# OpenTallas memory compiler (tools/mem_compiler), ASAP7 abstract view, track-aligned v2 (build_aligned_v2.py)
VERSION 5.7 ;
BUSBITCHARS "[]" ;
DIVIDERCHAR "/" ;
PROPERTYDEFINITIONS
  MACRO width INTEGER ;
  MACRO depth INTEGER ;
  MACRO banks INTEGER ;
END PROPERTYDEFINITIONS
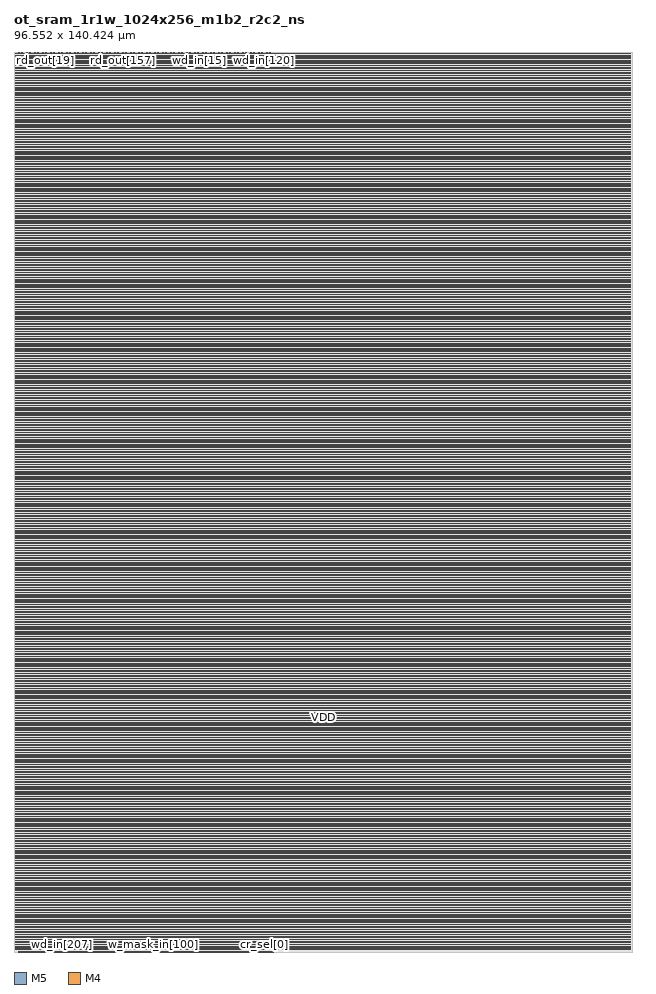
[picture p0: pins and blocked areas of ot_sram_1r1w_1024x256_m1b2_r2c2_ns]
MACRO ot_sram_1r1w_1024x256_m1b2_r2c2_ns
  PROPERTY width 256 ;
  PROPERTY depth 1024 ;
  PROPERTY banks 2 ;
  FOREIGN ot_sram_1r1w_1024x256_m1b2_r2c2_ns 0 0 ;
  SYMMETRY X Y ;
  SIZE 96.552 BY 140.424 ;
  CLASS BLOCK ;
  PIN clk
    DIRECTION INPUT ;
    USE CLOCK ;
    SHAPE ABUTMENT ;
    PORT
      LAYER M5 ;
      RECT 0.768 140.400 0.792 140.424 ;
    END
  END clk
  PIN r_ce_in
    DIRECTION INPUT ;
    USE SIGNAL ;
    SHAPE ABUTMENT ;
    PORT
      LAYER M5 ;
      RECT 0.864 140.400 0.888 140.424 ;
    END
  END r_ce_in
  PIN r_addr_in[0]
    DIRECTION INPUT ;
    USE SIGNAL ;
    SHAPE ABUTMENT ;
    PORT
      LAYER M5 ;
      RECT 0.960 140.400 0.984 140.424 ;
    END
  END r_addr_in[0]
  PIN r_addr_in[1]
    DIRECTION INPUT ;
    USE SIGNAL ;
    SHAPE ABUTMENT ;
    PORT
      LAYER M5 ;
      RECT 1.056 140.400 1.080 140.424 ;
    END
  END r_addr_in[1]
  PIN r_addr_in[2]
    DIRECTION INPUT ;
    USE SIGNAL ;
    SHAPE ABUTMENT ;
    PORT
      LAYER M5 ;
      RECT 1.152 140.400 1.176 140.424 ;
    END
  END r_addr_in[2]
  PIN r_addr_in[3]
    DIRECTION INPUT ;
    USE SIGNAL ;
    SHAPE ABUTMENT ;
    PORT
      LAYER M5 ;
      RECT 1.248 140.400 1.272 140.424 ;
    END
  END r_addr_in[3]
  PIN r_addr_in[4]
    DIRECTION INPUT ;
    USE SIGNAL ;
    SHAPE ABUTMENT ;
    PORT
      LAYER M5 ;
      RECT 1.344 140.400 1.368 140.424 ;
    END
  END r_addr_in[4]
  PIN r_addr_in[5]
    DIRECTION INPUT ;
    USE SIGNAL ;
    SHAPE ABUTMENT ;
    PORT
      LAYER M5 ;
      RECT 1.440 140.400 1.464 140.424 ;
    END
  END r_addr_in[5]
  PIN r_addr_in[6]
    DIRECTION INPUT ;
    USE SIGNAL ;
    SHAPE ABUTMENT ;
    PORT
      LAYER M5 ;
      RECT 1.536 140.400 1.560 140.424 ;
    END
  END r_addr_in[6]
  PIN r_addr_in[7]
    DIRECTION INPUT ;
    USE SIGNAL ;
    SHAPE ABUTMENT ;
    PORT
      LAYER M5 ;
      RECT 1.632 140.400 1.656 140.424 ;
    END
  END r_addr_in[7]
  PIN r_addr_in[8]
    DIRECTION INPUT ;
    USE SIGNAL ;
    SHAPE ABUTMENT ;
    PORT
      LAYER M5 ;
      RECT 1.728 140.400 1.752 140.424 ;
    END
  END r_addr_in[8]
  PIN r_addr_in[9]
    DIRECTION INPUT ;
    USE SIGNAL ;
    SHAPE ABUTMENT ;
    PORT
      LAYER M5 ;
      RECT 1.824 140.400 1.848 140.424 ;
    END
  END r_addr_in[9]
  PIN rd_out[0]
    DIRECTION OUTPUT ;
    USE SIGNAL ;
    SHAPE ABUTMENT ;
    PORT
      LAYER M5 ;
      RECT 1.920 140.400 1.944 140.424 ;
    END
  END rd_out[0]
  PIN rd_out[1]
    DIRECTION OUTPUT ;
    USE SIGNAL ;
    SHAPE ABUTMENT ;
    PORT
      LAYER M5 ;
      RECT 2.016 140.400 2.040 140.424 ;
    END
  END rd_out[1]
  PIN rd_out[2]
    DIRECTION OUTPUT ;
    USE SIGNAL ;
    SHAPE ABUTMENT ;
    PORT
      LAYER M5 ;
      RECT 2.112 140.400 2.136 140.424 ;
    END
  END rd_out[2]
  PIN rd_out[3]
    DIRECTION OUTPUT ;
    USE SIGNAL ;
    SHAPE ABUTMENT ;
    PORT
      LAYER M5 ;
      RECT 2.208 140.400 2.232 140.424 ;
    END
  END rd_out[3]
  PIN rd_out[4]
    DIRECTION OUTPUT ;
    USE SIGNAL ;
    SHAPE ABUTMENT ;
    PORT
      LAYER M5 ;
      RECT 2.304 140.400 2.328 140.424 ;
    END
  END rd_out[4]
  PIN rd_out[5]
    DIRECTION OUTPUT ;
    USE SIGNAL ;
    SHAPE ABUTMENT ;
    PORT
      LAYER M5 ;
      RECT 2.400 140.400 2.424 140.424 ;
    END
  END rd_out[5]
  PIN rd_out[6]
    DIRECTION OUTPUT ;
    USE SIGNAL ;
    SHAPE ABUTMENT ;
    PORT
      LAYER M5 ;
      RECT 2.496 140.400 2.520 140.424 ;
    END
  END rd_out[6]
  PIN rd_out[7]
    DIRECTION OUTPUT ;
    USE SIGNAL ;
    SHAPE ABUTMENT ;
    PORT
      LAYER M5 ;
      RECT 2.592 140.400 2.616 140.424 ;
    END
  END rd_out[7]
  PIN rd_out[8]
    DIRECTION OUTPUT ;
    USE SIGNAL ;
    SHAPE ABUTMENT ;
    PORT
      LAYER M5 ;
      RECT 2.688 140.400 2.712 140.424 ;
    END
  END rd_out[8]
  PIN rd_out[9]
    DIRECTION OUTPUT ;
    USE SIGNAL ;
    SHAPE ABUTMENT ;
    PORT
      LAYER M5 ;
      RECT 2.784 140.400 2.808 140.424 ;
    END
  END rd_out[9]
  PIN rd_out[10]
    DIRECTION OUTPUT ;
    USE SIGNAL ;
    SHAPE ABUTMENT ;
    PORT
      LAYER M5 ;
      RECT 2.880 140.400 2.904 140.424 ;
    END
  END rd_out[10]
  PIN rd_out[11]
    DIRECTION OUTPUT ;
    USE SIGNAL ;
    SHAPE ABUTMENT ;
    PORT
      LAYER M5 ;
      RECT 2.976 140.400 3.000 140.424 ;
    END
  END rd_out[11]
  PIN rd_out[12]
    DIRECTION OUTPUT ;
    USE SIGNAL ;
    SHAPE ABUTMENT ;
    PORT
      LAYER M5 ;
      RECT 3.072 140.400 3.096 140.424 ;
    END
  END rd_out[12]
  PIN rd_out[13]
    DIRECTION OUTPUT ;
    USE SIGNAL ;
    SHAPE ABUTMENT ;
    PORT
      LAYER M5 ;
      RECT 3.168 140.400 3.192 140.424 ;
    END
  END rd_out[13]
  PIN rd_out[14]
    DIRECTION OUTPUT ;
    USE SIGNAL ;
    SHAPE ABUTMENT ;
    PORT
      LAYER M5 ;
      RECT 3.264 140.400 3.288 140.424 ;
    END
  END rd_out[14]
  PIN rd_out[15]
    DIRECTION OUTPUT ;
    USE SIGNAL ;
    SHAPE ABUTMENT ;
    PORT
      LAYER M5 ;
      RECT 3.360 140.400 3.384 140.424 ;
    END
  END rd_out[15]
  PIN rd_out[16]
    DIRECTION OUTPUT ;
    USE SIGNAL ;
    SHAPE ABUTMENT ;
    PORT
      LAYER M5 ;
      RECT 3.456 140.400 3.480 140.424 ;
    END
  END rd_out[16]
  PIN rd_out[17]
    DIRECTION OUTPUT ;
    USE SIGNAL ;
    SHAPE ABUTMENT ;
    PORT
      LAYER M5 ;
      RECT 3.552 140.400 3.576 140.424 ;
    END
  END rd_out[17]
  PIN rd_out[18]
    DIRECTION OUTPUT ;
    USE SIGNAL ;
    SHAPE ABUTMENT ;
    PORT
      LAYER M5 ;
      RECT 3.648 140.400 3.672 140.424 ;
    END
  END rd_out[18]
  PIN rd_out[19]
    DIRECTION OUTPUT ;
    USE SIGNAL ;
    SHAPE ABUTMENT ;
    PORT
      LAYER M5 ;
      RECT 3.744 140.400 3.768 140.424 ;
    END
  END rd_out[19]
  PIN rd_out[20]
    DIRECTION OUTPUT ;
    USE SIGNAL ;
    SHAPE ABUTMENT ;
    PORT
      LAYER M5 ;
      RECT 3.840 140.400 3.864 140.424 ;
    END
  END rd_out[20]
  PIN rd_out[21]
    DIRECTION OUTPUT ;
    USE SIGNAL ;
    SHAPE ABUTMENT ;
    PORT
      LAYER M5 ;
      RECT 3.936 140.400 3.960 140.424 ;
    END
  END rd_out[21]
  PIN rd_out[22]
    DIRECTION OUTPUT ;
    USE SIGNAL ;
    SHAPE ABUTMENT ;
    PORT
      LAYER M5 ;
      RECT 4.032 140.400 4.056 140.424 ;
    END
  END rd_out[22]
  PIN rd_out[23]
    DIRECTION OUTPUT ;
    USE SIGNAL ;
    SHAPE ABUTMENT ;
    PORT
      LAYER M5 ;
      RECT 4.128 140.400 4.152 140.424 ;
    END
  END rd_out[23]
  PIN rd_out[24]
    DIRECTION OUTPUT ;
    USE SIGNAL ;
    SHAPE ABUTMENT ;
    PORT
      LAYER M5 ;
      RECT 4.224 140.400 4.248 140.424 ;
    END
  END rd_out[24]
  PIN rd_out[25]
    DIRECTION OUTPUT ;
    USE SIGNAL ;
    SHAPE ABUTMENT ;
    PORT
      LAYER M5 ;
      RECT 4.320 140.400 4.344 140.424 ;
    END
  END rd_out[25]
  PIN rd_out[26]
    DIRECTION OUTPUT ;
    USE SIGNAL ;
    SHAPE ABUTMENT ;
    PORT
      LAYER M5 ;
      RECT 4.416 140.400 4.440 140.424 ;
    END
  END rd_out[26]
  PIN rd_out[27]
    DIRECTION OUTPUT ;
    USE SIGNAL ;
    SHAPE ABUTMENT ;
    PORT
      LAYER M5 ;
      RECT 4.512 140.400 4.536 140.424 ;
    END
  END rd_out[27]
  PIN rd_out[28]
    DIRECTION OUTPUT ;
    USE SIGNAL ;
    SHAPE ABUTMENT ;
    PORT
      LAYER M5 ;
      RECT 4.608 140.400 4.632 140.424 ;
    END
  END rd_out[28]
  PIN rd_out[29]
    DIRECTION OUTPUT ;
    USE SIGNAL ;
    SHAPE ABUTMENT ;
    PORT
      LAYER M5 ;
      RECT 4.704 140.400 4.728 140.424 ;
    END
  END rd_out[29]
  PIN rd_out[30]
    DIRECTION OUTPUT ;
    USE SIGNAL ;
    SHAPE ABUTMENT ;
    PORT
      LAYER M5 ;
      RECT 4.800 140.400 4.824 140.424 ;
    END
  END rd_out[30]
  PIN rd_out[31]
    DIRECTION OUTPUT ;
    USE SIGNAL ;
    SHAPE ABUTMENT ;
    PORT
      LAYER M5 ;
      RECT 4.896 140.400 4.920 140.424 ;
    END
  END rd_out[31]
  PIN rd_out[32]
    DIRECTION OUTPUT ;
    USE SIGNAL ;
    SHAPE ABUTMENT ;
    PORT
      LAYER M5 ;
      RECT 4.992 140.400 5.016 140.424 ;
    END
  END rd_out[32]
  PIN rd_out[33]
    DIRECTION OUTPUT ;
    USE SIGNAL ;
    SHAPE ABUTMENT ;
    PORT
      LAYER M5 ;
      RECT 5.088 140.400 5.112 140.424 ;
    END
  END rd_out[33]
  PIN rd_out[34]
    DIRECTION OUTPUT ;
    USE SIGNAL ;
    SHAPE ABUTMENT ;
    PORT
      LAYER M5 ;
      RECT 5.184 140.400 5.208 140.424 ;
    END
  END rd_out[34]
  PIN rd_out[35]
    DIRECTION OUTPUT ;
    USE SIGNAL ;
    SHAPE ABUTMENT ;
    PORT
      LAYER M5 ;
      RECT 5.280 140.400 5.304 140.424 ;
    END
  END rd_out[35]
  PIN rd_out[36]
    DIRECTION OUTPUT ;
    USE SIGNAL ;
    SHAPE ABUTMENT ;
    PORT
      LAYER M5 ;
      RECT 5.376 140.400 5.400 140.424 ;
    END
  END rd_out[36]
  PIN rd_out[37]
    DIRECTION OUTPUT ;
    USE SIGNAL ;
    SHAPE ABUTMENT ;
    PORT
      LAYER M5 ;
      RECT 5.472 140.400 5.496 140.424 ;
    END
  END rd_out[37]
  PIN rd_out[38]
    DIRECTION OUTPUT ;
    USE SIGNAL ;
    SHAPE ABUTMENT ;
    PORT
      LAYER M5 ;
      RECT 5.568 140.400 5.592 140.424 ;
    END
  END rd_out[38]
  PIN rd_out[39]
    DIRECTION OUTPUT ;
    USE SIGNAL ;
    SHAPE ABUTMENT ;
    PORT
      LAYER M5 ;
      RECT 5.664 140.400 5.688 140.424 ;
    END
  END rd_out[39]
  PIN rd_out[40]
    DIRECTION OUTPUT ;
    USE SIGNAL ;
    SHAPE ABUTMENT ;
    PORT
      LAYER M5 ;
      RECT 5.760 140.400 5.784 140.424 ;
    END
  END rd_out[40]
  PIN rd_out[41]
    DIRECTION OUTPUT ;
    USE SIGNAL ;
    SHAPE ABUTMENT ;
    PORT
      LAYER M5 ;
      RECT 5.856 140.400 5.880 140.424 ;
    END
  END rd_out[41]
  PIN rd_out[42]
    DIRECTION OUTPUT ;
    USE SIGNAL ;
    SHAPE ABUTMENT ;
    PORT
      LAYER M5 ;
      RECT 5.952 140.400 5.976 140.424 ;
    END
  END rd_out[42]
  PIN rd_out[43]
    DIRECTION OUTPUT ;
    USE SIGNAL ;
    SHAPE ABUTMENT ;
    PORT
      LAYER M5 ;
      RECT 6.048 140.400 6.072 140.424 ;
    END
  END rd_out[43]
  PIN rd_out[44]
    DIRECTION OUTPUT ;
    USE SIGNAL ;
    SHAPE ABUTMENT ;
    PORT
      LAYER M5 ;
      RECT 6.144 140.400 6.168 140.424 ;
    END
  END rd_out[44]
  PIN rd_out[45]
    DIRECTION OUTPUT ;
    USE SIGNAL ;
    SHAPE ABUTMENT ;
    PORT
      LAYER M5 ;
      RECT 6.240 140.400 6.264 140.424 ;
    END
  END rd_out[45]
  PIN rd_out[46]
    DIRECTION OUTPUT ;
    USE SIGNAL ;
    SHAPE ABUTMENT ;
    PORT
      LAYER M5 ;
      RECT 6.336 140.400 6.360 140.424 ;
    END
  END rd_out[46]
  PIN rd_out[47]
    DIRECTION OUTPUT ;
    USE SIGNAL ;
    SHAPE ABUTMENT ;
    PORT
      LAYER M5 ;
      RECT 6.432 140.400 6.456 140.424 ;
    END
  END rd_out[47]
  PIN rd_out[48]
    DIRECTION OUTPUT ;
    USE SIGNAL ;
    SHAPE ABUTMENT ;
    PORT
      LAYER M5 ;
      RECT 6.528 140.400 6.552 140.424 ;
    END
  END rd_out[48]
  PIN rd_out[49]
    DIRECTION OUTPUT ;
    USE SIGNAL ;
    SHAPE ABUTMENT ;
    PORT
      LAYER M5 ;
      RECT 6.624 140.400 6.648 140.424 ;
    END
  END rd_out[49]
  PIN rd_out[50]
    DIRECTION OUTPUT ;
    USE SIGNAL ;
    SHAPE ABUTMENT ;
    PORT
      LAYER M5 ;
      RECT 6.720 140.400 6.744 140.424 ;
    END
  END rd_out[50]
  PIN rd_out[51]
    DIRECTION OUTPUT ;
    USE SIGNAL ;
    SHAPE ABUTMENT ;
    PORT
      LAYER M5 ;
      RECT 6.816 140.400 6.840 140.424 ;
    END
  END rd_out[51]
  PIN rd_out[52]
    DIRECTION OUTPUT ;
    USE SIGNAL ;
    SHAPE ABUTMENT ;
    PORT
      LAYER M5 ;
      RECT 6.912 140.400 6.936 140.424 ;
    END
  END rd_out[52]
  PIN rd_out[53]
    DIRECTION OUTPUT ;
    USE SIGNAL ;
    SHAPE ABUTMENT ;
    PORT
      LAYER M5 ;
      RECT 7.008 140.400 7.032 140.424 ;
    END
  END rd_out[53]
  PIN rd_out[54]
    DIRECTION OUTPUT ;
    USE SIGNAL ;
    SHAPE ABUTMENT ;
    PORT
      LAYER M5 ;
      RECT 7.104 140.400 7.128 140.424 ;
    END
  END rd_out[54]
  PIN rd_out[55]
    DIRECTION OUTPUT ;
    USE SIGNAL ;
    SHAPE ABUTMENT ;
    PORT
      LAYER M5 ;
      RECT 7.200 140.400 7.224 140.424 ;
    END
  END rd_out[55]
  PIN rd_out[56]
    DIRECTION OUTPUT ;
    USE SIGNAL ;
    SHAPE ABUTMENT ;
    PORT
      LAYER M5 ;
      RECT 7.296 140.400 7.320 140.424 ;
    END
  END rd_out[56]
  PIN rd_out[57]
    DIRECTION OUTPUT ;
    USE SIGNAL ;
    SHAPE ABUTMENT ;
    PORT
      LAYER M5 ;
      RECT 7.392 140.400 7.416 140.424 ;
    END
  END rd_out[57]
  PIN rd_out[58]
    DIRECTION OUTPUT ;
    USE SIGNAL ;
    SHAPE ABUTMENT ;
    PORT
      LAYER M5 ;
      RECT 7.488 140.400 7.512 140.424 ;
    END
  END rd_out[58]
  PIN rd_out[59]
    DIRECTION OUTPUT ;
    USE SIGNAL ;
    SHAPE ABUTMENT ;
    PORT
      LAYER M5 ;
      RECT 7.584 140.400 7.608 140.424 ;
    END
  END rd_out[59]
  PIN rd_out[60]
    DIRECTION OUTPUT ;
    USE SIGNAL ;
    SHAPE ABUTMENT ;
    PORT
      LAYER M5 ;
      RECT 7.680 140.400 7.704 140.424 ;
    END
  END rd_out[60]
  PIN rd_out[61]
    DIRECTION OUTPUT ;
    USE SIGNAL ;
    SHAPE ABUTMENT ;
    PORT
      LAYER M5 ;
      RECT 7.776 140.400 7.800 140.424 ;
    END
  END rd_out[61]
  PIN rd_out[62]
    DIRECTION OUTPUT ;
    USE SIGNAL ;
    SHAPE ABUTMENT ;
    PORT
      LAYER M5 ;
      RECT 7.872 140.400 7.896 140.424 ;
    END
  END rd_out[62]
  PIN rd_out[63]
    DIRECTION OUTPUT ;
    USE SIGNAL ;
    SHAPE ABUTMENT ;
    PORT
      LAYER M5 ;
      RECT 7.968 140.400 7.992 140.424 ;
    END
  END rd_out[63]
  PIN rd_out[64]
    DIRECTION OUTPUT ;
    USE SIGNAL ;
    SHAPE ABUTMENT ;
    PORT
      LAYER M5 ;
      RECT 8.064 140.400 8.088 140.424 ;
    END
  END rd_out[64]
  PIN rd_out[65]
    DIRECTION OUTPUT ;
    USE SIGNAL ;
    SHAPE ABUTMENT ;
    PORT
      LAYER M5 ;
      RECT 8.160 140.400 8.184 140.424 ;
    END
  END rd_out[65]
  PIN rd_out[66]
    DIRECTION OUTPUT ;
    USE SIGNAL ;
    SHAPE ABUTMENT ;
    PORT
      LAYER M5 ;
      RECT 8.256 140.400 8.280 140.424 ;
    END
  END rd_out[66]
  PIN rd_out[67]
    DIRECTION OUTPUT ;
    USE SIGNAL ;
    SHAPE ABUTMENT ;
    PORT
      LAYER M5 ;
      RECT 8.352 140.400 8.376 140.424 ;
    END
  END rd_out[67]
  PIN rd_out[68]
    DIRECTION OUTPUT ;
    USE SIGNAL ;
    SHAPE ABUTMENT ;
    PORT
      LAYER M5 ;
      RECT 8.448 140.400 8.472 140.424 ;
    END
  END rd_out[68]
  PIN rd_out[69]
    DIRECTION OUTPUT ;
    USE SIGNAL ;
    SHAPE ABUTMENT ;
    PORT
      LAYER M5 ;
      RECT 8.544 140.400 8.568 140.424 ;
    END
  END rd_out[69]
  PIN rd_out[70]
    DIRECTION OUTPUT ;
    USE SIGNAL ;
    SHAPE ABUTMENT ;
    PORT
      LAYER M5 ;
      RECT 8.640 140.400 8.664 140.424 ;
    END
  END rd_out[70]
  PIN rd_out[71]
    DIRECTION OUTPUT ;
    USE SIGNAL ;
    SHAPE ABUTMENT ;
    PORT
      LAYER M5 ;
      RECT 8.736 140.400 8.760 140.424 ;
    END
  END rd_out[71]
  PIN rd_out[72]
    DIRECTION OUTPUT ;
    USE SIGNAL ;
    SHAPE ABUTMENT ;
    PORT
      LAYER M5 ;
      RECT 8.832 140.400 8.856 140.424 ;
    END
  END rd_out[72]
  PIN rd_out[73]
    DIRECTION OUTPUT ;
    USE SIGNAL ;
    SHAPE ABUTMENT ;
    PORT
      LAYER M5 ;
      RECT 8.928 140.400 8.952 140.424 ;
    END
  END rd_out[73]
  PIN rd_out[74]
    DIRECTION OUTPUT ;
    USE SIGNAL ;
    SHAPE ABUTMENT ;
    PORT
      LAYER M5 ;
      RECT 9.024 140.400 9.048 140.424 ;
    END
  END rd_out[74]
  PIN rd_out[75]
    DIRECTION OUTPUT ;
    USE SIGNAL ;
    SHAPE ABUTMENT ;
    PORT
      LAYER M5 ;
      RECT 9.120 140.400 9.144 140.424 ;
    END
  END rd_out[75]
  PIN rd_out[76]
    DIRECTION OUTPUT ;
    USE SIGNAL ;
    SHAPE ABUTMENT ;
    PORT
      LAYER M5 ;
      RECT 9.216 140.400 9.240 140.424 ;
    END
  END rd_out[76]
  PIN rd_out[77]
    DIRECTION OUTPUT ;
    USE SIGNAL ;
    SHAPE ABUTMENT ;
    PORT
      LAYER M5 ;
      RECT 9.312 140.400 9.336 140.424 ;
    END
  END rd_out[77]
  PIN rd_out[78]
    DIRECTION OUTPUT ;
    USE SIGNAL ;
    SHAPE ABUTMENT ;
    PORT
      LAYER M5 ;
      RECT 9.408 140.400 9.432 140.424 ;
    END
  END rd_out[78]
  PIN rd_out[79]
    DIRECTION OUTPUT ;
    USE SIGNAL ;
    SHAPE ABUTMENT ;
    PORT
      LAYER M5 ;
      RECT 9.504 140.400 9.528 140.424 ;
    END
  END rd_out[79]
  PIN rd_out[80]
    DIRECTION OUTPUT ;
    USE SIGNAL ;
    SHAPE ABUTMENT ;
    PORT
      LAYER M5 ;
      RECT 9.600 140.400 9.624 140.424 ;
    END
  END rd_out[80]
  PIN rd_out[81]
    DIRECTION OUTPUT ;
    USE SIGNAL ;
    SHAPE ABUTMENT ;
    PORT
      LAYER M5 ;
      RECT 9.696 140.400 9.720 140.424 ;
    END
  END rd_out[81]
  PIN rd_out[82]
    DIRECTION OUTPUT ;
    USE SIGNAL ;
    SHAPE ABUTMENT ;
    PORT
      LAYER M5 ;
      RECT 9.792 140.400 9.816 140.424 ;
    END
  END rd_out[82]
  PIN rd_out[83]
    DIRECTION OUTPUT ;
    USE SIGNAL ;
    SHAPE ABUTMENT ;
    PORT
      LAYER M5 ;
      RECT 9.888 140.400 9.912 140.424 ;
    END
  END rd_out[83]
  PIN rd_out[84]
    DIRECTION OUTPUT ;
    USE SIGNAL ;
    SHAPE ABUTMENT ;
    PORT
      LAYER M5 ;
      RECT 9.984 140.400 10.008 140.424 ;
    END
  END rd_out[84]
  PIN rd_out[85]
    DIRECTION OUTPUT ;
    USE SIGNAL ;
    SHAPE ABUTMENT ;
    PORT
      LAYER M5 ;
      RECT 10.080 140.400 10.104 140.424 ;
    END
  END rd_out[85]
  PIN rd_out[86]
    DIRECTION OUTPUT ;
    USE SIGNAL ;
    SHAPE ABUTMENT ;
    PORT
      LAYER M5 ;
      RECT 10.176 140.400 10.200 140.424 ;
    END
  END rd_out[86]
  PIN rd_out[87]
    DIRECTION OUTPUT ;
    USE SIGNAL ;
    SHAPE ABUTMENT ;
    PORT
      LAYER M5 ;
      RECT 10.272 140.400 10.296 140.424 ;
    END
  END rd_out[87]
  PIN rd_out[88]
    DIRECTION OUTPUT ;
    USE SIGNAL ;
    SHAPE ABUTMENT ;
    PORT
      LAYER M5 ;
      RECT 10.368 140.400 10.392 140.424 ;
    END
  END rd_out[88]
  PIN rd_out[89]
    DIRECTION OUTPUT ;
    USE SIGNAL ;
    SHAPE ABUTMENT ;
    PORT
      LAYER M5 ;
      RECT 10.464 140.400 10.488 140.424 ;
    END
  END rd_out[89]
  PIN rd_out[90]
    DIRECTION OUTPUT ;
    USE SIGNAL ;
    SHAPE ABUTMENT ;
    PORT
      LAYER M5 ;
      RECT 10.560 140.400 10.584 140.424 ;
    END
  END rd_out[90]
  PIN rd_out[91]
    DIRECTION OUTPUT ;
    USE SIGNAL ;
    SHAPE ABUTMENT ;
    PORT
      LAYER M5 ;
      RECT 10.656 140.400 10.680 140.424 ;
    END
  END rd_out[91]
  PIN rd_out[92]
    DIRECTION OUTPUT ;
    USE SIGNAL ;
    SHAPE ABUTMENT ;
    PORT
      LAYER M5 ;
      RECT 10.752 140.400 10.776 140.424 ;
    END
  END rd_out[92]
  PIN rd_out[93]
    DIRECTION OUTPUT ;
    USE SIGNAL ;
    SHAPE ABUTMENT ;
    PORT
      LAYER M5 ;
      RECT 10.848 140.400 10.872 140.424 ;
    END
  END rd_out[93]
  PIN rd_out[94]
    DIRECTION OUTPUT ;
    USE SIGNAL ;
    SHAPE ABUTMENT ;
    PORT
      LAYER M5 ;
      RECT 10.944 140.400 10.968 140.424 ;
    END
  END rd_out[94]
  PIN rd_out[95]
    DIRECTION OUTPUT ;
    USE SIGNAL ;
    SHAPE ABUTMENT ;
    PORT
      LAYER M5 ;
      RECT 11.040 140.400 11.064 140.424 ;
    END
  END rd_out[95]
  PIN rd_out[96]
    DIRECTION OUTPUT ;
    USE SIGNAL ;
    SHAPE ABUTMENT ;
    PORT
      LAYER M5 ;
      RECT 11.136 140.400 11.160 140.424 ;
    END
  END rd_out[96]
  PIN rd_out[97]
    DIRECTION OUTPUT ;
    USE SIGNAL ;
    SHAPE ABUTMENT ;
    PORT
      LAYER M5 ;
      RECT 11.232 140.400 11.256 140.424 ;
    END
  END rd_out[97]
  PIN rd_out[98]
    DIRECTION OUTPUT ;
    USE SIGNAL ;
    SHAPE ABUTMENT ;
    PORT
      LAYER M5 ;
      RECT 11.328 140.400 11.352 140.424 ;
    END
  END rd_out[98]
  PIN rd_out[99]
    DIRECTION OUTPUT ;
    USE SIGNAL ;
    SHAPE ABUTMENT ;
    PORT
      LAYER M5 ;
      RECT 11.424 140.400 11.448 140.424 ;
    END
  END rd_out[99]
  PIN rd_out[100]
    DIRECTION OUTPUT ;
    USE SIGNAL ;
    SHAPE ABUTMENT ;
    PORT
      LAYER M5 ;
      RECT 11.520 140.400 11.544 140.424 ;
    END
  END rd_out[100]
  PIN rd_out[101]
    DIRECTION OUTPUT ;
    USE SIGNAL ;
    SHAPE ABUTMENT ;
    PORT
      LAYER M5 ;
      RECT 11.616 140.400 11.640 140.424 ;
    END
  END rd_out[101]
  PIN rd_out[102]
    DIRECTION OUTPUT ;
    USE SIGNAL ;
    SHAPE ABUTMENT ;
    PORT
      LAYER M5 ;
      RECT 11.712 140.400 11.736 140.424 ;
    END
  END rd_out[102]
  PIN rd_out[103]
    DIRECTION OUTPUT ;
    USE SIGNAL ;
    SHAPE ABUTMENT ;
    PORT
      LAYER M5 ;
      RECT 11.808 140.400 11.832 140.424 ;
    END
  END rd_out[103]
  PIN rd_out[104]
    DIRECTION OUTPUT ;
    USE SIGNAL ;
    SHAPE ABUTMENT ;
    PORT
      LAYER M5 ;
      RECT 11.904 140.400 11.928 140.424 ;
    END
  END rd_out[104]
  PIN rd_out[105]
    DIRECTION OUTPUT ;
    USE SIGNAL ;
    SHAPE ABUTMENT ;
    PORT
      LAYER M5 ;
      RECT 12.000 140.400 12.024 140.424 ;
    END
  END rd_out[105]
  PIN rd_out[106]
    DIRECTION OUTPUT ;
    USE SIGNAL ;
    SHAPE ABUTMENT ;
    PORT
      LAYER M5 ;
      RECT 12.096 140.400 12.120 140.424 ;
    END
  END rd_out[106]
  PIN rd_out[107]
    DIRECTION OUTPUT ;
    USE SIGNAL ;
    SHAPE ABUTMENT ;
    PORT
      LAYER M5 ;
      RECT 12.192 140.400 12.216 140.424 ;
    END
  END rd_out[107]
  PIN rd_out[108]
    DIRECTION OUTPUT ;
    USE SIGNAL ;
    SHAPE ABUTMENT ;
    PORT
      LAYER M5 ;
      RECT 12.288 140.400 12.312 140.424 ;
    END
  END rd_out[108]
  PIN rd_out[109]
    DIRECTION OUTPUT ;
    USE SIGNAL ;
    SHAPE ABUTMENT ;
    PORT
      LAYER M5 ;
      RECT 12.384 140.400 12.408 140.424 ;
    END
  END rd_out[109]
  PIN rd_out[110]
    DIRECTION OUTPUT ;
    USE SIGNAL ;
    SHAPE ABUTMENT ;
    PORT
      LAYER M5 ;
      RECT 12.480 140.400 12.504 140.424 ;
    END
  END rd_out[110]
  PIN rd_out[111]
    DIRECTION OUTPUT ;
    USE SIGNAL ;
    SHAPE ABUTMENT ;
    PORT
      LAYER M5 ;
      RECT 12.576 140.400 12.600 140.424 ;
    END
  END rd_out[111]
  PIN rd_out[112]
    DIRECTION OUTPUT ;
    USE SIGNAL ;
    SHAPE ABUTMENT ;
    PORT
      LAYER M5 ;
      RECT 12.672 140.400 12.696 140.424 ;
    END
  END rd_out[112]
  PIN rd_out[113]
    DIRECTION OUTPUT ;
    USE SIGNAL ;
    SHAPE ABUTMENT ;
    PORT
      LAYER M5 ;
      RECT 12.768 140.400 12.792 140.424 ;
    END
  END rd_out[113]
  PIN rd_out[114]
    DIRECTION OUTPUT ;
    USE SIGNAL ;
    SHAPE ABUTMENT ;
    PORT
      LAYER M5 ;
      RECT 12.864 140.400 12.888 140.424 ;
    END
  END rd_out[114]
  PIN rd_out[115]
    DIRECTION OUTPUT ;
    USE SIGNAL ;
    SHAPE ABUTMENT ;
    PORT
      LAYER M5 ;
      RECT 12.960 140.400 12.984 140.424 ;
    END
  END rd_out[115]
  PIN rd_out[116]
    DIRECTION OUTPUT ;
    USE SIGNAL ;
    SHAPE ABUTMENT ;
    PORT
      LAYER M5 ;
      RECT 13.056 140.400 13.080 140.424 ;
    END
  END rd_out[116]
  PIN rd_out[117]
    DIRECTION OUTPUT ;
    USE SIGNAL ;
    SHAPE ABUTMENT ;
    PORT
      LAYER M5 ;
      RECT 13.152 140.400 13.176 140.424 ;
    END
  END rd_out[117]
  PIN rd_out[118]
    DIRECTION OUTPUT ;
    USE SIGNAL ;
    SHAPE ABUTMENT ;
    PORT
      LAYER M5 ;
      RECT 13.248 140.400 13.272 140.424 ;
    END
  END rd_out[118]
  PIN rd_out[119]
    DIRECTION OUTPUT ;
    USE SIGNAL ;
    SHAPE ABUTMENT ;
    PORT
      LAYER M5 ;
      RECT 13.344 140.400 13.368 140.424 ;
    END
  END rd_out[119]
  PIN rd_out[120]
    DIRECTION OUTPUT ;
    USE SIGNAL ;
    SHAPE ABUTMENT ;
    PORT
      LAYER M5 ;
      RECT 13.440 140.400 13.464 140.424 ;
    END
  END rd_out[120]
  PIN rd_out[121]
    DIRECTION OUTPUT ;
    USE SIGNAL ;
    SHAPE ABUTMENT ;
    PORT
      LAYER M5 ;
      RECT 13.536 140.400 13.560 140.424 ;
    END
  END rd_out[121]
  PIN rd_out[122]
    DIRECTION OUTPUT ;
    USE SIGNAL ;
    SHAPE ABUTMENT ;
    PORT
      LAYER M5 ;
      RECT 13.632 140.400 13.656 140.424 ;
    END
  END rd_out[122]
  PIN rd_out[123]
    DIRECTION OUTPUT ;
    USE SIGNAL ;
    SHAPE ABUTMENT ;
    PORT
      LAYER M5 ;
      RECT 13.728 140.400 13.752 140.424 ;
    END
  END rd_out[123]
  PIN rd_out[124]
    DIRECTION OUTPUT ;
    USE SIGNAL ;
    SHAPE ABUTMENT ;
    PORT
      LAYER M5 ;
      RECT 13.824 140.400 13.848 140.424 ;
    END
  END rd_out[124]
  PIN rd_out[125]
    DIRECTION OUTPUT ;
    USE SIGNAL ;
    SHAPE ABUTMENT ;
    PORT
      LAYER M5 ;
      RECT 13.920 140.400 13.944 140.424 ;
    END
  END rd_out[125]
  PIN rd_out[126]
    DIRECTION OUTPUT ;
    USE SIGNAL ;
    SHAPE ABUTMENT ;
    PORT
      LAYER M5 ;
      RECT 14.016 140.400 14.040 140.424 ;
    END
  END rd_out[126]
  PIN rd_out[127]
    DIRECTION OUTPUT ;
    USE SIGNAL ;
    SHAPE ABUTMENT ;
    PORT
      LAYER M5 ;
      RECT 14.112 140.400 14.136 140.424 ;
    END
  END rd_out[127]
  PIN rd_out[128]
    DIRECTION OUTPUT ;
    USE SIGNAL ;
    SHAPE ABUTMENT ;
    PORT
      LAYER M5 ;
      RECT 14.208 140.400 14.232 140.424 ;
    END
  END rd_out[128]
  PIN rd_out[129]
    DIRECTION OUTPUT ;
    USE SIGNAL ;
    SHAPE ABUTMENT ;
    PORT
      LAYER M5 ;
      RECT 14.304 140.400 14.328 140.424 ;
    END
  END rd_out[129]
  PIN rd_out[130]
    DIRECTION OUTPUT ;
    USE SIGNAL ;
    SHAPE ABUTMENT ;
    PORT
      LAYER M5 ;
      RECT 14.400 140.400 14.424 140.424 ;
    END
  END rd_out[130]
  PIN rd_out[131]
    DIRECTION OUTPUT ;
    USE SIGNAL ;
    SHAPE ABUTMENT ;
    PORT
      LAYER M5 ;
      RECT 14.496 140.400 14.520 140.424 ;
    END
  END rd_out[131]
  PIN rd_out[132]
    DIRECTION OUTPUT ;
    USE SIGNAL ;
    SHAPE ABUTMENT ;
    PORT
      LAYER M5 ;
      RECT 14.592 140.400 14.616 140.424 ;
    END
  END rd_out[132]
  PIN rd_out[133]
    DIRECTION OUTPUT ;
    USE SIGNAL ;
    SHAPE ABUTMENT ;
    PORT
      LAYER M5 ;
      RECT 14.688 140.400 14.712 140.424 ;
    END
  END rd_out[133]
  PIN rd_out[134]
    DIRECTION OUTPUT ;
    USE SIGNAL ;
    SHAPE ABUTMENT ;
    PORT
      LAYER M5 ;
      RECT 14.784 140.400 14.808 140.424 ;
    END
  END rd_out[134]
  PIN rd_out[135]
    DIRECTION OUTPUT ;
    USE SIGNAL ;
    SHAPE ABUTMENT ;
    PORT
      LAYER M5 ;
      RECT 14.880 140.400 14.904 140.424 ;
    END
  END rd_out[135]
  PIN rd_out[136]
    DIRECTION OUTPUT ;
    USE SIGNAL ;
    SHAPE ABUTMENT ;
    PORT
      LAYER M5 ;
      RECT 14.976 140.400 15.000 140.424 ;
    END
  END rd_out[136]
  PIN rd_out[137]
    DIRECTION OUTPUT ;
    USE SIGNAL ;
    SHAPE ABUTMENT ;
    PORT
      LAYER M5 ;
      RECT 15.072 140.400 15.096 140.424 ;
    END
  END rd_out[137]
  PIN rd_out[138]
    DIRECTION OUTPUT ;
    USE SIGNAL ;
    SHAPE ABUTMENT ;
    PORT
      LAYER M5 ;
      RECT 15.168 140.400 15.192 140.424 ;
    END
  END rd_out[138]
  PIN rd_out[139]
    DIRECTION OUTPUT ;
    USE SIGNAL ;
    SHAPE ABUTMENT ;
    PORT
      LAYER M5 ;
      RECT 15.264 140.400 15.288 140.424 ;
    END
  END rd_out[139]
  PIN rd_out[140]
    DIRECTION OUTPUT ;
    USE SIGNAL ;
    SHAPE ABUTMENT ;
    PORT
      LAYER M5 ;
      RECT 15.360 140.400 15.384 140.424 ;
    END
  END rd_out[140]
  PIN rd_out[141]
    DIRECTION OUTPUT ;
    USE SIGNAL ;
    SHAPE ABUTMENT ;
    PORT
      LAYER M5 ;
      RECT 15.456 140.400 15.480 140.424 ;
    END
  END rd_out[141]
  PIN rd_out[142]
    DIRECTION OUTPUT ;
    USE SIGNAL ;
    SHAPE ABUTMENT ;
    PORT
      LAYER M5 ;
      RECT 15.552 140.400 15.576 140.424 ;
    END
  END rd_out[142]
  PIN rd_out[143]
    DIRECTION OUTPUT ;
    USE SIGNAL ;
    SHAPE ABUTMENT ;
    PORT
      LAYER M5 ;
      RECT 15.648 140.400 15.672 140.424 ;
    END
  END rd_out[143]
  PIN rd_out[144]
    DIRECTION OUTPUT ;
    USE SIGNAL ;
    SHAPE ABUTMENT ;
    PORT
      LAYER M5 ;
      RECT 15.744 140.400 15.768 140.424 ;
    END
  END rd_out[144]
  PIN rd_out[145]
    DIRECTION OUTPUT ;
    USE SIGNAL ;
    SHAPE ABUTMENT ;
    PORT
      LAYER M5 ;
      RECT 15.840 140.400 15.864 140.424 ;
    END
  END rd_out[145]
  PIN rd_out[146]
    DIRECTION OUTPUT ;
    USE SIGNAL ;
    SHAPE ABUTMENT ;
    PORT
      LAYER M5 ;
      RECT 15.936 140.400 15.960 140.424 ;
    END
  END rd_out[146]
  PIN rd_out[147]
    DIRECTION OUTPUT ;
    USE SIGNAL ;
    SHAPE ABUTMENT ;
    PORT
      LAYER M5 ;
      RECT 16.032 140.400 16.056 140.424 ;
    END
  END rd_out[147]
  PIN rd_out[148]
    DIRECTION OUTPUT ;
    USE SIGNAL ;
    SHAPE ABUTMENT ;
    PORT
      LAYER M5 ;
      RECT 16.128 140.400 16.152 140.424 ;
    END
  END rd_out[148]
  PIN rd_out[149]
    DIRECTION OUTPUT ;
    USE SIGNAL ;
    SHAPE ABUTMENT ;
    PORT
      LAYER M5 ;
      RECT 16.224 140.400 16.248 140.424 ;
    END
  END rd_out[149]
  PIN rd_out[150]
    DIRECTION OUTPUT ;
    USE SIGNAL ;
    SHAPE ABUTMENT ;
    PORT
      LAYER M5 ;
      RECT 16.320 140.400 16.344 140.424 ;
    END
  END rd_out[150]
  PIN rd_out[151]
    DIRECTION OUTPUT ;
    USE SIGNAL ;
    SHAPE ABUTMENT ;
    PORT
      LAYER M5 ;
      RECT 16.416 140.400 16.440 140.424 ;
    END
  END rd_out[151]
  PIN rd_out[152]
    DIRECTION OUTPUT ;
    USE SIGNAL ;
    SHAPE ABUTMENT ;
    PORT
      LAYER M5 ;
      RECT 16.512 140.400 16.536 140.424 ;
    END
  END rd_out[152]
  PIN rd_out[153]
    DIRECTION OUTPUT ;
    USE SIGNAL ;
    SHAPE ABUTMENT ;
    PORT
      LAYER M5 ;
      RECT 16.608 140.400 16.632 140.424 ;
    END
  END rd_out[153]
  PIN rd_out[154]
    DIRECTION OUTPUT ;
    USE SIGNAL ;
    SHAPE ABUTMENT ;
    PORT
      LAYER M5 ;
      RECT 16.704 140.400 16.728 140.424 ;
    END
  END rd_out[154]
  PIN rd_out[155]
    DIRECTION OUTPUT ;
    USE SIGNAL ;
    SHAPE ABUTMENT ;
    PORT
      LAYER M5 ;
      RECT 16.800 140.400 16.824 140.424 ;
    END
  END rd_out[155]
  PIN rd_out[156]
    DIRECTION OUTPUT ;
    USE SIGNAL ;
    SHAPE ABUTMENT ;
    PORT
      LAYER M5 ;
      RECT 16.896 140.400 16.920 140.424 ;
    END
  END rd_out[156]
  PIN rd_out[157]
    DIRECTION OUTPUT ;
    USE SIGNAL ;
    SHAPE ABUTMENT ;
    PORT
      LAYER M5 ;
      RECT 16.992 140.400 17.016 140.424 ;
    END
  END rd_out[157]
  PIN rd_out[158]
    DIRECTION OUTPUT ;
    USE SIGNAL ;
    SHAPE ABUTMENT ;
    PORT
      LAYER M5 ;
      RECT 17.088 140.400 17.112 140.424 ;
    END
  END rd_out[158]
  PIN rd_out[159]
    DIRECTION OUTPUT ;
    USE SIGNAL ;
    SHAPE ABUTMENT ;
    PORT
      LAYER M5 ;
      RECT 17.184 140.400 17.208 140.424 ;
    END
  END rd_out[159]
  PIN rd_out[160]
    DIRECTION OUTPUT ;
    USE SIGNAL ;
    SHAPE ABUTMENT ;
    PORT
      LAYER M5 ;
      RECT 17.280 140.400 17.304 140.424 ;
    END
  END rd_out[160]
  PIN rd_out[161]
    DIRECTION OUTPUT ;
    USE SIGNAL ;
    SHAPE ABUTMENT ;
    PORT
      LAYER M5 ;
      RECT 17.376 140.400 17.400 140.424 ;
    END
  END rd_out[161]
  PIN rd_out[162]
    DIRECTION OUTPUT ;
    USE SIGNAL ;
    SHAPE ABUTMENT ;
    PORT
      LAYER M5 ;
      RECT 17.472 140.400 17.496 140.424 ;
    END
  END rd_out[162]
  PIN rd_out[163]
    DIRECTION OUTPUT ;
    USE SIGNAL ;
    SHAPE ABUTMENT ;
    PORT
      LAYER M5 ;
      RECT 17.568 140.400 17.592 140.424 ;
    END
  END rd_out[163]
  PIN rd_out[164]
    DIRECTION OUTPUT ;
    USE SIGNAL ;
    SHAPE ABUTMENT ;
    PORT
      LAYER M5 ;
      RECT 17.664 140.400 17.688 140.424 ;
    END
  END rd_out[164]
  PIN rd_out[165]
    DIRECTION OUTPUT ;
    USE SIGNAL ;
    SHAPE ABUTMENT ;
    PORT
      LAYER M5 ;
      RECT 17.760 140.400 17.784 140.424 ;
    END
  END rd_out[165]
  PIN rd_out[166]
    DIRECTION OUTPUT ;
    USE SIGNAL ;
    SHAPE ABUTMENT ;
    PORT
      LAYER M5 ;
      RECT 17.856 140.400 17.880 140.424 ;
    END
  END rd_out[166]
  PIN rd_out[167]
    DIRECTION OUTPUT ;
    USE SIGNAL ;
    SHAPE ABUTMENT ;
    PORT
      LAYER M5 ;
      RECT 17.952 140.400 17.976 140.424 ;
    END
  END rd_out[167]
  PIN rd_out[168]
    DIRECTION OUTPUT ;
    USE SIGNAL ;
    SHAPE ABUTMENT ;
    PORT
      LAYER M5 ;
      RECT 18.048 140.400 18.072 140.424 ;
    END
  END rd_out[168]
  PIN rd_out[169]
    DIRECTION OUTPUT ;
    USE SIGNAL ;
    SHAPE ABUTMENT ;
    PORT
      LAYER M5 ;
      RECT 18.144 140.400 18.168 140.424 ;
    END
  END rd_out[169]
  PIN rd_out[170]
    DIRECTION OUTPUT ;
    USE SIGNAL ;
    SHAPE ABUTMENT ;
    PORT
      LAYER M5 ;
      RECT 18.240 140.400 18.264 140.424 ;
    END
  END rd_out[170]
  PIN rd_out[171]
    DIRECTION OUTPUT ;
    USE SIGNAL ;
    SHAPE ABUTMENT ;
    PORT
      LAYER M5 ;
      RECT 18.336 140.400 18.360 140.424 ;
    END
  END rd_out[171]
  PIN rd_out[172]
    DIRECTION OUTPUT ;
    USE SIGNAL ;
    SHAPE ABUTMENT ;
    PORT
      LAYER M5 ;
      RECT 18.432 140.400 18.456 140.424 ;
    END
  END rd_out[172]
  PIN rd_out[173]
    DIRECTION OUTPUT ;
    USE SIGNAL ;
    SHAPE ABUTMENT ;
    PORT
      LAYER M5 ;
      RECT 18.528 140.400 18.552 140.424 ;
    END
  END rd_out[173]
  PIN rd_out[174]
    DIRECTION OUTPUT ;
    USE SIGNAL ;
    SHAPE ABUTMENT ;
    PORT
      LAYER M5 ;
      RECT 18.624 140.400 18.648 140.424 ;
    END
  END rd_out[174]
  PIN rd_out[175]
    DIRECTION OUTPUT ;
    USE SIGNAL ;
    SHAPE ABUTMENT ;
    PORT
      LAYER M5 ;
      RECT 18.720 140.400 18.744 140.424 ;
    END
  END rd_out[175]
  PIN rd_out[176]
    DIRECTION OUTPUT ;
    USE SIGNAL ;
    SHAPE ABUTMENT ;
    PORT
      LAYER M5 ;
      RECT 18.816 140.400 18.840 140.424 ;
    END
  END rd_out[176]
  PIN rd_out[177]
    DIRECTION OUTPUT ;
    USE SIGNAL ;
    SHAPE ABUTMENT ;
    PORT
      LAYER M5 ;
      RECT 18.912 140.400 18.936 140.424 ;
    END
  END rd_out[177]
  PIN rd_out[178]
    DIRECTION OUTPUT ;
    USE SIGNAL ;
    SHAPE ABUTMENT ;
    PORT
      LAYER M5 ;
      RECT 19.008 140.400 19.032 140.424 ;
    END
  END rd_out[178]
  PIN rd_out[179]
    DIRECTION OUTPUT ;
    USE SIGNAL ;
    SHAPE ABUTMENT ;
    PORT
      LAYER M5 ;
      RECT 19.104 140.400 19.128 140.424 ;
    END
  END rd_out[179]
  PIN rd_out[180]
    DIRECTION OUTPUT ;
    USE SIGNAL ;
    SHAPE ABUTMENT ;
    PORT
      LAYER M5 ;
      RECT 19.200 140.400 19.224 140.424 ;
    END
  END rd_out[180]
  PIN rd_out[181]
    DIRECTION OUTPUT ;
    USE SIGNAL ;
    SHAPE ABUTMENT ;
    PORT
      LAYER M5 ;
      RECT 19.296 140.400 19.320 140.424 ;
    END
  END rd_out[181]
  PIN rd_out[182]
    DIRECTION OUTPUT ;
    USE SIGNAL ;
    SHAPE ABUTMENT ;
    PORT
      LAYER M5 ;
      RECT 19.392 140.400 19.416 140.424 ;
    END
  END rd_out[182]
  PIN rd_out[183]
    DIRECTION OUTPUT ;
    USE SIGNAL ;
    SHAPE ABUTMENT ;
    PORT
      LAYER M5 ;
      RECT 19.488 140.400 19.512 140.424 ;
    END
  END rd_out[183]
  PIN rd_out[184]
    DIRECTION OUTPUT ;
    USE SIGNAL ;
    SHAPE ABUTMENT ;
    PORT
      LAYER M5 ;
      RECT 19.584 140.400 19.608 140.424 ;
    END
  END rd_out[184]
  PIN rd_out[185]
    DIRECTION OUTPUT ;
    USE SIGNAL ;
    SHAPE ABUTMENT ;
    PORT
      LAYER M5 ;
      RECT 19.680 140.400 19.704 140.424 ;
    END
  END rd_out[185]
  PIN rd_out[186]
    DIRECTION OUTPUT ;
    USE SIGNAL ;
    SHAPE ABUTMENT ;
    PORT
      LAYER M5 ;
      RECT 19.776 140.400 19.800 140.424 ;
    END
  END rd_out[186]
  PIN rd_out[187]
    DIRECTION OUTPUT ;
    USE SIGNAL ;
    SHAPE ABUTMENT ;
    PORT
      LAYER M5 ;
      RECT 19.872 140.400 19.896 140.424 ;
    END
  END rd_out[187]
  PIN rd_out[188]
    DIRECTION OUTPUT ;
    USE SIGNAL ;
    SHAPE ABUTMENT ;
    PORT
      LAYER M5 ;
      RECT 19.968 140.400 19.992 140.424 ;
    END
  END rd_out[188]
  PIN rd_out[189]
    DIRECTION OUTPUT ;
    USE SIGNAL ;
    SHAPE ABUTMENT ;
    PORT
      LAYER M5 ;
      RECT 20.064 140.400 20.088 140.424 ;
    END
  END rd_out[189]
  PIN rd_out[190]
    DIRECTION OUTPUT ;
    USE SIGNAL ;
    SHAPE ABUTMENT ;
    PORT
      LAYER M5 ;
      RECT 20.160 140.400 20.184 140.424 ;
    END
  END rd_out[190]
  PIN rd_out[191]
    DIRECTION OUTPUT ;
    USE SIGNAL ;
    SHAPE ABUTMENT ;
    PORT
      LAYER M5 ;
      RECT 20.256 140.400 20.280 140.424 ;
    END
  END rd_out[191]
  PIN rd_out[192]
    DIRECTION OUTPUT ;
    USE SIGNAL ;
    SHAPE ABUTMENT ;
    PORT
      LAYER M5 ;
      RECT 20.352 140.400 20.376 140.424 ;
    END
  END rd_out[192]
  PIN rd_out[193]
    DIRECTION OUTPUT ;
    USE SIGNAL ;
    SHAPE ABUTMENT ;
    PORT
      LAYER M5 ;
      RECT 20.448 140.400 20.472 140.424 ;
    END
  END rd_out[193]
  PIN rd_out[194]
    DIRECTION OUTPUT ;
    USE SIGNAL ;
    SHAPE ABUTMENT ;
    PORT
      LAYER M5 ;
      RECT 20.544 140.400 20.568 140.424 ;
    END
  END rd_out[194]
  PIN rd_out[195]
    DIRECTION OUTPUT ;
    USE SIGNAL ;
    SHAPE ABUTMENT ;
    PORT
      LAYER M5 ;
      RECT 20.640 140.400 20.664 140.424 ;
    END
  END rd_out[195]
  PIN rd_out[196]
    DIRECTION OUTPUT ;
    USE SIGNAL ;
    SHAPE ABUTMENT ;
    PORT
      LAYER M5 ;
      RECT 20.736 140.400 20.760 140.424 ;
    END
  END rd_out[196]
  PIN rd_out[197]
    DIRECTION OUTPUT ;
    USE SIGNAL ;
    SHAPE ABUTMENT ;
    PORT
      LAYER M5 ;
      RECT 20.832 140.400 20.856 140.424 ;
    END
  END rd_out[197]
  PIN rd_out[198]
    DIRECTION OUTPUT ;
    USE SIGNAL ;
    SHAPE ABUTMENT ;
    PORT
      LAYER M5 ;
      RECT 20.928 140.400 20.952 140.424 ;
    END
  END rd_out[198]
  PIN rd_out[199]
    DIRECTION OUTPUT ;
    USE SIGNAL ;
    SHAPE ABUTMENT ;
    PORT
      LAYER M5 ;
      RECT 21.024 140.400 21.048 140.424 ;
    END
  END rd_out[199]
  PIN rd_out[200]
    DIRECTION OUTPUT ;
    USE SIGNAL ;
    SHAPE ABUTMENT ;
    PORT
      LAYER M5 ;
      RECT 21.120 140.400 21.144 140.424 ;
    END
  END rd_out[200]
  PIN rd_out[201]
    DIRECTION OUTPUT ;
    USE SIGNAL ;
    SHAPE ABUTMENT ;
    PORT
      LAYER M5 ;
      RECT 21.216 140.400 21.240 140.424 ;
    END
  END rd_out[201]
  PIN rd_out[202]
    DIRECTION OUTPUT ;
    USE SIGNAL ;
    SHAPE ABUTMENT ;
    PORT
      LAYER M5 ;
      RECT 21.312 140.400 21.336 140.424 ;
    END
  END rd_out[202]
  PIN rd_out[203]
    DIRECTION OUTPUT ;
    USE SIGNAL ;
    SHAPE ABUTMENT ;
    PORT
      LAYER M5 ;
      RECT 21.408 140.400 21.432 140.424 ;
    END
  END rd_out[203]
  PIN rd_out[204]
    DIRECTION OUTPUT ;
    USE SIGNAL ;
    SHAPE ABUTMENT ;
    PORT
      LAYER M5 ;
      RECT 21.504 140.400 21.528 140.424 ;
    END
  END rd_out[204]
  PIN rd_out[205]
    DIRECTION OUTPUT ;
    USE SIGNAL ;
    SHAPE ABUTMENT ;
    PORT
      LAYER M5 ;
      RECT 21.600 140.400 21.624 140.424 ;
    END
  END rd_out[205]
  PIN rd_out[206]
    DIRECTION OUTPUT ;
    USE SIGNAL ;
    SHAPE ABUTMENT ;
    PORT
      LAYER M5 ;
      RECT 21.696 140.400 21.720 140.424 ;
    END
  END rd_out[206]
  PIN rd_out[207]
    DIRECTION OUTPUT ;
    USE SIGNAL ;
    SHAPE ABUTMENT ;
    PORT
      LAYER M5 ;
      RECT 21.792 140.400 21.816 140.424 ;
    END
  END rd_out[207]
  PIN rd_out[208]
    DIRECTION OUTPUT ;
    USE SIGNAL ;
    SHAPE ABUTMENT ;
    PORT
      LAYER M5 ;
      RECT 21.888 140.400 21.912 140.424 ;
    END
  END rd_out[208]
  PIN rd_out[209]
    DIRECTION OUTPUT ;
    USE SIGNAL ;
    SHAPE ABUTMENT ;
    PORT
      LAYER M5 ;
      RECT 21.984 140.400 22.008 140.424 ;
    END
  END rd_out[209]
  PIN rd_out[210]
    DIRECTION OUTPUT ;
    USE SIGNAL ;
    SHAPE ABUTMENT ;
    PORT
      LAYER M5 ;
      RECT 22.080 140.400 22.104 140.424 ;
    END
  END rd_out[210]
  PIN rd_out[211]
    DIRECTION OUTPUT ;
    USE SIGNAL ;
    SHAPE ABUTMENT ;
    PORT
      LAYER M5 ;
      RECT 22.176 140.400 22.200 140.424 ;
    END
  END rd_out[211]
  PIN rd_out[212]
    DIRECTION OUTPUT ;
    USE SIGNAL ;
    SHAPE ABUTMENT ;
    PORT
      LAYER M5 ;
      RECT 22.272 140.400 22.296 140.424 ;
    END
  END rd_out[212]
  PIN rd_out[213]
    DIRECTION OUTPUT ;
    USE SIGNAL ;
    SHAPE ABUTMENT ;
    PORT
      LAYER M5 ;
      RECT 22.368 140.400 22.392 140.424 ;
    END
  END rd_out[213]
  PIN rd_out[214]
    DIRECTION OUTPUT ;
    USE SIGNAL ;
    SHAPE ABUTMENT ;
    PORT
      LAYER M5 ;
      RECT 22.464 140.400 22.488 140.424 ;
    END
  END rd_out[214]
  PIN rd_out[215]
    DIRECTION OUTPUT ;
    USE SIGNAL ;
    SHAPE ABUTMENT ;
    PORT
      LAYER M5 ;
      RECT 22.560 140.400 22.584 140.424 ;
    END
  END rd_out[215]
  PIN rd_out[216]
    DIRECTION OUTPUT ;
    USE SIGNAL ;
    SHAPE ABUTMENT ;
    PORT
      LAYER M5 ;
      RECT 22.656 140.400 22.680 140.424 ;
    END
  END rd_out[216]
  PIN rd_out[217]
    DIRECTION OUTPUT ;
    USE SIGNAL ;
    SHAPE ABUTMENT ;
    PORT
      LAYER M5 ;
      RECT 22.752 140.400 22.776 140.424 ;
    END
  END rd_out[217]
  PIN rd_out[218]
    DIRECTION OUTPUT ;
    USE SIGNAL ;
    SHAPE ABUTMENT ;
    PORT
      LAYER M5 ;
      RECT 22.848 140.400 22.872 140.424 ;
    END
  END rd_out[218]
  PIN rd_out[219]
    DIRECTION OUTPUT ;
    USE SIGNAL ;
    SHAPE ABUTMENT ;
    PORT
      LAYER M5 ;
      RECT 22.944 140.400 22.968 140.424 ;
    END
  END rd_out[219]
  PIN rd_out[220]
    DIRECTION OUTPUT ;
    USE SIGNAL ;
    SHAPE ABUTMENT ;
    PORT
      LAYER M5 ;
      RECT 23.040 140.400 23.064 140.424 ;
    END
  END rd_out[220]
  PIN rd_out[221]
    DIRECTION OUTPUT ;
    USE SIGNAL ;
    SHAPE ABUTMENT ;
    PORT
      LAYER M5 ;
      RECT 23.136 140.400 23.160 140.424 ;
    END
  END rd_out[221]
  PIN rd_out[222]
    DIRECTION OUTPUT ;
    USE SIGNAL ;
    SHAPE ABUTMENT ;
    PORT
      LAYER M5 ;
      RECT 23.232 140.400 23.256 140.424 ;
    END
  END rd_out[222]
  PIN rd_out[223]
    DIRECTION OUTPUT ;
    USE SIGNAL ;
    SHAPE ABUTMENT ;
    PORT
      LAYER M5 ;
      RECT 23.328 140.400 23.352 140.424 ;
    END
  END rd_out[223]
  PIN rd_out[224]
    DIRECTION OUTPUT ;
    USE SIGNAL ;
    SHAPE ABUTMENT ;
    PORT
      LAYER M5 ;
      RECT 23.424 140.400 23.448 140.424 ;
    END
  END rd_out[224]
  PIN rd_out[225]
    DIRECTION OUTPUT ;
    USE SIGNAL ;
    SHAPE ABUTMENT ;
    PORT
      LAYER M5 ;
      RECT 23.520 140.400 23.544 140.424 ;
    END
  END rd_out[225]
  PIN rd_out[226]
    DIRECTION OUTPUT ;
    USE SIGNAL ;
    SHAPE ABUTMENT ;
    PORT
      LAYER M5 ;
      RECT 23.616 140.400 23.640 140.424 ;
    END
  END rd_out[226]
  PIN rd_out[227]
    DIRECTION OUTPUT ;
    USE SIGNAL ;
    SHAPE ABUTMENT ;
    PORT
      LAYER M5 ;
      RECT 23.712 140.400 23.736 140.424 ;
    END
  END rd_out[227]
  PIN rd_out[228]
    DIRECTION OUTPUT ;
    USE SIGNAL ;
    SHAPE ABUTMENT ;
    PORT
      LAYER M5 ;
      RECT 23.808 140.400 23.832 140.424 ;
    END
  END rd_out[228]
  PIN rd_out[229]
    DIRECTION OUTPUT ;
    USE SIGNAL ;
    SHAPE ABUTMENT ;
    PORT
      LAYER M5 ;
      RECT 23.904 140.400 23.928 140.424 ;
    END
  END rd_out[229]
  PIN rd_out[230]
    DIRECTION OUTPUT ;
    USE SIGNAL ;
    SHAPE ABUTMENT ;
    PORT
      LAYER M5 ;
      RECT 24.000 140.400 24.024 140.424 ;
    END
  END rd_out[230]
  PIN rd_out[231]
    DIRECTION OUTPUT ;
    USE SIGNAL ;
    SHAPE ABUTMENT ;
    PORT
      LAYER M5 ;
      RECT 24.096 140.400 24.120 140.424 ;
    END
  END rd_out[231]
  PIN rd_out[232]
    DIRECTION OUTPUT ;
    USE SIGNAL ;
    SHAPE ABUTMENT ;
    PORT
      LAYER M5 ;
      RECT 24.192 140.400 24.216 140.424 ;
    END
  END rd_out[232]
  PIN rd_out[233]
    DIRECTION OUTPUT ;
    USE SIGNAL ;
    SHAPE ABUTMENT ;
    PORT
      LAYER M5 ;
      RECT 24.288 140.400 24.312 140.424 ;
    END
  END rd_out[233]
  PIN rd_out[234]
    DIRECTION OUTPUT ;
    USE SIGNAL ;
    SHAPE ABUTMENT ;
    PORT
      LAYER M5 ;
      RECT 24.384 140.400 24.408 140.424 ;
    END
  END rd_out[234]
  PIN rd_out[235]
    DIRECTION OUTPUT ;
    USE SIGNAL ;
    SHAPE ABUTMENT ;
    PORT
      LAYER M5 ;
      RECT 24.480 140.400 24.504 140.424 ;
    END
  END rd_out[235]
  PIN rd_out[236]
    DIRECTION OUTPUT ;
    USE SIGNAL ;
    SHAPE ABUTMENT ;
    PORT
      LAYER M5 ;
      RECT 24.576 140.400 24.600 140.424 ;
    END
  END rd_out[236]
  PIN rd_out[237]
    DIRECTION OUTPUT ;
    USE SIGNAL ;
    SHAPE ABUTMENT ;
    PORT
      LAYER M5 ;
      RECT 24.672 140.400 24.696 140.424 ;
    END
  END rd_out[237]
  PIN rd_out[238]
    DIRECTION OUTPUT ;
    USE SIGNAL ;
    SHAPE ABUTMENT ;
    PORT
      LAYER M5 ;
      RECT 24.768 140.400 24.792 140.424 ;
    END
  END rd_out[238]
  PIN rd_out[239]
    DIRECTION OUTPUT ;
    USE SIGNAL ;
    SHAPE ABUTMENT ;
    PORT
      LAYER M5 ;
      RECT 24.864 140.400 24.888 140.424 ;
    END
  END rd_out[239]
  PIN rd_out[240]
    DIRECTION OUTPUT ;
    USE SIGNAL ;
    SHAPE ABUTMENT ;
    PORT
      LAYER M5 ;
      RECT 24.960 140.400 24.984 140.424 ;
    END
  END rd_out[240]
  PIN rd_out[241]
    DIRECTION OUTPUT ;
    USE SIGNAL ;
    SHAPE ABUTMENT ;
    PORT
      LAYER M5 ;
      RECT 25.056 140.400 25.080 140.424 ;
    END
  END rd_out[241]
  PIN rd_out[242]
    DIRECTION OUTPUT ;
    USE SIGNAL ;
    SHAPE ABUTMENT ;
    PORT
      LAYER M5 ;
      RECT 25.152 140.400 25.176 140.424 ;
    END
  END rd_out[242]
  PIN rd_out[243]
    DIRECTION OUTPUT ;
    USE SIGNAL ;
    SHAPE ABUTMENT ;
    PORT
      LAYER M5 ;
      RECT 25.248 140.400 25.272 140.424 ;
    END
  END rd_out[243]
  PIN rd_out[244]
    DIRECTION OUTPUT ;
    USE SIGNAL ;
    SHAPE ABUTMENT ;
    PORT
      LAYER M5 ;
      RECT 25.344 140.400 25.368 140.424 ;
    END
  END rd_out[244]
  PIN rd_out[245]
    DIRECTION OUTPUT ;
    USE SIGNAL ;
    SHAPE ABUTMENT ;
    PORT
      LAYER M5 ;
      RECT 25.440 140.400 25.464 140.424 ;
    END
  END rd_out[245]
  PIN rd_out[246]
    DIRECTION OUTPUT ;
    USE SIGNAL ;
    SHAPE ABUTMENT ;
    PORT
      LAYER M5 ;
      RECT 25.536 140.400 25.560 140.424 ;
    END
  END rd_out[246]
  PIN rd_out[247]
    DIRECTION OUTPUT ;
    USE SIGNAL ;
    SHAPE ABUTMENT ;
    PORT
      LAYER M5 ;
      RECT 25.632 140.400 25.656 140.424 ;
    END
  END rd_out[247]
  PIN rd_out[248]
    DIRECTION OUTPUT ;
    USE SIGNAL ;
    SHAPE ABUTMENT ;
    PORT
      LAYER M5 ;
      RECT 25.728 140.400 25.752 140.424 ;
    END
  END rd_out[248]
  PIN rd_out[249]
    DIRECTION OUTPUT ;
    USE SIGNAL ;
    SHAPE ABUTMENT ;
    PORT
      LAYER M5 ;
      RECT 25.824 140.400 25.848 140.424 ;
    END
  END rd_out[249]
  PIN rd_out[250]
    DIRECTION OUTPUT ;
    USE SIGNAL ;
    SHAPE ABUTMENT ;
    PORT
      LAYER M5 ;
      RECT 25.920 140.400 25.944 140.424 ;
    END
  END rd_out[250]
  PIN rd_out[251]
    DIRECTION OUTPUT ;
    USE SIGNAL ;
    SHAPE ABUTMENT ;
    PORT
      LAYER M5 ;
      RECT 26.016 140.400 26.040 140.424 ;
    END
  END rd_out[251]
  PIN rd_out[252]
    DIRECTION OUTPUT ;
    USE SIGNAL ;
    SHAPE ABUTMENT ;
    PORT
      LAYER M5 ;
      RECT 26.112 140.400 26.136 140.424 ;
    END
  END rd_out[252]
  PIN rd_out[253]
    DIRECTION OUTPUT ;
    USE SIGNAL ;
    SHAPE ABUTMENT ;
    PORT
      LAYER M5 ;
      RECT 26.208 140.400 26.232 140.424 ;
    END
  END rd_out[253]
  PIN rd_out[254]
    DIRECTION OUTPUT ;
    USE SIGNAL ;
    SHAPE ABUTMENT ;
    PORT
      LAYER M5 ;
      RECT 26.304 140.400 26.328 140.424 ;
    END
  END rd_out[254]
  PIN rd_out[255]
    DIRECTION OUTPUT ;
    USE SIGNAL ;
    SHAPE ABUTMENT ;
    PORT
      LAYER M5 ;
      RECT 26.400 140.400 26.424 140.424 ;
    END
  END rd_out[255]
  PIN w_ce_in
    DIRECTION INPUT ;
    USE SIGNAL ;
    SHAPE ABUTMENT ;
    PORT
      LAYER M5 ;
      RECT 26.496 140.400 26.520 140.424 ;
    END
  END w_ce_in
  PIN w_addr_in[0]
    DIRECTION INPUT ;
    USE SIGNAL ;
    SHAPE ABUTMENT ;
    PORT
      LAYER M5 ;
      RECT 26.592 140.400 26.616 140.424 ;
    END
  END w_addr_in[0]
  PIN w_addr_in[1]
    DIRECTION INPUT ;
    USE SIGNAL ;
    SHAPE ABUTMENT ;
    PORT
      LAYER M5 ;
      RECT 26.688 140.400 26.712 140.424 ;
    END
  END w_addr_in[1]
  PIN w_addr_in[2]
    DIRECTION INPUT ;
    USE SIGNAL ;
    SHAPE ABUTMENT ;
    PORT
      LAYER M5 ;
      RECT 26.784 140.400 26.808 140.424 ;
    END
  END w_addr_in[2]
  PIN w_addr_in[3]
    DIRECTION INPUT ;
    USE SIGNAL ;
    SHAPE ABUTMENT ;
    PORT
      LAYER M5 ;
      RECT 26.880 140.400 26.904 140.424 ;
    END
  END w_addr_in[3]
  PIN w_addr_in[4]
    DIRECTION INPUT ;
    USE SIGNAL ;
    SHAPE ABUTMENT ;
    PORT
      LAYER M5 ;
      RECT 26.976 140.400 27.000 140.424 ;
    END
  END w_addr_in[4]
  PIN w_addr_in[5]
    DIRECTION INPUT ;
    USE SIGNAL ;
    SHAPE ABUTMENT ;
    PORT
      LAYER M5 ;
      RECT 27.072 140.400 27.096 140.424 ;
    END
  END w_addr_in[5]
  PIN w_addr_in[6]
    DIRECTION INPUT ;
    USE SIGNAL ;
    SHAPE ABUTMENT ;
    PORT
      LAYER M5 ;
      RECT 27.168 140.400 27.192 140.424 ;
    END
  END w_addr_in[6]
  PIN w_addr_in[7]
    DIRECTION INPUT ;
    USE SIGNAL ;
    SHAPE ABUTMENT ;
    PORT
      LAYER M5 ;
      RECT 27.264 140.400 27.288 140.424 ;
    END
  END w_addr_in[7]
  PIN w_addr_in[8]
    DIRECTION INPUT ;
    USE SIGNAL ;
    SHAPE ABUTMENT ;
    PORT
      LAYER M5 ;
      RECT 27.360 140.400 27.384 140.424 ;
    END
  END w_addr_in[8]
  PIN w_addr_in[9]
    DIRECTION INPUT ;
    USE SIGNAL ;
    SHAPE ABUTMENT ;
    PORT
      LAYER M5 ;
      RECT 27.456 140.400 27.480 140.424 ;
    END
  END w_addr_in[9]
  PIN wd_in[0]
    DIRECTION INPUT ;
    USE SIGNAL ;
    SHAPE ABUTMENT ;
    PORT
      LAYER M5 ;
      RECT 27.552 140.400 27.576 140.424 ;
    END
  END wd_in[0]
  PIN wd_in[1]
    DIRECTION INPUT ;
    USE SIGNAL ;
    SHAPE ABUTMENT ;
    PORT
      LAYER M5 ;
      RECT 27.648 140.400 27.672 140.424 ;
    END
  END wd_in[1]
  PIN wd_in[2]
    DIRECTION INPUT ;
    USE SIGNAL ;
    SHAPE ABUTMENT ;
    PORT
      LAYER M5 ;
      RECT 27.744 140.400 27.768 140.424 ;
    END
  END wd_in[2]
  PIN wd_in[3]
    DIRECTION INPUT ;
    USE SIGNAL ;
    SHAPE ABUTMENT ;
    PORT
      LAYER M5 ;
      RECT 27.840 140.400 27.864 140.424 ;
    END
  END wd_in[3]
  PIN wd_in[4]
    DIRECTION INPUT ;
    USE SIGNAL ;
    SHAPE ABUTMENT ;
    PORT
      LAYER M5 ;
      RECT 27.936 140.400 27.960 140.424 ;
    END
  END wd_in[4]
  PIN wd_in[5]
    DIRECTION INPUT ;
    USE SIGNAL ;
    SHAPE ABUTMENT ;
    PORT
      LAYER M5 ;
      RECT 28.032 140.400 28.056 140.424 ;
    END
  END wd_in[5]
  PIN wd_in[6]
    DIRECTION INPUT ;
    USE SIGNAL ;
    SHAPE ABUTMENT ;
    PORT
      LAYER M5 ;
      RECT 28.128 140.400 28.152 140.424 ;
    END
  END wd_in[6]
  PIN wd_in[7]
    DIRECTION INPUT ;
    USE SIGNAL ;
    SHAPE ABUTMENT ;
    PORT
      LAYER M5 ;
      RECT 28.224 140.400 28.248 140.424 ;
    END
  END wd_in[7]
  PIN wd_in[8]
    DIRECTION INPUT ;
    USE SIGNAL ;
    SHAPE ABUTMENT ;
    PORT
      LAYER M5 ;
      RECT 28.320 140.400 28.344 140.424 ;
    END
  END wd_in[8]
  PIN wd_in[9]
    DIRECTION INPUT ;
    USE SIGNAL ;
    SHAPE ABUTMENT ;
    PORT
      LAYER M5 ;
      RECT 28.416 140.400 28.440 140.424 ;
    END
  END wd_in[9]
  PIN wd_in[10]
    DIRECTION INPUT ;
    USE SIGNAL ;
    SHAPE ABUTMENT ;
    PORT
      LAYER M5 ;
      RECT 28.512 140.400 28.536 140.424 ;
    END
  END wd_in[10]
  PIN wd_in[11]
    DIRECTION INPUT ;
    USE SIGNAL ;
    SHAPE ABUTMENT ;
    PORT
      LAYER M5 ;
      RECT 28.608 140.400 28.632 140.424 ;
    END
  END wd_in[11]
  PIN wd_in[12]
    DIRECTION INPUT ;
    USE SIGNAL ;
    SHAPE ABUTMENT ;
    PORT
      LAYER M5 ;
      RECT 28.704 140.400 28.728 140.424 ;
    END
  END wd_in[12]
  PIN wd_in[13]
    DIRECTION INPUT ;
    USE SIGNAL ;
    SHAPE ABUTMENT ;
    PORT
      LAYER M5 ;
      RECT 28.800 140.400 28.824 140.424 ;
    END
  END wd_in[13]
  PIN wd_in[14]
    DIRECTION INPUT ;
    USE SIGNAL ;
    SHAPE ABUTMENT ;
    PORT
      LAYER M5 ;
      RECT 28.896 140.400 28.920 140.424 ;
    END
  END wd_in[14]
  PIN wd_in[15]
    DIRECTION INPUT ;
    USE SIGNAL ;
    SHAPE ABUTMENT ;
    PORT
      LAYER M5 ;
      RECT 28.992 140.400 29.016 140.424 ;
    END
  END wd_in[15]
  PIN wd_in[16]
    DIRECTION INPUT ;
    USE SIGNAL ;
    SHAPE ABUTMENT ;
    PORT
      LAYER M5 ;
      RECT 29.088 140.400 29.112 140.424 ;
    END
  END wd_in[16]
  PIN wd_in[17]
    DIRECTION INPUT ;
    USE SIGNAL ;
    SHAPE ABUTMENT ;
    PORT
      LAYER M5 ;
      RECT 29.184 140.400 29.208 140.424 ;
    END
  END wd_in[17]
  PIN wd_in[18]
    DIRECTION INPUT ;
    USE SIGNAL ;
    SHAPE ABUTMENT ;
    PORT
      LAYER M5 ;
      RECT 29.280 140.400 29.304 140.424 ;
    END
  END wd_in[18]
  PIN wd_in[19]
    DIRECTION INPUT ;
    USE SIGNAL ;
    SHAPE ABUTMENT ;
    PORT
      LAYER M5 ;
      RECT 29.376 140.400 29.400 140.424 ;
    END
  END wd_in[19]
  PIN wd_in[20]
    DIRECTION INPUT ;
    USE SIGNAL ;
    SHAPE ABUTMENT ;
    PORT
      LAYER M5 ;
      RECT 29.472 140.400 29.496 140.424 ;
    END
  END wd_in[20]
  PIN wd_in[21]
    DIRECTION INPUT ;
    USE SIGNAL ;
    SHAPE ABUTMENT ;
    PORT
      LAYER M5 ;
      RECT 29.568 140.400 29.592 140.424 ;
    END
  END wd_in[21]
  PIN wd_in[22]
    DIRECTION INPUT ;
    USE SIGNAL ;
    SHAPE ABUTMENT ;
    PORT
      LAYER M5 ;
      RECT 29.664 140.400 29.688 140.424 ;
    END
  END wd_in[22]
  PIN wd_in[23]
    DIRECTION INPUT ;
    USE SIGNAL ;
    SHAPE ABUTMENT ;
    PORT
      LAYER M5 ;
      RECT 29.760 140.400 29.784 140.424 ;
    END
  END wd_in[23]
  PIN wd_in[24]
    DIRECTION INPUT ;
    USE SIGNAL ;
    SHAPE ABUTMENT ;
    PORT
      LAYER M5 ;
      RECT 29.856 140.400 29.880 140.424 ;
    END
  END wd_in[24]
  PIN wd_in[25]
    DIRECTION INPUT ;
    USE SIGNAL ;
    SHAPE ABUTMENT ;
    PORT
      LAYER M5 ;
      RECT 29.952 140.400 29.976 140.424 ;
    END
  END wd_in[25]
  PIN wd_in[26]
    DIRECTION INPUT ;
    USE SIGNAL ;
    SHAPE ABUTMENT ;
    PORT
      LAYER M5 ;
      RECT 30.048 140.400 30.072 140.424 ;
    END
  END wd_in[26]
  PIN wd_in[27]
    DIRECTION INPUT ;
    USE SIGNAL ;
    SHAPE ABUTMENT ;
    PORT
      LAYER M5 ;
      RECT 30.144 140.400 30.168 140.424 ;
    END
  END wd_in[27]
  PIN wd_in[28]
    DIRECTION INPUT ;
    USE SIGNAL ;
    SHAPE ABUTMENT ;
    PORT
      LAYER M5 ;
      RECT 30.240 140.400 30.264 140.424 ;
    END
  END wd_in[28]
  PIN wd_in[29]
    DIRECTION INPUT ;
    USE SIGNAL ;
    SHAPE ABUTMENT ;
    PORT
      LAYER M5 ;
      RECT 30.336 140.400 30.360 140.424 ;
    END
  END wd_in[29]
  PIN wd_in[30]
    DIRECTION INPUT ;
    USE SIGNAL ;
    SHAPE ABUTMENT ;
    PORT
      LAYER M5 ;
      RECT 30.432 140.400 30.456 140.424 ;
    END
  END wd_in[30]
  PIN wd_in[31]
    DIRECTION INPUT ;
    USE SIGNAL ;
    SHAPE ABUTMENT ;
    PORT
      LAYER M5 ;
      RECT 30.528 140.400 30.552 140.424 ;
    END
  END wd_in[31]
  PIN wd_in[32]
    DIRECTION INPUT ;
    USE SIGNAL ;
    SHAPE ABUTMENT ;
    PORT
      LAYER M5 ;
      RECT 30.624 140.400 30.648 140.424 ;
    END
  END wd_in[32]
  PIN wd_in[33]
    DIRECTION INPUT ;
    USE SIGNAL ;
    SHAPE ABUTMENT ;
    PORT
      LAYER M5 ;
      RECT 30.720 140.400 30.744 140.424 ;
    END
  END wd_in[33]
  PIN wd_in[34]
    DIRECTION INPUT ;
    USE SIGNAL ;
    SHAPE ABUTMENT ;
    PORT
      LAYER M5 ;
      RECT 30.816 140.400 30.840 140.424 ;
    END
  END wd_in[34]
  PIN wd_in[35]
    DIRECTION INPUT ;
    USE SIGNAL ;
    SHAPE ABUTMENT ;
    PORT
      LAYER M5 ;
      RECT 30.912 140.400 30.936 140.424 ;
    END
  END wd_in[35]
  PIN wd_in[36]
    DIRECTION INPUT ;
    USE SIGNAL ;
    SHAPE ABUTMENT ;
    PORT
      LAYER M5 ;
      RECT 31.008 140.400 31.032 140.424 ;
    END
  END wd_in[36]
  PIN wd_in[37]
    DIRECTION INPUT ;
    USE SIGNAL ;
    SHAPE ABUTMENT ;
    PORT
      LAYER M5 ;
      RECT 31.104 140.400 31.128 140.424 ;
    END
  END wd_in[37]
  PIN wd_in[38]
    DIRECTION INPUT ;
    USE SIGNAL ;
    SHAPE ABUTMENT ;
    PORT
      LAYER M5 ;
      RECT 31.200 140.400 31.224 140.424 ;
    END
  END wd_in[38]
  PIN wd_in[39]
    DIRECTION INPUT ;
    USE SIGNAL ;
    SHAPE ABUTMENT ;
    PORT
      LAYER M5 ;
      RECT 31.296 140.400 31.320 140.424 ;
    END
  END wd_in[39]
  PIN wd_in[40]
    DIRECTION INPUT ;
    USE SIGNAL ;
    SHAPE ABUTMENT ;
    PORT
      LAYER M5 ;
      RECT 31.392 140.400 31.416 140.424 ;
    END
  END wd_in[40]
  PIN wd_in[41]
    DIRECTION INPUT ;
    USE SIGNAL ;
    SHAPE ABUTMENT ;
    PORT
      LAYER M5 ;
      RECT 31.488 140.400 31.512 140.424 ;
    END
  END wd_in[41]
  PIN wd_in[42]
    DIRECTION INPUT ;
    USE SIGNAL ;
    SHAPE ABUTMENT ;
    PORT
      LAYER M5 ;
      RECT 31.584 140.400 31.608 140.424 ;
    END
  END wd_in[42]
  PIN wd_in[43]
    DIRECTION INPUT ;
    USE SIGNAL ;
    SHAPE ABUTMENT ;
    PORT
      LAYER M5 ;
      RECT 31.680 140.400 31.704 140.424 ;
    END
  END wd_in[43]
  PIN wd_in[44]
    DIRECTION INPUT ;
    USE SIGNAL ;
    SHAPE ABUTMENT ;
    PORT
      LAYER M5 ;
      RECT 31.776 140.400 31.800 140.424 ;
    END
  END wd_in[44]
  PIN wd_in[45]
    DIRECTION INPUT ;
    USE SIGNAL ;
    SHAPE ABUTMENT ;
    PORT
      LAYER M5 ;
      RECT 31.872 140.400 31.896 140.424 ;
    END
  END wd_in[45]
  PIN wd_in[46]
    DIRECTION INPUT ;
    USE SIGNAL ;
    SHAPE ABUTMENT ;
    PORT
      LAYER M5 ;
      RECT 31.968 140.400 31.992 140.424 ;
    END
  END wd_in[46]
  PIN wd_in[47]
    DIRECTION INPUT ;
    USE SIGNAL ;
    SHAPE ABUTMENT ;
    PORT
      LAYER M5 ;
      RECT 32.064 140.400 32.088 140.424 ;
    END
  END wd_in[47]
  PIN wd_in[48]
    DIRECTION INPUT ;
    USE SIGNAL ;
    SHAPE ABUTMENT ;
    PORT
      LAYER M5 ;
      RECT 32.160 140.400 32.184 140.424 ;
    END
  END wd_in[48]
  PIN wd_in[49]
    DIRECTION INPUT ;
    USE SIGNAL ;
    SHAPE ABUTMENT ;
    PORT
      LAYER M5 ;
      RECT 32.256 140.400 32.280 140.424 ;
    END
  END wd_in[49]
  PIN wd_in[50]
    DIRECTION INPUT ;
    USE SIGNAL ;
    SHAPE ABUTMENT ;
    PORT
      LAYER M5 ;
      RECT 32.352 140.400 32.376 140.424 ;
    END
  END wd_in[50]
  PIN wd_in[51]
    DIRECTION INPUT ;
    USE SIGNAL ;
    SHAPE ABUTMENT ;
    PORT
      LAYER M5 ;
      RECT 32.448 140.400 32.472 140.424 ;
    END
  END wd_in[51]
  PIN wd_in[52]
    DIRECTION INPUT ;
    USE SIGNAL ;
    SHAPE ABUTMENT ;
    PORT
      LAYER M5 ;
      RECT 32.544 140.400 32.568 140.424 ;
    END
  END wd_in[52]
  PIN wd_in[53]
    DIRECTION INPUT ;
    USE SIGNAL ;
    SHAPE ABUTMENT ;
    PORT
      LAYER M5 ;
      RECT 32.640 140.400 32.664 140.424 ;
    END
  END wd_in[53]
  PIN wd_in[54]
    DIRECTION INPUT ;
    USE SIGNAL ;
    SHAPE ABUTMENT ;
    PORT
      LAYER M5 ;
      RECT 32.736 140.400 32.760 140.424 ;
    END
  END wd_in[54]
  PIN wd_in[55]
    DIRECTION INPUT ;
    USE SIGNAL ;
    SHAPE ABUTMENT ;
    PORT
      LAYER M5 ;
      RECT 32.832 140.400 32.856 140.424 ;
    END
  END wd_in[55]
  PIN wd_in[56]
    DIRECTION INPUT ;
    USE SIGNAL ;
    SHAPE ABUTMENT ;
    PORT
      LAYER M5 ;
      RECT 32.928 140.400 32.952 140.424 ;
    END
  END wd_in[56]
  PIN wd_in[57]
    DIRECTION INPUT ;
    USE SIGNAL ;
    SHAPE ABUTMENT ;
    PORT
      LAYER M5 ;
      RECT 33.024 140.400 33.048 140.424 ;
    END
  END wd_in[57]
  PIN wd_in[58]
    DIRECTION INPUT ;
    USE SIGNAL ;
    SHAPE ABUTMENT ;
    PORT
      LAYER M5 ;
      RECT 33.120 140.400 33.144 140.424 ;
    END
  END wd_in[58]
  PIN wd_in[59]
    DIRECTION INPUT ;
    USE SIGNAL ;
    SHAPE ABUTMENT ;
    PORT
      LAYER M5 ;
      RECT 33.216 140.400 33.240 140.424 ;
    END
  END wd_in[59]
  PIN wd_in[60]
    DIRECTION INPUT ;
    USE SIGNAL ;
    SHAPE ABUTMENT ;
    PORT
      LAYER M5 ;
      RECT 33.312 140.400 33.336 140.424 ;
    END
  END wd_in[60]
  PIN wd_in[61]
    DIRECTION INPUT ;
    USE SIGNAL ;
    SHAPE ABUTMENT ;
    PORT
      LAYER M5 ;
      RECT 33.408 140.400 33.432 140.424 ;
    END
  END wd_in[61]
  PIN wd_in[62]
    DIRECTION INPUT ;
    USE SIGNAL ;
    SHAPE ABUTMENT ;
    PORT
      LAYER M5 ;
      RECT 33.504 140.400 33.528 140.424 ;
    END
  END wd_in[62]
  PIN wd_in[63]
    DIRECTION INPUT ;
    USE SIGNAL ;
    SHAPE ABUTMENT ;
    PORT
      LAYER M5 ;
      RECT 33.600 140.400 33.624 140.424 ;
    END
  END wd_in[63]
  PIN wd_in[64]
    DIRECTION INPUT ;
    USE SIGNAL ;
    SHAPE ABUTMENT ;
    PORT
      LAYER M5 ;
      RECT 33.696 140.400 33.720 140.424 ;
    END
  END wd_in[64]
  PIN wd_in[65]
    DIRECTION INPUT ;
    USE SIGNAL ;
    SHAPE ABUTMENT ;
    PORT
      LAYER M5 ;
      RECT 33.792 140.400 33.816 140.424 ;
    END
  END wd_in[65]
  PIN wd_in[66]
    DIRECTION INPUT ;
    USE SIGNAL ;
    SHAPE ABUTMENT ;
    PORT
      LAYER M5 ;
      RECT 33.888 140.400 33.912 140.424 ;
    END
  END wd_in[66]
  PIN wd_in[67]
    DIRECTION INPUT ;
    USE SIGNAL ;
    SHAPE ABUTMENT ;
    PORT
      LAYER M5 ;
      RECT 33.984 140.400 34.008 140.424 ;
    END
  END wd_in[67]
  PIN wd_in[68]
    DIRECTION INPUT ;
    USE SIGNAL ;
    SHAPE ABUTMENT ;
    PORT
      LAYER M5 ;
      RECT 34.080 140.400 34.104 140.424 ;
    END
  END wd_in[68]
  PIN wd_in[69]
    DIRECTION INPUT ;
    USE SIGNAL ;
    SHAPE ABUTMENT ;
    PORT
      LAYER M5 ;
      RECT 34.176 140.400 34.200 140.424 ;
    END
  END wd_in[69]
  PIN wd_in[70]
    DIRECTION INPUT ;
    USE SIGNAL ;
    SHAPE ABUTMENT ;
    PORT
      LAYER M5 ;
      RECT 34.272 140.400 34.296 140.424 ;
    END
  END wd_in[70]
  PIN wd_in[71]
    DIRECTION INPUT ;
    USE SIGNAL ;
    SHAPE ABUTMENT ;
    PORT
      LAYER M5 ;
      RECT 34.368 140.400 34.392 140.424 ;
    END
  END wd_in[71]
  PIN wd_in[72]
    DIRECTION INPUT ;
    USE SIGNAL ;
    SHAPE ABUTMENT ;
    PORT
      LAYER M5 ;
      RECT 34.464 140.400 34.488 140.424 ;
    END
  END wd_in[72]
  PIN wd_in[73]
    DIRECTION INPUT ;
    USE SIGNAL ;
    SHAPE ABUTMENT ;
    PORT
      LAYER M5 ;
      RECT 34.560 140.400 34.584 140.424 ;
    END
  END wd_in[73]
  PIN wd_in[74]
    DIRECTION INPUT ;
    USE SIGNAL ;
    SHAPE ABUTMENT ;
    PORT
      LAYER M5 ;
      RECT 34.656 140.400 34.680 140.424 ;
    END
  END wd_in[74]
  PIN wd_in[75]
    DIRECTION INPUT ;
    USE SIGNAL ;
    SHAPE ABUTMENT ;
    PORT
      LAYER M5 ;
      RECT 34.752 140.400 34.776 140.424 ;
    END
  END wd_in[75]
  PIN wd_in[76]
    DIRECTION INPUT ;
    USE SIGNAL ;
    SHAPE ABUTMENT ;
    PORT
      LAYER M5 ;
      RECT 34.848 140.400 34.872 140.424 ;
    END
  END wd_in[76]
  PIN wd_in[77]
    DIRECTION INPUT ;
    USE SIGNAL ;
    SHAPE ABUTMENT ;
    PORT
      LAYER M5 ;
      RECT 34.944 140.400 34.968 140.424 ;
    END
  END wd_in[77]
  PIN wd_in[78]
    DIRECTION INPUT ;
    USE SIGNAL ;
    SHAPE ABUTMENT ;
    PORT
      LAYER M5 ;
      RECT 35.040 140.400 35.064 140.424 ;
    END
  END wd_in[78]
  PIN wd_in[79]
    DIRECTION INPUT ;
    USE SIGNAL ;
    SHAPE ABUTMENT ;
    PORT
      LAYER M5 ;
      RECT 35.136 140.400 35.160 140.424 ;
    END
  END wd_in[79]
  PIN wd_in[80]
    DIRECTION INPUT ;
    USE SIGNAL ;
    SHAPE ABUTMENT ;
    PORT
      LAYER M5 ;
      RECT 35.232 140.400 35.256 140.424 ;
    END
  END wd_in[80]
  PIN wd_in[81]
    DIRECTION INPUT ;
    USE SIGNAL ;
    SHAPE ABUTMENT ;
    PORT
      LAYER M5 ;
      RECT 35.328 140.400 35.352 140.424 ;
    END
  END wd_in[81]
  PIN wd_in[82]
    DIRECTION INPUT ;
    USE SIGNAL ;
    SHAPE ABUTMENT ;
    PORT
      LAYER M5 ;
      RECT 35.424 140.400 35.448 140.424 ;
    END
  END wd_in[82]
  PIN wd_in[83]
    DIRECTION INPUT ;
    USE SIGNAL ;
    SHAPE ABUTMENT ;
    PORT
      LAYER M5 ;
      RECT 35.520 140.400 35.544 140.424 ;
    END
  END wd_in[83]
  PIN wd_in[84]
    DIRECTION INPUT ;
    USE SIGNAL ;
    SHAPE ABUTMENT ;
    PORT
      LAYER M5 ;
      RECT 35.616 140.400 35.640 140.424 ;
    END
  END wd_in[84]
  PIN wd_in[85]
    DIRECTION INPUT ;
    USE SIGNAL ;
    SHAPE ABUTMENT ;
    PORT
      LAYER M5 ;
      RECT 35.712 140.400 35.736 140.424 ;
    END
  END wd_in[85]
  PIN wd_in[86]
    DIRECTION INPUT ;
    USE SIGNAL ;
    SHAPE ABUTMENT ;
    PORT
      LAYER M5 ;
      RECT 35.808 140.400 35.832 140.424 ;
    END
  END wd_in[86]
  PIN wd_in[87]
    DIRECTION INPUT ;
    USE SIGNAL ;
    SHAPE ABUTMENT ;
    PORT
      LAYER M5 ;
      RECT 35.904 140.400 35.928 140.424 ;
    END
  END wd_in[87]
  PIN wd_in[88]
    DIRECTION INPUT ;
    USE SIGNAL ;
    SHAPE ABUTMENT ;
    PORT
      LAYER M5 ;
      RECT 36.000 140.400 36.024 140.424 ;
    END
  END wd_in[88]
  PIN wd_in[89]
    DIRECTION INPUT ;
    USE SIGNAL ;
    SHAPE ABUTMENT ;
    PORT
      LAYER M5 ;
      RECT 36.096 140.400 36.120 140.424 ;
    END
  END wd_in[89]
  PIN wd_in[90]
    DIRECTION INPUT ;
    USE SIGNAL ;
    SHAPE ABUTMENT ;
    PORT
      LAYER M5 ;
      RECT 36.192 140.400 36.216 140.424 ;
    END
  END wd_in[90]
  PIN wd_in[91]
    DIRECTION INPUT ;
    USE SIGNAL ;
    SHAPE ABUTMENT ;
    PORT
      LAYER M5 ;
      RECT 36.288 140.400 36.312 140.424 ;
    END
  END wd_in[91]
  PIN wd_in[92]
    DIRECTION INPUT ;
    USE SIGNAL ;
    SHAPE ABUTMENT ;
    PORT
      LAYER M5 ;
      RECT 36.384 140.400 36.408 140.424 ;
    END
  END wd_in[92]
  PIN wd_in[93]
    DIRECTION INPUT ;
    USE SIGNAL ;
    SHAPE ABUTMENT ;
    PORT
      LAYER M5 ;
      RECT 36.480 140.400 36.504 140.424 ;
    END
  END wd_in[93]
  PIN wd_in[94]
    DIRECTION INPUT ;
    USE SIGNAL ;
    SHAPE ABUTMENT ;
    PORT
      LAYER M5 ;
      RECT 36.576 140.400 36.600 140.424 ;
    END
  END wd_in[94]
  PIN wd_in[95]
    DIRECTION INPUT ;
    USE SIGNAL ;
    SHAPE ABUTMENT ;
    PORT
      LAYER M5 ;
      RECT 36.672 140.400 36.696 140.424 ;
    END
  END wd_in[95]
  PIN wd_in[96]
    DIRECTION INPUT ;
    USE SIGNAL ;
    SHAPE ABUTMENT ;
    PORT
      LAYER M5 ;
      RECT 36.768 140.400 36.792 140.424 ;
    END
  END wd_in[96]
  PIN wd_in[97]
    DIRECTION INPUT ;
    USE SIGNAL ;
    SHAPE ABUTMENT ;
    PORT
      LAYER M5 ;
      RECT 36.864 140.400 36.888 140.424 ;
    END
  END wd_in[97]
  PIN wd_in[98]
    DIRECTION INPUT ;
    USE SIGNAL ;
    SHAPE ABUTMENT ;
    PORT
      LAYER M5 ;
      RECT 36.960 140.400 36.984 140.424 ;
    END
  END wd_in[98]
  PIN wd_in[99]
    DIRECTION INPUT ;
    USE SIGNAL ;
    SHAPE ABUTMENT ;
    PORT
      LAYER M5 ;
      RECT 37.056 140.400 37.080 140.424 ;
    END
  END wd_in[99]
  PIN wd_in[100]
    DIRECTION INPUT ;
    USE SIGNAL ;
    SHAPE ABUTMENT ;
    PORT
      LAYER M5 ;
      RECT 37.152 140.400 37.176 140.424 ;
    END
  END wd_in[100]
  PIN wd_in[101]
    DIRECTION INPUT ;
    USE SIGNAL ;
    SHAPE ABUTMENT ;
    PORT
      LAYER M5 ;
      RECT 37.248 140.400 37.272 140.424 ;
    END
  END wd_in[101]
  PIN wd_in[102]
    DIRECTION INPUT ;
    USE SIGNAL ;
    SHAPE ABUTMENT ;
    PORT
      LAYER M5 ;
      RECT 37.344 140.400 37.368 140.424 ;
    END
  END wd_in[102]
  PIN wd_in[103]
    DIRECTION INPUT ;
    USE SIGNAL ;
    SHAPE ABUTMENT ;
    PORT
      LAYER M5 ;
      RECT 37.440 140.400 37.464 140.424 ;
    END
  END wd_in[103]
  PIN wd_in[104]
    DIRECTION INPUT ;
    USE SIGNAL ;
    SHAPE ABUTMENT ;
    PORT
      LAYER M5 ;
      RECT 37.536 140.400 37.560 140.424 ;
    END
  END wd_in[104]
  PIN wd_in[105]
    DIRECTION INPUT ;
    USE SIGNAL ;
    SHAPE ABUTMENT ;
    PORT
      LAYER M5 ;
      RECT 37.632 140.400 37.656 140.424 ;
    END
  END wd_in[105]
  PIN wd_in[106]
    DIRECTION INPUT ;
    USE SIGNAL ;
    SHAPE ABUTMENT ;
    PORT
      LAYER M5 ;
      RECT 37.728 140.400 37.752 140.424 ;
    END
  END wd_in[106]
  PIN wd_in[107]
    DIRECTION INPUT ;
    USE SIGNAL ;
    SHAPE ABUTMENT ;
    PORT
      LAYER M5 ;
      RECT 37.824 140.400 37.848 140.424 ;
    END
  END wd_in[107]
  PIN wd_in[108]
    DIRECTION INPUT ;
    USE SIGNAL ;
    SHAPE ABUTMENT ;
    PORT
      LAYER M5 ;
      RECT 37.920 140.400 37.944 140.424 ;
    END
  END wd_in[108]
  PIN wd_in[109]
    DIRECTION INPUT ;
    USE SIGNAL ;
    SHAPE ABUTMENT ;
    PORT
      LAYER M5 ;
      RECT 38.016 140.400 38.040 140.424 ;
    END
  END wd_in[109]
  PIN wd_in[110]
    DIRECTION INPUT ;
    USE SIGNAL ;
    SHAPE ABUTMENT ;
    PORT
      LAYER M5 ;
      RECT 38.112 140.400 38.136 140.424 ;
    END
  END wd_in[110]
  PIN wd_in[111]
    DIRECTION INPUT ;
    USE SIGNAL ;
    SHAPE ABUTMENT ;
    PORT
      LAYER M5 ;
      RECT 38.208 140.400 38.232 140.424 ;
    END
  END wd_in[111]
  PIN wd_in[112]
    DIRECTION INPUT ;
    USE SIGNAL ;
    SHAPE ABUTMENT ;
    PORT
      LAYER M5 ;
      RECT 38.304 140.400 38.328 140.424 ;
    END
  END wd_in[112]
  PIN wd_in[113]
    DIRECTION INPUT ;
    USE SIGNAL ;
    SHAPE ABUTMENT ;
    PORT
      LAYER M5 ;
      RECT 38.400 140.400 38.424 140.424 ;
    END
  END wd_in[113]
  PIN wd_in[114]
    DIRECTION INPUT ;
    USE SIGNAL ;
    SHAPE ABUTMENT ;
    PORT
      LAYER M5 ;
      RECT 38.496 140.400 38.520 140.424 ;
    END
  END wd_in[114]
  PIN wd_in[115]
    DIRECTION INPUT ;
    USE SIGNAL ;
    SHAPE ABUTMENT ;
    PORT
      LAYER M5 ;
      RECT 38.592 140.400 38.616 140.424 ;
    END
  END wd_in[115]
  PIN wd_in[116]
    DIRECTION INPUT ;
    USE SIGNAL ;
    SHAPE ABUTMENT ;
    PORT
      LAYER M5 ;
      RECT 38.688 140.400 38.712 140.424 ;
    END
  END wd_in[116]
  PIN wd_in[117]
    DIRECTION INPUT ;
    USE SIGNAL ;
    SHAPE ABUTMENT ;
    PORT
      LAYER M5 ;
      RECT 38.784 140.400 38.808 140.424 ;
    END
  END wd_in[117]
  PIN wd_in[118]
    DIRECTION INPUT ;
    USE SIGNAL ;
    SHAPE ABUTMENT ;
    PORT
      LAYER M5 ;
      RECT 38.880 140.400 38.904 140.424 ;
    END
  END wd_in[118]
  PIN wd_in[119]
    DIRECTION INPUT ;
    USE SIGNAL ;
    SHAPE ABUTMENT ;
    PORT
      LAYER M5 ;
      RECT 38.976 140.400 39.000 140.424 ;
    END
  END wd_in[119]
  PIN wd_in[120]
    DIRECTION INPUT ;
    USE SIGNAL ;
    SHAPE ABUTMENT ;
    PORT
      LAYER M5 ;
      RECT 39.072 140.400 39.096 140.424 ;
    END
  END wd_in[120]
  PIN wd_in[121]
    DIRECTION INPUT ;
    USE SIGNAL ;
    SHAPE ABUTMENT ;
    PORT
      LAYER M5 ;
      RECT 39.168 140.400 39.192 140.424 ;
    END
  END wd_in[121]
  PIN wd_in[122]
    DIRECTION INPUT ;
    USE SIGNAL ;
    SHAPE ABUTMENT ;
    PORT
      LAYER M5 ;
      RECT 39.264 140.400 39.288 140.424 ;
    END
  END wd_in[122]
  PIN wd_in[123]
    DIRECTION INPUT ;
    USE SIGNAL ;
    SHAPE ABUTMENT ;
    PORT
      LAYER M5 ;
      RECT 39.360 140.400 39.384 140.424 ;
    END
  END wd_in[123]
  PIN wd_in[124]
    DIRECTION INPUT ;
    USE SIGNAL ;
    SHAPE ABUTMENT ;
    PORT
      LAYER M5 ;
      RECT 39.456 140.400 39.480 140.424 ;
    END
  END wd_in[124]
  PIN wd_in[125]
    DIRECTION INPUT ;
    USE SIGNAL ;
    SHAPE ABUTMENT ;
    PORT
      LAYER M5 ;
      RECT 39.552 140.400 39.576 140.424 ;
    END
  END wd_in[125]
  PIN wd_in[126]
    DIRECTION INPUT ;
    USE SIGNAL ;
    SHAPE ABUTMENT ;
    PORT
      LAYER M5 ;
      RECT 39.648 140.400 39.672 140.424 ;
    END
  END wd_in[126]
  PIN wd_in[127]
    DIRECTION INPUT ;
    USE SIGNAL ;
    SHAPE ABUTMENT ;
    PORT
      LAYER M5 ;
      RECT 39.744 140.400 39.768 140.424 ;
    END
  END wd_in[127]
  PIN wd_in[128]
    DIRECTION INPUT ;
    USE SIGNAL ;
    SHAPE ABUTMENT ;
    PORT
      LAYER M5 ;
      RECT 39.840 140.400 39.864 140.424 ;
    END
  END wd_in[128]
  PIN wd_in[129]
    DIRECTION INPUT ;
    USE SIGNAL ;
    SHAPE ABUTMENT ;
    PORT
      LAYER M5 ;
      RECT 39.936 140.400 39.960 140.424 ;
    END
  END wd_in[129]
  PIN wd_in[130]
    DIRECTION INPUT ;
    USE SIGNAL ;
    SHAPE ABUTMENT ;
    PORT
      LAYER M5 ;
      RECT 40.032 140.400 40.056 140.424 ;
    END
  END wd_in[130]
  PIN wd_in[131]
    DIRECTION INPUT ;
    USE SIGNAL ;
    SHAPE ABUTMENT ;
    PORT
      LAYER M5 ;
      RECT 40.128 140.400 40.152 140.424 ;
    END
  END wd_in[131]
  PIN wd_in[132]
    DIRECTION INPUT ;
    USE SIGNAL ;
    SHAPE ABUTMENT ;
    PORT
      LAYER M5 ;
      RECT 40.224 140.400 40.248 140.424 ;
    END
  END wd_in[132]
  PIN wd_in[133]
    DIRECTION INPUT ;
    USE SIGNAL ;
    SHAPE ABUTMENT ;
    PORT
      LAYER M5 ;
      RECT 40.320 140.400 40.344 140.424 ;
    END
  END wd_in[133]
  PIN wd_in[134]
    DIRECTION INPUT ;
    USE SIGNAL ;
    SHAPE ABUTMENT ;
    PORT
      LAYER M5 ;
      RECT 40.416 140.400 40.440 140.424 ;
    END
  END wd_in[134]
  PIN wd_in[135]
    DIRECTION INPUT ;
    USE SIGNAL ;
    SHAPE ABUTMENT ;
    PORT
      LAYER M5 ;
      RECT 40.512 140.400 40.536 140.424 ;
    END
  END wd_in[135]
  PIN wd_in[136]
    DIRECTION INPUT ;
    USE SIGNAL ;
    SHAPE ABUTMENT ;
    PORT
      LAYER M5 ;
      RECT 40.608 140.400 40.632 140.424 ;
    END
  END wd_in[136]
  PIN wd_in[137]
    DIRECTION INPUT ;
    USE SIGNAL ;
    SHAPE ABUTMENT ;
    PORT
      LAYER M5 ;
      RECT 0.768 0.000 0.792 0.024 ;
    END
  END wd_in[137]
  PIN wd_in[138]
    DIRECTION INPUT ;
    USE SIGNAL ;
    SHAPE ABUTMENT ;
    PORT
      LAYER M5 ;
      RECT 0.864 0.000 0.888 0.024 ;
    END
  END wd_in[138]
  PIN wd_in[139]
    DIRECTION INPUT ;
    USE SIGNAL ;
    SHAPE ABUTMENT ;
    PORT
      LAYER M5 ;
      RECT 0.960 0.000 0.984 0.024 ;
    END
  END wd_in[139]
  PIN wd_in[140]
    DIRECTION INPUT ;
    USE SIGNAL ;
    SHAPE ABUTMENT ;
    PORT
      LAYER M5 ;
      RECT 1.056 0.000 1.080 0.024 ;
    END
  END wd_in[140]
  PIN wd_in[141]
    DIRECTION INPUT ;
    USE SIGNAL ;
    SHAPE ABUTMENT ;
    PORT
      LAYER M5 ;
      RECT 1.152 0.000 1.176 0.024 ;
    END
  END wd_in[141]
  PIN wd_in[142]
    DIRECTION INPUT ;
    USE SIGNAL ;
    SHAPE ABUTMENT ;
    PORT
      LAYER M5 ;
      RECT 1.248 0.000 1.272 0.024 ;
    END
  END wd_in[142]
  PIN wd_in[143]
    DIRECTION INPUT ;
    USE SIGNAL ;
    SHAPE ABUTMENT ;
    PORT
      LAYER M5 ;
      RECT 1.344 0.000 1.368 0.024 ;
    END
  END wd_in[143]
  PIN wd_in[144]
    DIRECTION INPUT ;
    USE SIGNAL ;
    SHAPE ABUTMENT ;
    PORT
      LAYER M5 ;
      RECT 1.440 0.000 1.464 0.024 ;
    END
  END wd_in[144]
  PIN wd_in[145]
    DIRECTION INPUT ;
    USE SIGNAL ;
    SHAPE ABUTMENT ;
    PORT
      LAYER M5 ;
      RECT 1.536 0.000 1.560 0.024 ;
    END
  END wd_in[145]
  PIN wd_in[146]
    DIRECTION INPUT ;
    USE SIGNAL ;
    SHAPE ABUTMENT ;
    PORT
      LAYER M5 ;
      RECT 1.632 0.000 1.656 0.024 ;
    END
  END wd_in[146]
  PIN wd_in[147]
    DIRECTION INPUT ;
    USE SIGNAL ;
    SHAPE ABUTMENT ;
    PORT
      LAYER M5 ;
      RECT 1.728 0.000 1.752 0.024 ;
    END
  END wd_in[147]
  PIN wd_in[148]
    DIRECTION INPUT ;
    USE SIGNAL ;
    SHAPE ABUTMENT ;
    PORT
      LAYER M5 ;
      RECT 1.824 0.000 1.848 0.024 ;
    END
  END wd_in[148]
  PIN wd_in[149]
    DIRECTION INPUT ;
    USE SIGNAL ;
    SHAPE ABUTMENT ;
    PORT
      LAYER M5 ;
      RECT 1.920 0.000 1.944 0.024 ;
    END
  END wd_in[149]
  PIN wd_in[150]
    DIRECTION INPUT ;
    USE SIGNAL ;
    SHAPE ABUTMENT ;
    PORT
      LAYER M5 ;
      RECT 2.016 0.000 2.040 0.024 ;
    END
  END wd_in[150]
  PIN wd_in[151]
    DIRECTION INPUT ;
    USE SIGNAL ;
    SHAPE ABUTMENT ;
    PORT
      LAYER M5 ;
      RECT 2.112 0.000 2.136 0.024 ;
    END
  END wd_in[151]
  PIN wd_in[152]
    DIRECTION INPUT ;
    USE SIGNAL ;
    SHAPE ABUTMENT ;
    PORT
      LAYER M5 ;
      RECT 2.208 0.000 2.232 0.024 ;
    END
  END wd_in[152]
  PIN wd_in[153]
    DIRECTION INPUT ;
    USE SIGNAL ;
    SHAPE ABUTMENT ;
    PORT
      LAYER M5 ;
      RECT 2.304 0.000 2.328 0.024 ;
    END
  END wd_in[153]
  PIN wd_in[154]
    DIRECTION INPUT ;
    USE SIGNAL ;
    SHAPE ABUTMENT ;
    PORT
      LAYER M5 ;
      RECT 2.400 0.000 2.424 0.024 ;
    END
  END wd_in[154]
  PIN wd_in[155]
    DIRECTION INPUT ;
    USE SIGNAL ;
    SHAPE ABUTMENT ;
    PORT
      LAYER M5 ;
      RECT 2.496 0.000 2.520 0.024 ;
    END
  END wd_in[155]
  PIN wd_in[156]
    DIRECTION INPUT ;
    USE SIGNAL ;
    SHAPE ABUTMENT ;
    PORT
      LAYER M5 ;
      RECT 2.592 0.000 2.616 0.024 ;
    END
  END wd_in[156]
  PIN wd_in[157]
    DIRECTION INPUT ;
    USE SIGNAL ;
    SHAPE ABUTMENT ;
    PORT
      LAYER M5 ;
      RECT 2.688 0.000 2.712 0.024 ;
    END
  END wd_in[157]
  PIN wd_in[158]
    DIRECTION INPUT ;
    USE SIGNAL ;
    SHAPE ABUTMENT ;
    PORT
      LAYER M5 ;
      RECT 2.784 0.000 2.808 0.024 ;
    END
  END wd_in[158]
  PIN wd_in[159]
    DIRECTION INPUT ;
    USE SIGNAL ;
    SHAPE ABUTMENT ;
    PORT
      LAYER M5 ;
      RECT 2.880 0.000 2.904 0.024 ;
    END
  END wd_in[159]
  PIN wd_in[160]
    DIRECTION INPUT ;
    USE SIGNAL ;
    SHAPE ABUTMENT ;
    PORT
      LAYER M5 ;
      RECT 2.976 0.000 3.000 0.024 ;
    END
  END wd_in[160]
  PIN wd_in[161]
    DIRECTION INPUT ;
    USE SIGNAL ;
    SHAPE ABUTMENT ;
    PORT
      LAYER M5 ;
      RECT 3.072 0.000 3.096 0.024 ;
    END
  END wd_in[161]
  PIN wd_in[162]
    DIRECTION INPUT ;
    USE SIGNAL ;
    SHAPE ABUTMENT ;
    PORT
      LAYER M5 ;
      RECT 3.168 0.000 3.192 0.024 ;
    END
  END wd_in[162]
  PIN wd_in[163]
    DIRECTION INPUT ;
    USE SIGNAL ;
    SHAPE ABUTMENT ;
    PORT
      LAYER M5 ;
      RECT 3.264 0.000 3.288 0.024 ;
    END
  END wd_in[163]
  PIN wd_in[164]
    DIRECTION INPUT ;
    USE SIGNAL ;
    SHAPE ABUTMENT ;
    PORT
      LAYER M5 ;
      RECT 3.360 0.000 3.384 0.024 ;
    END
  END wd_in[164]
  PIN wd_in[165]
    DIRECTION INPUT ;
    USE SIGNAL ;
    SHAPE ABUTMENT ;
    PORT
      LAYER M5 ;
      RECT 3.456 0.000 3.480 0.024 ;
    END
  END wd_in[165]
  PIN wd_in[166]
    DIRECTION INPUT ;
    USE SIGNAL ;
    SHAPE ABUTMENT ;
    PORT
      LAYER M5 ;
      RECT 3.552 0.000 3.576 0.024 ;
    END
  END wd_in[166]
  PIN wd_in[167]
    DIRECTION INPUT ;
    USE SIGNAL ;
    SHAPE ABUTMENT ;
    PORT
      LAYER M5 ;
      RECT 3.648 0.000 3.672 0.024 ;
    END
  END wd_in[167]
  PIN wd_in[168]
    DIRECTION INPUT ;
    USE SIGNAL ;
    SHAPE ABUTMENT ;
    PORT
      LAYER M5 ;
      RECT 3.744 0.000 3.768 0.024 ;
    END
  END wd_in[168]
  PIN wd_in[169]
    DIRECTION INPUT ;
    USE SIGNAL ;
    SHAPE ABUTMENT ;
    PORT
      LAYER M5 ;
      RECT 3.840 0.000 3.864 0.024 ;
    END
  END wd_in[169]
  PIN wd_in[170]
    DIRECTION INPUT ;
    USE SIGNAL ;
    SHAPE ABUTMENT ;
    PORT
      LAYER M5 ;
      RECT 3.936 0.000 3.960 0.024 ;
    END
  END wd_in[170]
  PIN wd_in[171]
    DIRECTION INPUT ;
    USE SIGNAL ;
    SHAPE ABUTMENT ;
    PORT
      LAYER M5 ;
      RECT 4.032 0.000 4.056 0.024 ;
    END
  END wd_in[171]
  PIN wd_in[172]
    DIRECTION INPUT ;
    USE SIGNAL ;
    SHAPE ABUTMENT ;
    PORT
      LAYER M5 ;
      RECT 4.128 0.000 4.152 0.024 ;
    END
  END wd_in[172]
  PIN wd_in[173]
    DIRECTION INPUT ;
    USE SIGNAL ;
    SHAPE ABUTMENT ;
    PORT
      LAYER M5 ;
      RECT 4.224 0.000 4.248 0.024 ;
    END
  END wd_in[173]
  PIN wd_in[174]
    DIRECTION INPUT ;
    USE SIGNAL ;
    SHAPE ABUTMENT ;
    PORT
      LAYER M5 ;
      RECT 4.320 0.000 4.344 0.024 ;
    END
  END wd_in[174]
  PIN wd_in[175]
    DIRECTION INPUT ;
    USE SIGNAL ;
    SHAPE ABUTMENT ;
    PORT
      LAYER M5 ;
      RECT 4.416 0.000 4.440 0.024 ;
    END
  END wd_in[175]
  PIN wd_in[176]
    DIRECTION INPUT ;
    USE SIGNAL ;
    SHAPE ABUTMENT ;
    PORT
      LAYER M5 ;
      RECT 4.512 0.000 4.536 0.024 ;
    END
  END wd_in[176]
  PIN wd_in[177]
    DIRECTION INPUT ;
    USE SIGNAL ;
    SHAPE ABUTMENT ;
    PORT
      LAYER M5 ;
      RECT 4.608 0.000 4.632 0.024 ;
    END
  END wd_in[177]
  PIN wd_in[178]
    DIRECTION INPUT ;
    USE SIGNAL ;
    SHAPE ABUTMENT ;
    PORT
      LAYER M5 ;
      RECT 4.704 0.000 4.728 0.024 ;
    END
  END wd_in[178]
  PIN wd_in[179]
    DIRECTION INPUT ;
    USE SIGNAL ;
    SHAPE ABUTMENT ;
    PORT
      LAYER M5 ;
      RECT 4.800 0.000 4.824 0.024 ;
    END
  END wd_in[179]
  PIN wd_in[180]
    DIRECTION INPUT ;
    USE SIGNAL ;
    SHAPE ABUTMENT ;
    PORT
      LAYER M5 ;
      RECT 4.896 0.000 4.920 0.024 ;
    END
  END wd_in[180]
  PIN wd_in[181]
    DIRECTION INPUT ;
    USE SIGNAL ;
    SHAPE ABUTMENT ;
    PORT
      LAYER M5 ;
      RECT 4.992 0.000 5.016 0.024 ;
    END
  END wd_in[181]
  PIN wd_in[182]
    DIRECTION INPUT ;
    USE SIGNAL ;
    SHAPE ABUTMENT ;
    PORT
      LAYER M5 ;
      RECT 5.088 0.000 5.112 0.024 ;
    END
  END wd_in[182]
  PIN wd_in[183]
    DIRECTION INPUT ;
    USE SIGNAL ;
    SHAPE ABUTMENT ;
    PORT
      LAYER M5 ;
      RECT 5.184 0.000 5.208 0.024 ;
    END
  END wd_in[183]
  PIN wd_in[184]
    DIRECTION INPUT ;
    USE SIGNAL ;
    SHAPE ABUTMENT ;
    PORT
      LAYER M5 ;
      RECT 5.280 0.000 5.304 0.024 ;
    END
  END wd_in[184]
  PIN wd_in[185]
    DIRECTION INPUT ;
    USE SIGNAL ;
    SHAPE ABUTMENT ;
    PORT
      LAYER M5 ;
      RECT 5.376 0.000 5.400 0.024 ;
    END
  END wd_in[185]
  PIN wd_in[186]
    DIRECTION INPUT ;
    USE SIGNAL ;
    SHAPE ABUTMENT ;
    PORT
      LAYER M5 ;
      RECT 5.472 0.000 5.496 0.024 ;
    END
  END wd_in[186]
  PIN wd_in[187]
    DIRECTION INPUT ;
    USE SIGNAL ;
    SHAPE ABUTMENT ;
    PORT
      LAYER M5 ;
      RECT 5.568 0.000 5.592 0.024 ;
    END
  END wd_in[187]
  PIN wd_in[188]
    DIRECTION INPUT ;
    USE SIGNAL ;
    SHAPE ABUTMENT ;
    PORT
      LAYER M5 ;
      RECT 5.664 0.000 5.688 0.024 ;
    END
  END wd_in[188]
  PIN wd_in[189]
    DIRECTION INPUT ;
    USE SIGNAL ;
    SHAPE ABUTMENT ;
    PORT
      LAYER M5 ;
      RECT 5.760 0.000 5.784 0.024 ;
    END
  END wd_in[189]
  PIN wd_in[190]
    DIRECTION INPUT ;
    USE SIGNAL ;
    SHAPE ABUTMENT ;
    PORT
      LAYER M5 ;
      RECT 5.856 0.000 5.880 0.024 ;
    END
  END wd_in[190]
  PIN wd_in[191]
    DIRECTION INPUT ;
    USE SIGNAL ;
    SHAPE ABUTMENT ;
    PORT
      LAYER M5 ;
      RECT 5.952 0.000 5.976 0.024 ;
    END
  END wd_in[191]
  PIN wd_in[192]
    DIRECTION INPUT ;
    USE SIGNAL ;
    SHAPE ABUTMENT ;
    PORT
      LAYER M5 ;
      RECT 6.048 0.000 6.072 0.024 ;
    END
  END wd_in[192]
  PIN wd_in[193]
    DIRECTION INPUT ;
    USE SIGNAL ;
    SHAPE ABUTMENT ;
    PORT
      LAYER M5 ;
      RECT 6.144 0.000 6.168 0.024 ;
    END
  END wd_in[193]
  PIN wd_in[194]
    DIRECTION INPUT ;
    USE SIGNAL ;
    SHAPE ABUTMENT ;
    PORT
      LAYER M5 ;
      RECT 6.240 0.000 6.264 0.024 ;
    END
  END wd_in[194]
  PIN wd_in[195]
    DIRECTION INPUT ;
    USE SIGNAL ;
    SHAPE ABUTMENT ;
    PORT
      LAYER M5 ;
      RECT 6.336 0.000 6.360 0.024 ;
    END
  END wd_in[195]
  PIN wd_in[196]
    DIRECTION INPUT ;
    USE SIGNAL ;
    SHAPE ABUTMENT ;
    PORT
      LAYER M5 ;
      RECT 6.432 0.000 6.456 0.024 ;
    END
  END wd_in[196]
  PIN wd_in[197]
    DIRECTION INPUT ;
    USE SIGNAL ;
    SHAPE ABUTMENT ;
    PORT
      LAYER M5 ;
      RECT 6.528 0.000 6.552 0.024 ;
    END
  END wd_in[197]
  PIN wd_in[198]
    DIRECTION INPUT ;
    USE SIGNAL ;
    SHAPE ABUTMENT ;
    PORT
      LAYER M5 ;
      RECT 6.624 0.000 6.648 0.024 ;
    END
  END wd_in[198]
  PIN wd_in[199]
    DIRECTION INPUT ;
    USE SIGNAL ;
    SHAPE ABUTMENT ;
    PORT
      LAYER M5 ;
      RECT 6.720 0.000 6.744 0.024 ;
    END
  END wd_in[199]
  PIN wd_in[200]
    DIRECTION INPUT ;
    USE SIGNAL ;
    SHAPE ABUTMENT ;
    PORT
      LAYER M5 ;
      RECT 6.816 0.000 6.840 0.024 ;
    END
  END wd_in[200]
  PIN wd_in[201]
    DIRECTION INPUT ;
    USE SIGNAL ;
    SHAPE ABUTMENT ;
    PORT
      LAYER M5 ;
      RECT 6.912 0.000 6.936 0.024 ;
    END
  END wd_in[201]
  PIN wd_in[202]
    DIRECTION INPUT ;
    USE SIGNAL ;
    SHAPE ABUTMENT ;
    PORT
      LAYER M5 ;
      RECT 7.008 0.000 7.032 0.024 ;
    END
  END wd_in[202]
  PIN wd_in[203]
    DIRECTION INPUT ;
    USE SIGNAL ;
    SHAPE ABUTMENT ;
    PORT
      LAYER M5 ;
      RECT 7.104 0.000 7.128 0.024 ;
    END
  END wd_in[203]
  PIN wd_in[204]
    DIRECTION INPUT ;
    USE SIGNAL ;
    SHAPE ABUTMENT ;
    PORT
      LAYER M5 ;
      RECT 7.200 0.000 7.224 0.024 ;
    END
  END wd_in[204]
  PIN wd_in[205]
    DIRECTION INPUT ;
    USE SIGNAL ;
    SHAPE ABUTMENT ;
    PORT
      LAYER M5 ;
      RECT 7.296 0.000 7.320 0.024 ;
    END
  END wd_in[205]
  PIN wd_in[206]
    DIRECTION INPUT ;
    USE SIGNAL ;
    SHAPE ABUTMENT ;
    PORT
      LAYER M5 ;
      RECT 7.392 0.000 7.416 0.024 ;
    END
  END wd_in[206]
  PIN wd_in[207]
    DIRECTION INPUT ;
    USE SIGNAL ;
    SHAPE ABUTMENT ;
    PORT
      LAYER M5 ;
      RECT 7.488 0.000 7.512 0.024 ;
    END
  END wd_in[207]
  PIN wd_in[208]
    DIRECTION INPUT ;
    USE SIGNAL ;
    SHAPE ABUTMENT ;
    PORT
      LAYER M5 ;
      RECT 7.584 0.000 7.608 0.024 ;
    END
  END wd_in[208]
  PIN wd_in[209]
    DIRECTION INPUT ;
    USE SIGNAL ;
    SHAPE ABUTMENT ;
    PORT
      LAYER M5 ;
      RECT 7.680 0.000 7.704 0.024 ;
    END
  END wd_in[209]
  PIN wd_in[210]
    DIRECTION INPUT ;
    USE SIGNAL ;
    SHAPE ABUTMENT ;
    PORT
      LAYER M5 ;
      RECT 7.776 0.000 7.800 0.024 ;
    END
  END wd_in[210]
  PIN wd_in[211]
    DIRECTION INPUT ;
    USE SIGNAL ;
    SHAPE ABUTMENT ;
    PORT
      LAYER M5 ;
      RECT 7.872 0.000 7.896 0.024 ;
    END
  END wd_in[211]
  PIN wd_in[212]
    DIRECTION INPUT ;
    USE SIGNAL ;
    SHAPE ABUTMENT ;
    PORT
      LAYER M5 ;
      RECT 7.968 0.000 7.992 0.024 ;
    END
  END wd_in[212]
  PIN wd_in[213]
    DIRECTION INPUT ;
    USE SIGNAL ;
    SHAPE ABUTMENT ;
    PORT
      LAYER M5 ;
      RECT 8.064 0.000 8.088 0.024 ;
    END
  END wd_in[213]
  PIN wd_in[214]
    DIRECTION INPUT ;
    USE SIGNAL ;
    SHAPE ABUTMENT ;
    PORT
      LAYER M5 ;
      RECT 8.160 0.000 8.184 0.024 ;
    END
  END wd_in[214]
  PIN wd_in[215]
    DIRECTION INPUT ;
    USE SIGNAL ;
    SHAPE ABUTMENT ;
    PORT
      LAYER M5 ;
      RECT 8.256 0.000 8.280 0.024 ;
    END
  END wd_in[215]
  PIN wd_in[216]
    DIRECTION INPUT ;
    USE SIGNAL ;
    SHAPE ABUTMENT ;
    PORT
      LAYER M5 ;
      RECT 8.352 0.000 8.376 0.024 ;
    END
  END wd_in[216]
  PIN wd_in[217]
    DIRECTION INPUT ;
    USE SIGNAL ;
    SHAPE ABUTMENT ;
    PORT
      LAYER M5 ;
      RECT 8.448 0.000 8.472 0.024 ;
    END
  END wd_in[217]
  PIN wd_in[218]
    DIRECTION INPUT ;
    USE SIGNAL ;
    SHAPE ABUTMENT ;
    PORT
      LAYER M5 ;
      RECT 8.544 0.000 8.568 0.024 ;
    END
  END wd_in[218]
  PIN wd_in[219]
    DIRECTION INPUT ;
    USE SIGNAL ;
    SHAPE ABUTMENT ;
    PORT
      LAYER M5 ;
      RECT 8.640 0.000 8.664 0.024 ;
    END
  END wd_in[219]
  PIN wd_in[220]
    DIRECTION INPUT ;
    USE SIGNAL ;
    SHAPE ABUTMENT ;
    PORT
      LAYER M5 ;
      RECT 8.736 0.000 8.760 0.024 ;
    END
  END wd_in[220]
  PIN wd_in[221]
    DIRECTION INPUT ;
    USE SIGNAL ;
    SHAPE ABUTMENT ;
    PORT
      LAYER M5 ;
      RECT 8.832 0.000 8.856 0.024 ;
    END
  END wd_in[221]
  PIN wd_in[222]
    DIRECTION INPUT ;
    USE SIGNAL ;
    SHAPE ABUTMENT ;
    PORT
      LAYER M5 ;
      RECT 8.928 0.000 8.952 0.024 ;
    END
  END wd_in[222]
  PIN wd_in[223]
    DIRECTION INPUT ;
    USE SIGNAL ;
    SHAPE ABUTMENT ;
    PORT
      LAYER M5 ;
      RECT 9.024 0.000 9.048 0.024 ;
    END
  END wd_in[223]
  PIN wd_in[224]
    DIRECTION INPUT ;
    USE SIGNAL ;
    SHAPE ABUTMENT ;
    PORT
      LAYER M5 ;
      RECT 9.120 0.000 9.144 0.024 ;
    END
  END wd_in[224]
  PIN wd_in[225]
    DIRECTION INPUT ;
    USE SIGNAL ;
    SHAPE ABUTMENT ;
    PORT
      LAYER M5 ;
      RECT 9.216 0.000 9.240 0.024 ;
    END
  END wd_in[225]
  PIN wd_in[226]
    DIRECTION INPUT ;
    USE SIGNAL ;
    SHAPE ABUTMENT ;
    PORT
      LAYER M5 ;
      RECT 9.312 0.000 9.336 0.024 ;
    END
  END wd_in[226]
  PIN wd_in[227]
    DIRECTION INPUT ;
    USE SIGNAL ;
    SHAPE ABUTMENT ;
    PORT
      LAYER M5 ;
      RECT 9.408 0.000 9.432 0.024 ;
    END
  END wd_in[227]
  PIN wd_in[228]
    DIRECTION INPUT ;
    USE SIGNAL ;
    SHAPE ABUTMENT ;
    PORT
      LAYER M5 ;
      RECT 9.504 0.000 9.528 0.024 ;
    END
  END wd_in[228]
  PIN wd_in[229]
    DIRECTION INPUT ;
    USE SIGNAL ;
    SHAPE ABUTMENT ;
    PORT
      LAYER M5 ;
      RECT 9.600 0.000 9.624 0.024 ;
    END
  END wd_in[229]
  PIN wd_in[230]
    DIRECTION INPUT ;
    USE SIGNAL ;
    SHAPE ABUTMENT ;
    PORT
      LAYER M5 ;
      RECT 9.696 0.000 9.720 0.024 ;
    END
  END wd_in[230]
  PIN wd_in[231]
    DIRECTION INPUT ;
    USE SIGNAL ;
    SHAPE ABUTMENT ;
    PORT
      LAYER M5 ;
      RECT 9.792 0.000 9.816 0.024 ;
    END
  END wd_in[231]
  PIN wd_in[232]
    DIRECTION INPUT ;
    USE SIGNAL ;
    SHAPE ABUTMENT ;
    PORT
      LAYER M5 ;
      RECT 9.888 0.000 9.912 0.024 ;
    END
  END wd_in[232]
  PIN wd_in[233]
    DIRECTION INPUT ;
    USE SIGNAL ;
    SHAPE ABUTMENT ;
    PORT
      LAYER M5 ;
      RECT 9.984 0.000 10.008 0.024 ;
    END
  END wd_in[233]
  PIN wd_in[234]
    DIRECTION INPUT ;
    USE SIGNAL ;
    SHAPE ABUTMENT ;
    PORT
      LAYER M5 ;
      RECT 10.080 0.000 10.104 0.024 ;
    END
  END wd_in[234]
  PIN wd_in[235]
    DIRECTION INPUT ;
    USE SIGNAL ;
    SHAPE ABUTMENT ;
    PORT
      LAYER M5 ;
      RECT 10.176 0.000 10.200 0.024 ;
    END
  END wd_in[235]
  PIN wd_in[236]
    DIRECTION INPUT ;
    USE SIGNAL ;
    SHAPE ABUTMENT ;
    PORT
      LAYER M5 ;
      RECT 10.272 0.000 10.296 0.024 ;
    END
  END wd_in[236]
  PIN wd_in[237]
    DIRECTION INPUT ;
    USE SIGNAL ;
    SHAPE ABUTMENT ;
    PORT
      LAYER M5 ;
      RECT 10.368 0.000 10.392 0.024 ;
    END
  END wd_in[237]
  PIN wd_in[238]
    DIRECTION INPUT ;
    USE SIGNAL ;
    SHAPE ABUTMENT ;
    PORT
      LAYER M5 ;
      RECT 10.464 0.000 10.488 0.024 ;
    END
  END wd_in[238]
  PIN wd_in[239]
    DIRECTION INPUT ;
    USE SIGNAL ;
    SHAPE ABUTMENT ;
    PORT
      LAYER M5 ;
      RECT 10.560 0.000 10.584 0.024 ;
    END
  END wd_in[239]
  PIN wd_in[240]
    DIRECTION INPUT ;
    USE SIGNAL ;
    SHAPE ABUTMENT ;
    PORT
      LAYER M5 ;
      RECT 10.656 0.000 10.680 0.024 ;
    END
  END wd_in[240]
  PIN wd_in[241]
    DIRECTION INPUT ;
    USE SIGNAL ;
    SHAPE ABUTMENT ;
    PORT
      LAYER M5 ;
      RECT 10.752 0.000 10.776 0.024 ;
    END
  END wd_in[241]
  PIN wd_in[242]
    DIRECTION INPUT ;
    USE SIGNAL ;
    SHAPE ABUTMENT ;
    PORT
      LAYER M5 ;
      RECT 10.848 0.000 10.872 0.024 ;
    END
  END wd_in[242]
  PIN wd_in[243]
    DIRECTION INPUT ;
    USE SIGNAL ;
    SHAPE ABUTMENT ;
    PORT
      LAYER M5 ;
      RECT 10.944 0.000 10.968 0.024 ;
    END
  END wd_in[243]
  PIN wd_in[244]
    DIRECTION INPUT ;
    USE SIGNAL ;
    SHAPE ABUTMENT ;
    PORT
      LAYER M5 ;
      RECT 11.040 0.000 11.064 0.024 ;
    END
  END wd_in[244]
  PIN wd_in[245]
    DIRECTION INPUT ;
    USE SIGNAL ;
    SHAPE ABUTMENT ;
    PORT
      LAYER M5 ;
      RECT 11.136 0.000 11.160 0.024 ;
    END
  END wd_in[245]
  PIN wd_in[246]
    DIRECTION INPUT ;
    USE SIGNAL ;
    SHAPE ABUTMENT ;
    PORT
      LAYER M5 ;
      RECT 11.232 0.000 11.256 0.024 ;
    END
  END wd_in[246]
  PIN wd_in[247]
    DIRECTION INPUT ;
    USE SIGNAL ;
    SHAPE ABUTMENT ;
    PORT
      LAYER M5 ;
      RECT 11.328 0.000 11.352 0.024 ;
    END
  END wd_in[247]
  PIN wd_in[248]
    DIRECTION INPUT ;
    USE SIGNAL ;
    SHAPE ABUTMENT ;
    PORT
      LAYER M5 ;
      RECT 11.424 0.000 11.448 0.024 ;
    END
  END wd_in[248]
  PIN wd_in[249]
    DIRECTION INPUT ;
    USE SIGNAL ;
    SHAPE ABUTMENT ;
    PORT
      LAYER M5 ;
      RECT 11.520 0.000 11.544 0.024 ;
    END
  END wd_in[249]
  PIN wd_in[250]
    DIRECTION INPUT ;
    USE SIGNAL ;
    SHAPE ABUTMENT ;
    PORT
      LAYER M5 ;
      RECT 11.616 0.000 11.640 0.024 ;
    END
  END wd_in[250]
  PIN wd_in[251]
    DIRECTION INPUT ;
    USE SIGNAL ;
    SHAPE ABUTMENT ;
    PORT
      LAYER M5 ;
      RECT 11.712 0.000 11.736 0.024 ;
    END
  END wd_in[251]
  PIN wd_in[252]
    DIRECTION INPUT ;
    USE SIGNAL ;
    SHAPE ABUTMENT ;
    PORT
      LAYER M5 ;
      RECT 11.808 0.000 11.832 0.024 ;
    END
  END wd_in[252]
  PIN wd_in[253]
    DIRECTION INPUT ;
    USE SIGNAL ;
    SHAPE ABUTMENT ;
    PORT
      LAYER M5 ;
      RECT 11.904 0.000 11.928 0.024 ;
    END
  END wd_in[253]
  PIN wd_in[254]
    DIRECTION INPUT ;
    USE SIGNAL ;
    SHAPE ABUTMENT ;
    PORT
      LAYER M5 ;
      RECT 12.000 0.000 12.024 0.024 ;
    END
  END wd_in[254]
  PIN wd_in[255]
    DIRECTION INPUT ;
    USE SIGNAL ;
    SHAPE ABUTMENT ;
    PORT
      LAYER M5 ;
      RECT 12.096 0.000 12.120 0.024 ;
    END
  END wd_in[255]
  PIN w_mask_in[0]
    DIRECTION INPUT ;
    USE SIGNAL ;
    SHAPE ABUTMENT ;
    PORT
      LAYER M5 ;
      RECT 12.192 0.000 12.216 0.024 ;
    END
  END w_mask_in[0]
  PIN w_mask_in[1]
    DIRECTION INPUT ;
    USE SIGNAL ;
    SHAPE ABUTMENT ;
    PORT
      LAYER M5 ;
      RECT 12.288 0.000 12.312 0.024 ;
    END
  END w_mask_in[1]
  PIN w_mask_in[2]
    DIRECTION INPUT ;
    USE SIGNAL ;
    SHAPE ABUTMENT ;
    PORT
      LAYER M5 ;
      RECT 12.384 0.000 12.408 0.024 ;
    END
  END w_mask_in[2]
  PIN w_mask_in[3]
    DIRECTION INPUT ;
    USE SIGNAL ;
    SHAPE ABUTMENT ;
    PORT
      LAYER M5 ;
      RECT 12.480 0.000 12.504 0.024 ;
    END
  END w_mask_in[3]
  PIN w_mask_in[4]
    DIRECTION INPUT ;
    USE SIGNAL ;
    SHAPE ABUTMENT ;
    PORT
      LAYER M5 ;
      RECT 12.576 0.000 12.600 0.024 ;
    END
  END w_mask_in[4]
  PIN w_mask_in[5]
    DIRECTION INPUT ;
    USE SIGNAL ;
    SHAPE ABUTMENT ;
    PORT
      LAYER M5 ;
      RECT 12.672 0.000 12.696 0.024 ;
    END
  END w_mask_in[5]
  PIN w_mask_in[6]
    DIRECTION INPUT ;
    USE SIGNAL ;
    SHAPE ABUTMENT ;
    PORT
      LAYER M5 ;
      RECT 12.768 0.000 12.792 0.024 ;
    END
  END w_mask_in[6]
  PIN w_mask_in[7]
    DIRECTION INPUT ;
    USE SIGNAL ;
    SHAPE ABUTMENT ;
    PORT
      LAYER M5 ;
      RECT 12.864 0.000 12.888 0.024 ;
    END
  END w_mask_in[7]
  PIN w_mask_in[8]
    DIRECTION INPUT ;
    USE SIGNAL ;
    SHAPE ABUTMENT ;
    PORT
      LAYER M5 ;
      RECT 12.960 0.000 12.984 0.024 ;
    END
  END w_mask_in[8]
  PIN w_mask_in[9]
    DIRECTION INPUT ;
    USE SIGNAL ;
    SHAPE ABUTMENT ;
    PORT
      LAYER M5 ;
      RECT 13.056 0.000 13.080 0.024 ;
    END
  END w_mask_in[9]
  PIN w_mask_in[10]
    DIRECTION INPUT ;
    USE SIGNAL ;
    SHAPE ABUTMENT ;
    PORT
      LAYER M5 ;
      RECT 13.152 0.000 13.176 0.024 ;
    END
  END w_mask_in[10]
  PIN w_mask_in[11]
    DIRECTION INPUT ;
    USE SIGNAL ;
    SHAPE ABUTMENT ;
    PORT
      LAYER M5 ;
      RECT 13.248 0.000 13.272 0.024 ;
    END
  END w_mask_in[11]
  PIN w_mask_in[12]
    DIRECTION INPUT ;
    USE SIGNAL ;
    SHAPE ABUTMENT ;
    PORT
      LAYER M5 ;
      RECT 13.344 0.000 13.368 0.024 ;
    END
  END w_mask_in[12]
  PIN w_mask_in[13]
    DIRECTION INPUT ;
    USE SIGNAL ;
    SHAPE ABUTMENT ;
    PORT
      LAYER M5 ;
      RECT 13.440 0.000 13.464 0.024 ;
    END
  END w_mask_in[13]
  PIN w_mask_in[14]
    DIRECTION INPUT ;
    USE SIGNAL ;
    SHAPE ABUTMENT ;
    PORT
      LAYER M5 ;
      RECT 13.536 0.000 13.560 0.024 ;
    END
  END w_mask_in[14]
  PIN w_mask_in[15]
    DIRECTION INPUT ;
    USE SIGNAL ;
    SHAPE ABUTMENT ;
    PORT
      LAYER M5 ;
      RECT 13.632 0.000 13.656 0.024 ;
    END
  END w_mask_in[15]
  PIN w_mask_in[16]
    DIRECTION INPUT ;
    USE SIGNAL ;
    SHAPE ABUTMENT ;
    PORT
      LAYER M5 ;
      RECT 13.728 0.000 13.752 0.024 ;
    END
  END w_mask_in[16]
  PIN w_mask_in[17]
    DIRECTION INPUT ;
    USE SIGNAL ;
    SHAPE ABUTMENT ;
    PORT
      LAYER M5 ;
      RECT 13.824 0.000 13.848 0.024 ;
    END
  END w_mask_in[17]
  PIN w_mask_in[18]
    DIRECTION INPUT ;
    USE SIGNAL ;
    SHAPE ABUTMENT ;
    PORT
      LAYER M5 ;
      RECT 13.920 0.000 13.944 0.024 ;
    END
  END w_mask_in[18]
  PIN w_mask_in[19]
    DIRECTION INPUT ;
    USE SIGNAL ;
    SHAPE ABUTMENT ;
    PORT
      LAYER M5 ;
      RECT 14.016 0.000 14.040 0.024 ;
    END
  END w_mask_in[19]
  PIN w_mask_in[20]
    DIRECTION INPUT ;
    USE SIGNAL ;
    SHAPE ABUTMENT ;
    PORT
      LAYER M5 ;
      RECT 14.112 0.000 14.136 0.024 ;
    END
  END w_mask_in[20]
  PIN w_mask_in[21]
    DIRECTION INPUT ;
    USE SIGNAL ;
    SHAPE ABUTMENT ;
    PORT
      LAYER M5 ;
      RECT 14.208 0.000 14.232 0.024 ;
    END
  END w_mask_in[21]
  PIN w_mask_in[22]
    DIRECTION INPUT ;
    USE SIGNAL ;
    SHAPE ABUTMENT ;
    PORT
      LAYER M5 ;
      RECT 14.304 0.000 14.328 0.024 ;
    END
  END w_mask_in[22]
  PIN w_mask_in[23]
    DIRECTION INPUT ;
    USE SIGNAL ;
    SHAPE ABUTMENT ;
    PORT
      LAYER M5 ;
      RECT 14.400 0.000 14.424 0.024 ;
    END
  END w_mask_in[23]
  PIN w_mask_in[24]
    DIRECTION INPUT ;
    USE SIGNAL ;
    SHAPE ABUTMENT ;
    PORT
      LAYER M5 ;
      RECT 14.496 0.000 14.520 0.024 ;
    END
  END w_mask_in[24]
  PIN w_mask_in[25]
    DIRECTION INPUT ;
    USE SIGNAL ;
    SHAPE ABUTMENT ;
    PORT
      LAYER M5 ;
      RECT 14.592 0.000 14.616 0.024 ;
    END
  END w_mask_in[25]
  PIN w_mask_in[26]
    DIRECTION INPUT ;
    USE SIGNAL ;
    SHAPE ABUTMENT ;
    PORT
      LAYER M5 ;
      RECT 14.688 0.000 14.712 0.024 ;
    END
  END w_mask_in[26]
  PIN w_mask_in[27]
    DIRECTION INPUT ;
    USE SIGNAL ;
    SHAPE ABUTMENT ;
    PORT
      LAYER M5 ;
      RECT 14.784 0.000 14.808 0.024 ;
    END
  END w_mask_in[27]
  PIN w_mask_in[28]
    DIRECTION INPUT ;
    USE SIGNAL ;
    SHAPE ABUTMENT ;
    PORT
      LAYER M5 ;
      RECT 14.880 0.000 14.904 0.024 ;
    END
  END w_mask_in[28]
  PIN w_mask_in[29]
    DIRECTION INPUT ;
    USE SIGNAL ;
    SHAPE ABUTMENT ;
    PORT
      LAYER M5 ;
      RECT 14.976 0.000 15.000 0.024 ;
    END
  END w_mask_in[29]
  PIN w_mask_in[30]
    DIRECTION INPUT ;
    USE SIGNAL ;
    SHAPE ABUTMENT ;
    PORT
      LAYER M5 ;
      RECT 15.072 0.000 15.096 0.024 ;
    END
  END w_mask_in[30]
  PIN w_mask_in[31]
    DIRECTION INPUT ;
    USE SIGNAL ;
    SHAPE ABUTMENT ;
    PORT
      LAYER M5 ;
      RECT 15.168 0.000 15.192 0.024 ;
    END
  END w_mask_in[31]
  PIN w_mask_in[32]
    DIRECTION INPUT ;
    USE SIGNAL ;
    SHAPE ABUTMENT ;
    PORT
      LAYER M5 ;
      RECT 15.264 0.000 15.288 0.024 ;
    END
  END w_mask_in[32]
  PIN w_mask_in[33]
    DIRECTION INPUT ;
    USE SIGNAL ;
    SHAPE ABUTMENT ;
    PORT
      LAYER M5 ;
      RECT 15.360 0.000 15.384 0.024 ;
    END
  END w_mask_in[33]
  PIN w_mask_in[34]
    DIRECTION INPUT ;
    USE SIGNAL ;
    SHAPE ABUTMENT ;
    PORT
      LAYER M5 ;
      RECT 15.456 0.000 15.480 0.024 ;
    END
  END w_mask_in[34]
  PIN w_mask_in[35]
    DIRECTION INPUT ;
    USE SIGNAL ;
    SHAPE ABUTMENT ;
    PORT
      LAYER M5 ;
      RECT 15.552 0.000 15.576 0.024 ;
    END
  END w_mask_in[35]
  PIN w_mask_in[36]
    DIRECTION INPUT ;
    USE SIGNAL ;
    SHAPE ABUTMENT ;
    PORT
      LAYER M5 ;
      RECT 15.648 0.000 15.672 0.024 ;
    END
  END w_mask_in[36]
  PIN w_mask_in[37]
    DIRECTION INPUT ;
    USE SIGNAL ;
    SHAPE ABUTMENT ;
    PORT
      LAYER M5 ;
      RECT 15.744 0.000 15.768 0.024 ;
    END
  END w_mask_in[37]
  PIN w_mask_in[38]
    DIRECTION INPUT ;
    USE SIGNAL ;
    SHAPE ABUTMENT ;
    PORT
      LAYER M5 ;
      RECT 15.840 0.000 15.864 0.024 ;
    END
  END w_mask_in[38]
  PIN w_mask_in[39]
    DIRECTION INPUT ;
    USE SIGNAL ;
    SHAPE ABUTMENT ;
    PORT
      LAYER M5 ;
      RECT 15.936 0.000 15.960 0.024 ;
    END
  END w_mask_in[39]
  PIN w_mask_in[40]
    DIRECTION INPUT ;
    USE SIGNAL ;
    SHAPE ABUTMENT ;
    PORT
      LAYER M5 ;
      RECT 16.032 0.000 16.056 0.024 ;
    END
  END w_mask_in[40]
  PIN w_mask_in[41]
    DIRECTION INPUT ;
    USE SIGNAL ;
    SHAPE ABUTMENT ;
    PORT
      LAYER M5 ;
      RECT 16.128 0.000 16.152 0.024 ;
    END
  END w_mask_in[41]
  PIN w_mask_in[42]
    DIRECTION INPUT ;
    USE SIGNAL ;
    SHAPE ABUTMENT ;
    PORT
      LAYER M5 ;
      RECT 16.224 0.000 16.248 0.024 ;
    END
  END w_mask_in[42]
  PIN w_mask_in[43]
    DIRECTION INPUT ;
    USE SIGNAL ;
    SHAPE ABUTMENT ;
    PORT
      LAYER M5 ;
      RECT 16.320 0.000 16.344 0.024 ;
    END
  END w_mask_in[43]
  PIN w_mask_in[44]
    DIRECTION INPUT ;
    USE SIGNAL ;
    SHAPE ABUTMENT ;
    PORT
      LAYER M5 ;
      RECT 16.416 0.000 16.440 0.024 ;
    END
  END w_mask_in[44]
  PIN w_mask_in[45]
    DIRECTION INPUT ;
    USE SIGNAL ;
    SHAPE ABUTMENT ;
    PORT
      LAYER M5 ;
      RECT 16.512 0.000 16.536 0.024 ;
    END
  END w_mask_in[45]
  PIN w_mask_in[46]
    DIRECTION INPUT ;
    USE SIGNAL ;
    SHAPE ABUTMENT ;
    PORT
      LAYER M5 ;
      RECT 16.608 0.000 16.632 0.024 ;
    END
  END w_mask_in[46]
  PIN w_mask_in[47]
    DIRECTION INPUT ;
    USE SIGNAL ;
    SHAPE ABUTMENT ;
    PORT
      LAYER M5 ;
      RECT 16.704 0.000 16.728 0.024 ;
    END
  END w_mask_in[47]
  PIN w_mask_in[48]
    DIRECTION INPUT ;
    USE SIGNAL ;
    SHAPE ABUTMENT ;
    PORT
      LAYER M5 ;
      RECT 16.800 0.000 16.824 0.024 ;
    END
  END w_mask_in[48]
  PIN w_mask_in[49]
    DIRECTION INPUT ;
    USE SIGNAL ;
    SHAPE ABUTMENT ;
    PORT
      LAYER M5 ;
      RECT 16.896 0.000 16.920 0.024 ;
    END
  END w_mask_in[49]
  PIN w_mask_in[50]
    DIRECTION INPUT ;
    USE SIGNAL ;
    SHAPE ABUTMENT ;
    PORT
      LAYER M5 ;
      RECT 16.992 0.000 17.016 0.024 ;
    END
  END w_mask_in[50]
  PIN w_mask_in[51]
    DIRECTION INPUT ;
    USE SIGNAL ;
    SHAPE ABUTMENT ;
    PORT
      LAYER M5 ;
      RECT 17.088 0.000 17.112 0.024 ;
    END
  END w_mask_in[51]
  PIN w_mask_in[52]
    DIRECTION INPUT ;
    USE SIGNAL ;
    SHAPE ABUTMENT ;
    PORT
      LAYER M5 ;
      RECT 17.184 0.000 17.208 0.024 ;
    END
  END w_mask_in[52]
  PIN w_mask_in[53]
    DIRECTION INPUT ;
    USE SIGNAL ;
    SHAPE ABUTMENT ;
    PORT
      LAYER M5 ;
      RECT 17.280 0.000 17.304 0.024 ;
    END
  END w_mask_in[53]
  PIN w_mask_in[54]
    DIRECTION INPUT ;
    USE SIGNAL ;
    SHAPE ABUTMENT ;
    PORT
      LAYER M5 ;
      RECT 17.376 0.000 17.400 0.024 ;
    END
  END w_mask_in[54]
  PIN w_mask_in[55]
    DIRECTION INPUT ;
    USE SIGNAL ;
    SHAPE ABUTMENT ;
    PORT
      LAYER M5 ;
      RECT 17.472 0.000 17.496 0.024 ;
    END
  END w_mask_in[55]
  PIN w_mask_in[56]
    DIRECTION INPUT ;
    USE SIGNAL ;
    SHAPE ABUTMENT ;
    PORT
      LAYER M5 ;
      RECT 17.568 0.000 17.592 0.024 ;
    END
  END w_mask_in[56]
  PIN w_mask_in[57]
    DIRECTION INPUT ;
    USE SIGNAL ;
    SHAPE ABUTMENT ;
    PORT
      LAYER M5 ;
      RECT 17.664 0.000 17.688 0.024 ;
    END
  END w_mask_in[57]
  PIN w_mask_in[58]
    DIRECTION INPUT ;
    USE SIGNAL ;
    SHAPE ABUTMENT ;
    PORT
      LAYER M5 ;
      RECT 17.760 0.000 17.784 0.024 ;
    END
  END w_mask_in[58]
  PIN w_mask_in[59]
    DIRECTION INPUT ;
    USE SIGNAL ;
    SHAPE ABUTMENT ;
    PORT
      LAYER M5 ;
      RECT 17.856 0.000 17.880 0.024 ;
    END
  END w_mask_in[59]
  PIN w_mask_in[60]
    DIRECTION INPUT ;
    USE SIGNAL ;
    SHAPE ABUTMENT ;
    PORT
      LAYER M5 ;
      RECT 17.952 0.000 17.976 0.024 ;
    END
  END w_mask_in[60]
  PIN w_mask_in[61]
    DIRECTION INPUT ;
    USE SIGNAL ;
    SHAPE ABUTMENT ;
    PORT
      LAYER M5 ;
      RECT 18.048 0.000 18.072 0.024 ;
    END
  END w_mask_in[61]
  PIN w_mask_in[62]
    DIRECTION INPUT ;
    USE SIGNAL ;
    SHAPE ABUTMENT ;
    PORT
      LAYER M5 ;
      RECT 18.144 0.000 18.168 0.024 ;
    END
  END w_mask_in[62]
  PIN w_mask_in[63]
    DIRECTION INPUT ;
    USE SIGNAL ;
    SHAPE ABUTMENT ;
    PORT
      LAYER M5 ;
      RECT 18.240 0.000 18.264 0.024 ;
    END
  END w_mask_in[63]
  PIN w_mask_in[64]
    DIRECTION INPUT ;
    USE SIGNAL ;
    SHAPE ABUTMENT ;
    PORT
      LAYER M5 ;
      RECT 18.336 0.000 18.360 0.024 ;
    END
  END w_mask_in[64]
  PIN w_mask_in[65]
    DIRECTION INPUT ;
    USE SIGNAL ;
    SHAPE ABUTMENT ;
    PORT
      LAYER M5 ;
      RECT 18.432 0.000 18.456 0.024 ;
    END
  END w_mask_in[65]
  PIN w_mask_in[66]
    DIRECTION INPUT ;
    USE SIGNAL ;
    SHAPE ABUTMENT ;
    PORT
      LAYER M5 ;
      RECT 18.528 0.000 18.552 0.024 ;
    END
  END w_mask_in[66]
  PIN w_mask_in[67]
    DIRECTION INPUT ;
    USE SIGNAL ;
    SHAPE ABUTMENT ;
    PORT
      LAYER M5 ;
      RECT 18.624 0.000 18.648 0.024 ;
    END
  END w_mask_in[67]
  PIN w_mask_in[68]
    DIRECTION INPUT ;
    USE SIGNAL ;
    SHAPE ABUTMENT ;
    PORT
      LAYER M5 ;
      RECT 18.720 0.000 18.744 0.024 ;
    END
  END w_mask_in[68]
  PIN w_mask_in[69]
    DIRECTION INPUT ;
    USE SIGNAL ;
    SHAPE ABUTMENT ;
    PORT
      LAYER M5 ;
      RECT 18.816 0.000 18.840 0.024 ;
    END
  END w_mask_in[69]
  PIN w_mask_in[70]
    DIRECTION INPUT ;
    USE SIGNAL ;
    SHAPE ABUTMENT ;
    PORT
      LAYER M5 ;
      RECT 18.912 0.000 18.936 0.024 ;
    END
  END w_mask_in[70]
  PIN w_mask_in[71]
    DIRECTION INPUT ;
    USE SIGNAL ;
    SHAPE ABUTMENT ;
    PORT
      LAYER M5 ;
      RECT 19.008 0.000 19.032 0.024 ;
    END
  END w_mask_in[71]
  PIN w_mask_in[72]
    DIRECTION INPUT ;
    USE SIGNAL ;
    SHAPE ABUTMENT ;
    PORT
      LAYER M5 ;
      RECT 19.104 0.000 19.128 0.024 ;
    END
  END w_mask_in[72]
  PIN w_mask_in[73]
    DIRECTION INPUT ;
    USE SIGNAL ;
    SHAPE ABUTMENT ;
    PORT
      LAYER M5 ;
      RECT 19.200 0.000 19.224 0.024 ;
    END
  END w_mask_in[73]
  PIN w_mask_in[74]
    DIRECTION INPUT ;
    USE SIGNAL ;
    SHAPE ABUTMENT ;
    PORT
      LAYER M5 ;
      RECT 19.296 0.000 19.320 0.024 ;
    END
  END w_mask_in[74]
  PIN w_mask_in[75]
    DIRECTION INPUT ;
    USE SIGNAL ;
    SHAPE ABUTMENT ;
    PORT
      LAYER M5 ;
      RECT 19.392 0.000 19.416 0.024 ;
    END
  END w_mask_in[75]
  PIN w_mask_in[76]
    DIRECTION INPUT ;
    USE SIGNAL ;
    SHAPE ABUTMENT ;
    PORT
      LAYER M5 ;
      RECT 19.488 0.000 19.512 0.024 ;
    END
  END w_mask_in[76]
  PIN w_mask_in[77]
    DIRECTION INPUT ;
    USE SIGNAL ;
    SHAPE ABUTMENT ;
    PORT
      LAYER M5 ;
      RECT 19.584 0.000 19.608 0.024 ;
    END
  END w_mask_in[77]
  PIN w_mask_in[78]
    DIRECTION INPUT ;
    USE SIGNAL ;
    SHAPE ABUTMENT ;
    PORT
      LAYER M5 ;
      RECT 19.680 0.000 19.704 0.024 ;
    END
  END w_mask_in[78]
  PIN w_mask_in[79]
    DIRECTION INPUT ;
    USE SIGNAL ;
    SHAPE ABUTMENT ;
    PORT
      LAYER M5 ;
      RECT 19.776 0.000 19.800 0.024 ;
    END
  END w_mask_in[79]
  PIN w_mask_in[80]
    DIRECTION INPUT ;
    USE SIGNAL ;
    SHAPE ABUTMENT ;
    PORT
      LAYER M5 ;
      RECT 19.872 0.000 19.896 0.024 ;
    END
  END w_mask_in[80]
  PIN w_mask_in[81]
    DIRECTION INPUT ;
    USE SIGNAL ;
    SHAPE ABUTMENT ;
    PORT
      LAYER M5 ;
      RECT 19.968 0.000 19.992 0.024 ;
    END
  END w_mask_in[81]
  PIN w_mask_in[82]
    DIRECTION INPUT ;
    USE SIGNAL ;
    SHAPE ABUTMENT ;
    PORT
      LAYER M5 ;
      RECT 20.064 0.000 20.088 0.024 ;
    END
  END w_mask_in[82]
  PIN w_mask_in[83]
    DIRECTION INPUT ;
    USE SIGNAL ;
    SHAPE ABUTMENT ;
    PORT
      LAYER M5 ;
      RECT 20.160 0.000 20.184 0.024 ;
    END
  END w_mask_in[83]
  PIN w_mask_in[84]
    DIRECTION INPUT ;
    USE SIGNAL ;
    SHAPE ABUTMENT ;
    PORT
      LAYER M5 ;
      RECT 20.256 0.000 20.280 0.024 ;
    END
  END w_mask_in[84]
  PIN w_mask_in[85]
    DIRECTION INPUT ;
    USE SIGNAL ;
    SHAPE ABUTMENT ;
    PORT
      LAYER M5 ;
      RECT 20.352 0.000 20.376 0.024 ;
    END
  END w_mask_in[85]
  PIN w_mask_in[86]
    DIRECTION INPUT ;
    USE SIGNAL ;
    SHAPE ABUTMENT ;
    PORT
      LAYER M5 ;
      RECT 20.448 0.000 20.472 0.024 ;
    END
  END w_mask_in[86]
  PIN w_mask_in[87]
    DIRECTION INPUT ;
    USE SIGNAL ;
    SHAPE ABUTMENT ;
    PORT
      LAYER M5 ;
      RECT 20.544 0.000 20.568 0.024 ;
    END
  END w_mask_in[87]
  PIN w_mask_in[88]
    DIRECTION INPUT ;
    USE SIGNAL ;
    SHAPE ABUTMENT ;
    PORT
      LAYER M5 ;
      RECT 20.640 0.000 20.664 0.024 ;
    END
  END w_mask_in[88]
  PIN w_mask_in[89]
    DIRECTION INPUT ;
    USE SIGNAL ;
    SHAPE ABUTMENT ;
    PORT
      LAYER M5 ;
      RECT 20.736 0.000 20.760 0.024 ;
    END
  END w_mask_in[89]
  PIN w_mask_in[90]
    DIRECTION INPUT ;
    USE SIGNAL ;
    SHAPE ABUTMENT ;
    PORT
      LAYER M5 ;
      RECT 20.832 0.000 20.856 0.024 ;
    END
  END w_mask_in[90]
  PIN w_mask_in[91]
    DIRECTION INPUT ;
    USE SIGNAL ;
    SHAPE ABUTMENT ;
    PORT
      LAYER M5 ;
      RECT 20.928 0.000 20.952 0.024 ;
    END
  END w_mask_in[91]
  PIN w_mask_in[92]
    DIRECTION INPUT ;
    USE SIGNAL ;
    SHAPE ABUTMENT ;
    PORT
      LAYER M5 ;
      RECT 21.024 0.000 21.048 0.024 ;
    END
  END w_mask_in[92]
  PIN w_mask_in[93]
    DIRECTION INPUT ;
    USE SIGNAL ;
    SHAPE ABUTMENT ;
    PORT
      LAYER M5 ;
      RECT 21.120 0.000 21.144 0.024 ;
    END
  END w_mask_in[93]
  PIN w_mask_in[94]
    DIRECTION INPUT ;
    USE SIGNAL ;
    SHAPE ABUTMENT ;
    PORT
      LAYER M5 ;
      RECT 21.216 0.000 21.240 0.024 ;
    END
  END w_mask_in[94]
  PIN w_mask_in[95]
    DIRECTION INPUT ;
    USE SIGNAL ;
    SHAPE ABUTMENT ;
    PORT
      LAYER M5 ;
      RECT 21.312 0.000 21.336 0.024 ;
    END
  END w_mask_in[95]
  PIN w_mask_in[96]
    DIRECTION INPUT ;
    USE SIGNAL ;
    SHAPE ABUTMENT ;
    PORT
      LAYER M5 ;
      RECT 21.408 0.000 21.432 0.024 ;
    END
  END w_mask_in[96]
  PIN w_mask_in[97]
    DIRECTION INPUT ;
    USE SIGNAL ;
    SHAPE ABUTMENT ;
    PORT
      LAYER M5 ;
      RECT 21.504 0.000 21.528 0.024 ;
    END
  END w_mask_in[97]
  PIN w_mask_in[98]
    DIRECTION INPUT ;
    USE SIGNAL ;
    SHAPE ABUTMENT ;
    PORT
      LAYER M5 ;
      RECT 21.600 0.000 21.624 0.024 ;
    END
  END w_mask_in[98]
  PIN w_mask_in[99]
    DIRECTION INPUT ;
    USE SIGNAL ;
    SHAPE ABUTMENT ;
    PORT
      LAYER M5 ;
      RECT 21.696 0.000 21.720 0.024 ;
    END
  END w_mask_in[99]
  PIN w_mask_in[100]
    DIRECTION INPUT ;
    USE SIGNAL ;
    SHAPE ABUTMENT ;
    PORT
      LAYER M5 ;
      RECT 21.792 0.000 21.816 0.024 ;
    END
  END w_mask_in[100]
  PIN w_mask_in[101]
    DIRECTION INPUT ;
    USE SIGNAL ;
    SHAPE ABUTMENT ;
    PORT
      LAYER M5 ;
      RECT 21.888 0.000 21.912 0.024 ;
    END
  END w_mask_in[101]
  PIN w_mask_in[102]
    DIRECTION INPUT ;
    USE SIGNAL ;
    SHAPE ABUTMENT ;
    PORT
      LAYER M5 ;
      RECT 21.984 0.000 22.008 0.024 ;
    END
  END w_mask_in[102]
  PIN w_mask_in[103]
    DIRECTION INPUT ;
    USE SIGNAL ;
    SHAPE ABUTMENT ;
    PORT
      LAYER M5 ;
      RECT 22.080 0.000 22.104 0.024 ;
    END
  END w_mask_in[103]
  PIN w_mask_in[104]
    DIRECTION INPUT ;
    USE SIGNAL ;
    SHAPE ABUTMENT ;
    PORT
      LAYER M5 ;
      RECT 22.176 0.000 22.200 0.024 ;
    END
  END w_mask_in[104]
  PIN w_mask_in[105]
    DIRECTION INPUT ;
    USE SIGNAL ;
    SHAPE ABUTMENT ;
    PORT
      LAYER M5 ;
      RECT 22.272 0.000 22.296 0.024 ;
    END
  END w_mask_in[105]
  PIN w_mask_in[106]
    DIRECTION INPUT ;
    USE SIGNAL ;
    SHAPE ABUTMENT ;
    PORT
      LAYER M5 ;
      RECT 22.368 0.000 22.392 0.024 ;
    END
  END w_mask_in[106]
  PIN w_mask_in[107]
    DIRECTION INPUT ;
    USE SIGNAL ;
    SHAPE ABUTMENT ;
    PORT
      LAYER M5 ;
      RECT 22.464 0.000 22.488 0.024 ;
    END
  END w_mask_in[107]
  PIN w_mask_in[108]
    DIRECTION INPUT ;
    USE SIGNAL ;
    SHAPE ABUTMENT ;
    PORT
      LAYER M5 ;
      RECT 22.560 0.000 22.584 0.024 ;
    END
  END w_mask_in[108]
  PIN w_mask_in[109]
    DIRECTION INPUT ;
    USE SIGNAL ;
    SHAPE ABUTMENT ;
    PORT
      LAYER M5 ;
      RECT 22.656 0.000 22.680 0.024 ;
    END
  END w_mask_in[109]
  PIN w_mask_in[110]
    DIRECTION INPUT ;
    USE SIGNAL ;
    SHAPE ABUTMENT ;
    PORT
      LAYER M5 ;
      RECT 22.752 0.000 22.776 0.024 ;
    END
  END w_mask_in[110]
  PIN w_mask_in[111]
    DIRECTION INPUT ;
    USE SIGNAL ;
    SHAPE ABUTMENT ;
    PORT
      LAYER M5 ;
      RECT 22.848 0.000 22.872 0.024 ;
    END
  END w_mask_in[111]
  PIN w_mask_in[112]
    DIRECTION INPUT ;
    USE SIGNAL ;
    SHAPE ABUTMENT ;
    PORT
      LAYER M5 ;
      RECT 22.944 0.000 22.968 0.024 ;
    END
  END w_mask_in[112]
  PIN w_mask_in[113]
    DIRECTION INPUT ;
    USE SIGNAL ;
    SHAPE ABUTMENT ;
    PORT
      LAYER M5 ;
      RECT 23.040 0.000 23.064 0.024 ;
    END
  END w_mask_in[113]
  PIN w_mask_in[114]
    DIRECTION INPUT ;
    USE SIGNAL ;
    SHAPE ABUTMENT ;
    PORT
      LAYER M5 ;
      RECT 23.136 0.000 23.160 0.024 ;
    END
  END w_mask_in[114]
  PIN w_mask_in[115]
    DIRECTION INPUT ;
    USE SIGNAL ;
    SHAPE ABUTMENT ;
    PORT
      LAYER M5 ;
      RECT 23.232 0.000 23.256 0.024 ;
    END
  END w_mask_in[115]
  PIN w_mask_in[116]
    DIRECTION INPUT ;
    USE SIGNAL ;
    SHAPE ABUTMENT ;
    PORT
      LAYER M5 ;
      RECT 23.328 0.000 23.352 0.024 ;
    END
  END w_mask_in[116]
  PIN w_mask_in[117]
    DIRECTION INPUT ;
    USE SIGNAL ;
    SHAPE ABUTMENT ;
    PORT
      LAYER M5 ;
      RECT 23.424 0.000 23.448 0.024 ;
    END
  END w_mask_in[117]
  PIN w_mask_in[118]
    DIRECTION INPUT ;
    USE SIGNAL ;
    SHAPE ABUTMENT ;
    PORT
      LAYER M5 ;
      RECT 23.520 0.000 23.544 0.024 ;
    END
  END w_mask_in[118]
  PIN w_mask_in[119]
    DIRECTION INPUT ;
    USE SIGNAL ;
    SHAPE ABUTMENT ;
    PORT
      LAYER M5 ;
      RECT 23.616 0.000 23.640 0.024 ;
    END
  END w_mask_in[119]
  PIN w_mask_in[120]
    DIRECTION INPUT ;
    USE SIGNAL ;
    SHAPE ABUTMENT ;
    PORT
      LAYER M5 ;
      RECT 23.712 0.000 23.736 0.024 ;
    END
  END w_mask_in[120]
  PIN w_mask_in[121]
    DIRECTION INPUT ;
    USE SIGNAL ;
    SHAPE ABUTMENT ;
    PORT
      LAYER M5 ;
      RECT 23.808 0.000 23.832 0.024 ;
    END
  END w_mask_in[121]
  PIN w_mask_in[122]
    DIRECTION INPUT ;
    USE SIGNAL ;
    SHAPE ABUTMENT ;
    PORT
      LAYER M5 ;
      RECT 23.904 0.000 23.928 0.024 ;
    END
  END w_mask_in[122]
  PIN w_mask_in[123]
    DIRECTION INPUT ;
    USE SIGNAL ;
    SHAPE ABUTMENT ;
    PORT
      LAYER M5 ;
      RECT 24.000 0.000 24.024 0.024 ;
    END
  END w_mask_in[123]
  PIN w_mask_in[124]
    DIRECTION INPUT ;
    USE SIGNAL ;
    SHAPE ABUTMENT ;
    PORT
      LAYER M5 ;
      RECT 24.096 0.000 24.120 0.024 ;
    END
  END w_mask_in[124]
  PIN w_mask_in[125]
    DIRECTION INPUT ;
    USE SIGNAL ;
    SHAPE ABUTMENT ;
    PORT
      LAYER M5 ;
      RECT 24.192 0.000 24.216 0.024 ;
    END
  END w_mask_in[125]
  PIN w_mask_in[126]
    DIRECTION INPUT ;
    USE SIGNAL ;
    SHAPE ABUTMENT ;
    PORT
      LAYER M5 ;
      RECT 24.288 0.000 24.312 0.024 ;
    END
  END w_mask_in[126]
  PIN w_mask_in[127]
    DIRECTION INPUT ;
    USE SIGNAL ;
    SHAPE ABUTMENT ;
    PORT
      LAYER M5 ;
      RECT 24.384 0.000 24.408 0.024 ;
    END
  END w_mask_in[127]
  PIN w_mask_in[128]
    DIRECTION INPUT ;
    USE SIGNAL ;
    SHAPE ABUTMENT ;
    PORT
      LAYER M5 ;
      RECT 24.480 0.000 24.504 0.024 ;
    END
  END w_mask_in[128]
  PIN w_mask_in[129]
    DIRECTION INPUT ;
    USE SIGNAL ;
    SHAPE ABUTMENT ;
    PORT
      LAYER M5 ;
      RECT 24.576 0.000 24.600 0.024 ;
    END
  END w_mask_in[129]
  PIN w_mask_in[130]
    DIRECTION INPUT ;
    USE SIGNAL ;
    SHAPE ABUTMENT ;
    PORT
      LAYER M5 ;
      RECT 24.672 0.000 24.696 0.024 ;
    END
  END w_mask_in[130]
  PIN w_mask_in[131]
    DIRECTION INPUT ;
    USE SIGNAL ;
    SHAPE ABUTMENT ;
    PORT
      LAYER M5 ;
      RECT 24.768 0.000 24.792 0.024 ;
    END
  END w_mask_in[131]
  PIN w_mask_in[132]
    DIRECTION INPUT ;
    USE SIGNAL ;
    SHAPE ABUTMENT ;
    PORT
      LAYER M5 ;
      RECT 24.864 0.000 24.888 0.024 ;
    END
  END w_mask_in[132]
  PIN w_mask_in[133]
    DIRECTION INPUT ;
    USE SIGNAL ;
    SHAPE ABUTMENT ;
    PORT
      LAYER M5 ;
      RECT 24.960 0.000 24.984 0.024 ;
    END
  END w_mask_in[133]
  PIN w_mask_in[134]
    DIRECTION INPUT ;
    USE SIGNAL ;
    SHAPE ABUTMENT ;
    PORT
      LAYER M5 ;
      RECT 25.056 0.000 25.080 0.024 ;
    END
  END w_mask_in[134]
  PIN w_mask_in[135]
    DIRECTION INPUT ;
    USE SIGNAL ;
    SHAPE ABUTMENT ;
    PORT
      LAYER M5 ;
      RECT 25.152 0.000 25.176 0.024 ;
    END
  END w_mask_in[135]
  PIN w_mask_in[136]
    DIRECTION INPUT ;
    USE SIGNAL ;
    SHAPE ABUTMENT ;
    PORT
      LAYER M5 ;
      RECT 25.248 0.000 25.272 0.024 ;
    END
  END w_mask_in[136]
  PIN w_mask_in[137]
    DIRECTION INPUT ;
    USE SIGNAL ;
    SHAPE ABUTMENT ;
    PORT
      LAYER M5 ;
      RECT 25.344 0.000 25.368 0.024 ;
    END
  END w_mask_in[137]
  PIN w_mask_in[138]
    DIRECTION INPUT ;
    USE SIGNAL ;
    SHAPE ABUTMENT ;
    PORT
      LAYER M5 ;
      RECT 25.440 0.000 25.464 0.024 ;
    END
  END w_mask_in[138]
  PIN w_mask_in[139]
    DIRECTION INPUT ;
    USE SIGNAL ;
    SHAPE ABUTMENT ;
    PORT
      LAYER M5 ;
      RECT 25.536 0.000 25.560 0.024 ;
    END
  END w_mask_in[139]
  PIN w_mask_in[140]
    DIRECTION INPUT ;
    USE SIGNAL ;
    SHAPE ABUTMENT ;
    PORT
      LAYER M5 ;
      RECT 25.632 0.000 25.656 0.024 ;
    END
  END w_mask_in[140]
  PIN w_mask_in[141]
    DIRECTION INPUT ;
    USE SIGNAL ;
    SHAPE ABUTMENT ;
    PORT
      LAYER M5 ;
      RECT 25.728 0.000 25.752 0.024 ;
    END
  END w_mask_in[141]
  PIN w_mask_in[142]
    DIRECTION INPUT ;
    USE SIGNAL ;
    SHAPE ABUTMENT ;
    PORT
      LAYER M5 ;
      RECT 25.824 0.000 25.848 0.024 ;
    END
  END w_mask_in[142]
  PIN w_mask_in[143]
    DIRECTION INPUT ;
    USE SIGNAL ;
    SHAPE ABUTMENT ;
    PORT
      LAYER M5 ;
      RECT 25.920 0.000 25.944 0.024 ;
    END
  END w_mask_in[143]
  PIN w_mask_in[144]
    DIRECTION INPUT ;
    USE SIGNAL ;
    SHAPE ABUTMENT ;
    PORT
      LAYER M5 ;
      RECT 26.016 0.000 26.040 0.024 ;
    END
  END w_mask_in[144]
  PIN w_mask_in[145]
    DIRECTION INPUT ;
    USE SIGNAL ;
    SHAPE ABUTMENT ;
    PORT
      LAYER M5 ;
      RECT 26.112 0.000 26.136 0.024 ;
    END
  END w_mask_in[145]
  PIN w_mask_in[146]
    DIRECTION INPUT ;
    USE SIGNAL ;
    SHAPE ABUTMENT ;
    PORT
      LAYER M5 ;
      RECT 26.208 0.000 26.232 0.024 ;
    END
  END w_mask_in[146]
  PIN w_mask_in[147]
    DIRECTION INPUT ;
    USE SIGNAL ;
    SHAPE ABUTMENT ;
    PORT
      LAYER M5 ;
      RECT 26.304 0.000 26.328 0.024 ;
    END
  END w_mask_in[147]
  PIN w_mask_in[148]
    DIRECTION INPUT ;
    USE SIGNAL ;
    SHAPE ABUTMENT ;
    PORT
      LAYER M5 ;
      RECT 26.400 0.000 26.424 0.024 ;
    END
  END w_mask_in[148]
  PIN w_mask_in[149]
    DIRECTION INPUT ;
    USE SIGNAL ;
    SHAPE ABUTMENT ;
    PORT
      LAYER M5 ;
      RECT 26.496 0.000 26.520 0.024 ;
    END
  END w_mask_in[149]
  PIN w_mask_in[150]
    DIRECTION INPUT ;
    USE SIGNAL ;
    SHAPE ABUTMENT ;
    PORT
      LAYER M5 ;
      RECT 26.592 0.000 26.616 0.024 ;
    END
  END w_mask_in[150]
  PIN w_mask_in[151]
    DIRECTION INPUT ;
    USE SIGNAL ;
    SHAPE ABUTMENT ;
    PORT
      LAYER M5 ;
      RECT 26.688 0.000 26.712 0.024 ;
    END
  END w_mask_in[151]
  PIN w_mask_in[152]
    DIRECTION INPUT ;
    USE SIGNAL ;
    SHAPE ABUTMENT ;
    PORT
      LAYER M5 ;
      RECT 26.784 0.000 26.808 0.024 ;
    END
  END w_mask_in[152]
  PIN w_mask_in[153]
    DIRECTION INPUT ;
    USE SIGNAL ;
    SHAPE ABUTMENT ;
    PORT
      LAYER M5 ;
      RECT 26.880 0.000 26.904 0.024 ;
    END
  END w_mask_in[153]
  PIN w_mask_in[154]
    DIRECTION INPUT ;
    USE SIGNAL ;
    SHAPE ABUTMENT ;
    PORT
      LAYER M5 ;
      RECT 26.976 0.000 27.000 0.024 ;
    END
  END w_mask_in[154]
  PIN w_mask_in[155]
    DIRECTION INPUT ;
    USE SIGNAL ;
    SHAPE ABUTMENT ;
    PORT
      LAYER M5 ;
      RECT 27.072 0.000 27.096 0.024 ;
    END
  END w_mask_in[155]
  PIN w_mask_in[156]
    DIRECTION INPUT ;
    USE SIGNAL ;
    SHAPE ABUTMENT ;
    PORT
      LAYER M5 ;
      RECT 27.168 0.000 27.192 0.024 ;
    END
  END w_mask_in[156]
  PIN w_mask_in[157]
    DIRECTION INPUT ;
    USE SIGNAL ;
    SHAPE ABUTMENT ;
    PORT
      LAYER M5 ;
      RECT 27.264 0.000 27.288 0.024 ;
    END
  END w_mask_in[157]
  PIN w_mask_in[158]
    DIRECTION INPUT ;
    USE SIGNAL ;
    SHAPE ABUTMENT ;
    PORT
      LAYER M5 ;
      RECT 27.360 0.000 27.384 0.024 ;
    END
  END w_mask_in[158]
  PIN w_mask_in[159]
    DIRECTION INPUT ;
    USE SIGNAL ;
    SHAPE ABUTMENT ;
    PORT
      LAYER M5 ;
      RECT 27.456 0.000 27.480 0.024 ;
    END
  END w_mask_in[159]
  PIN w_mask_in[160]
    DIRECTION INPUT ;
    USE SIGNAL ;
    SHAPE ABUTMENT ;
    PORT
      LAYER M5 ;
      RECT 27.552 0.000 27.576 0.024 ;
    END
  END w_mask_in[160]
  PIN w_mask_in[161]
    DIRECTION INPUT ;
    USE SIGNAL ;
    SHAPE ABUTMENT ;
    PORT
      LAYER M5 ;
      RECT 27.648 0.000 27.672 0.024 ;
    END
  END w_mask_in[161]
  PIN w_mask_in[162]
    DIRECTION INPUT ;
    USE SIGNAL ;
    SHAPE ABUTMENT ;
    PORT
      LAYER M5 ;
      RECT 27.744 0.000 27.768 0.024 ;
    END
  END w_mask_in[162]
  PIN w_mask_in[163]
    DIRECTION INPUT ;
    USE SIGNAL ;
    SHAPE ABUTMENT ;
    PORT
      LAYER M5 ;
      RECT 27.840 0.000 27.864 0.024 ;
    END
  END w_mask_in[163]
  PIN w_mask_in[164]
    DIRECTION INPUT ;
    USE SIGNAL ;
    SHAPE ABUTMENT ;
    PORT
      LAYER M5 ;
      RECT 27.936 0.000 27.960 0.024 ;
    END
  END w_mask_in[164]
  PIN w_mask_in[165]
    DIRECTION INPUT ;
    USE SIGNAL ;
    SHAPE ABUTMENT ;
    PORT
      LAYER M5 ;
      RECT 28.032 0.000 28.056 0.024 ;
    END
  END w_mask_in[165]
  PIN w_mask_in[166]
    DIRECTION INPUT ;
    USE SIGNAL ;
    SHAPE ABUTMENT ;
    PORT
      LAYER M5 ;
      RECT 28.128 0.000 28.152 0.024 ;
    END
  END w_mask_in[166]
  PIN w_mask_in[167]
    DIRECTION INPUT ;
    USE SIGNAL ;
    SHAPE ABUTMENT ;
    PORT
      LAYER M5 ;
      RECT 28.224 0.000 28.248 0.024 ;
    END
  END w_mask_in[167]
  PIN w_mask_in[168]
    DIRECTION INPUT ;
    USE SIGNAL ;
    SHAPE ABUTMENT ;
    PORT
      LAYER M5 ;
      RECT 28.320 0.000 28.344 0.024 ;
    END
  END w_mask_in[168]
  PIN w_mask_in[169]
    DIRECTION INPUT ;
    USE SIGNAL ;
    SHAPE ABUTMENT ;
    PORT
      LAYER M5 ;
      RECT 28.416 0.000 28.440 0.024 ;
    END
  END w_mask_in[169]
  PIN w_mask_in[170]
    DIRECTION INPUT ;
    USE SIGNAL ;
    SHAPE ABUTMENT ;
    PORT
      LAYER M5 ;
      RECT 28.512 0.000 28.536 0.024 ;
    END
  END w_mask_in[170]
  PIN w_mask_in[171]
    DIRECTION INPUT ;
    USE SIGNAL ;
    SHAPE ABUTMENT ;
    PORT
      LAYER M5 ;
      RECT 28.608 0.000 28.632 0.024 ;
    END
  END w_mask_in[171]
  PIN w_mask_in[172]
    DIRECTION INPUT ;
    USE SIGNAL ;
    SHAPE ABUTMENT ;
    PORT
      LAYER M5 ;
      RECT 28.704 0.000 28.728 0.024 ;
    END
  END w_mask_in[172]
  PIN w_mask_in[173]
    DIRECTION INPUT ;
    USE SIGNAL ;
    SHAPE ABUTMENT ;
    PORT
      LAYER M5 ;
      RECT 28.800 0.000 28.824 0.024 ;
    END
  END w_mask_in[173]
  PIN w_mask_in[174]
    DIRECTION INPUT ;
    USE SIGNAL ;
    SHAPE ABUTMENT ;
    PORT
      LAYER M5 ;
      RECT 28.896 0.000 28.920 0.024 ;
    END
  END w_mask_in[174]
  PIN w_mask_in[175]
    DIRECTION INPUT ;
    USE SIGNAL ;
    SHAPE ABUTMENT ;
    PORT
      LAYER M5 ;
      RECT 28.992 0.000 29.016 0.024 ;
    END
  END w_mask_in[175]
  PIN w_mask_in[176]
    DIRECTION INPUT ;
    USE SIGNAL ;
    SHAPE ABUTMENT ;
    PORT
      LAYER M5 ;
      RECT 29.088 0.000 29.112 0.024 ;
    END
  END w_mask_in[176]
  PIN w_mask_in[177]
    DIRECTION INPUT ;
    USE SIGNAL ;
    SHAPE ABUTMENT ;
    PORT
      LAYER M5 ;
      RECT 29.184 0.000 29.208 0.024 ;
    END
  END w_mask_in[177]
  PIN w_mask_in[178]
    DIRECTION INPUT ;
    USE SIGNAL ;
    SHAPE ABUTMENT ;
    PORT
      LAYER M5 ;
      RECT 29.280 0.000 29.304 0.024 ;
    END
  END w_mask_in[178]
  PIN w_mask_in[179]
    DIRECTION INPUT ;
    USE SIGNAL ;
    SHAPE ABUTMENT ;
    PORT
      LAYER M5 ;
      RECT 29.376 0.000 29.400 0.024 ;
    END
  END w_mask_in[179]
  PIN w_mask_in[180]
    DIRECTION INPUT ;
    USE SIGNAL ;
    SHAPE ABUTMENT ;
    PORT
      LAYER M5 ;
      RECT 29.472 0.000 29.496 0.024 ;
    END
  END w_mask_in[180]
  PIN w_mask_in[181]
    DIRECTION INPUT ;
    USE SIGNAL ;
    SHAPE ABUTMENT ;
    PORT
      LAYER M5 ;
      RECT 29.568 0.000 29.592 0.024 ;
    END
  END w_mask_in[181]
  PIN w_mask_in[182]
    DIRECTION INPUT ;
    USE SIGNAL ;
    SHAPE ABUTMENT ;
    PORT
      LAYER M5 ;
      RECT 29.664 0.000 29.688 0.024 ;
    END
  END w_mask_in[182]
  PIN w_mask_in[183]
    DIRECTION INPUT ;
    USE SIGNAL ;
    SHAPE ABUTMENT ;
    PORT
      LAYER M5 ;
      RECT 29.760 0.000 29.784 0.024 ;
    END
  END w_mask_in[183]
  PIN w_mask_in[184]
    DIRECTION INPUT ;
    USE SIGNAL ;
    SHAPE ABUTMENT ;
    PORT
      LAYER M5 ;
      RECT 29.856 0.000 29.880 0.024 ;
    END
  END w_mask_in[184]
  PIN w_mask_in[185]
    DIRECTION INPUT ;
    USE SIGNAL ;
    SHAPE ABUTMENT ;
    PORT
      LAYER M5 ;
      RECT 29.952 0.000 29.976 0.024 ;
    END
  END w_mask_in[185]
  PIN w_mask_in[186]
    DIRECTION INPUT ;
    USE SIGNAL ;
    SHAPE ABUTMENT ;
    PORT
      LAYER M5 ;
      RECT 30.048 0.000 30.072 0.024 ;
    END
  END w_mask_in[186]
  PIN w_mask_in[187]
    DIRECTION INPUT ;
    USE SIGNAL ;
    SHAPE ABUTMENT ;
    PORT
      LAYER M5 ;
      RECT 30.144 0.000 30.168 0.024 ;
    END
  END w_mask_in[187]
  PIN w_mask_in[188]
    DIRECTION INPUT ;
    USE SIGNAL ;
    SHAPE ABUTMENT ;
    PORT
      LAYER M5 ;
      RECT 30.240 0.000 30.264 0.024 ;
    END
  END w_mask_in[188]
  PIN w_mask_in[189]
    DIRECTION INPUT ;
    USE SIGNAL ;
    SHAPE ABUTMENT ;
    PORT
      LAYER M5 ;
      RECT 30.336 0.000 30.360 0.024 ;
    END
  END w_mask_in[189]
  PIN w_mask_in[190]
    DIRECTION INPUT ;
    USE SIGNAL ;
    SHAPE ABUTMENT ;
    PORT
      LAYER M5 ;
      RECT 30.432 0.000 30.456 0.024 ;
    END
  END w_mask_in[190]
  PIN w_mask_in[191]
    DIRECTION INPUT ;
    USE SIGNAL ;
    SHAPE ABUTMENT ;
    PORT
      LAYER M5 ;
      RECT 30.528 0.000 30.552 0.024 ;
    END
  END w_mask_in[191]
  PIN w_mask_in[192]
    DIRECTION INPUT ;
    USE SIGNAL ;
    SHAPE ABUTMENT ;
    PORT
      LAYER M5 ;
      RECT 30.624 0.000 30.648 0.024 ;
    END
  END w_mask_in[192]
  PIN w_mask_in[193]
    DIRECTION INPUT ;
    USE SIGNAL ;
    SHAPE ABUTMENT ;
    PORT
      LAYER M5 ;
      RECT 30.720 0.000 30.744 0.024 ;
    END
  END w_mask_in[193]
  PIN w_mask_in[194]
    DIRECTION INPUT ;
    USE SIGNAL ;
    SHAPE ABUTMENT ;
    PORT
      LAYER M5 ;
      RECT 30.816 0.000 30.840 0.024 ;
    END
  END w_mask_in[194]
  PIN w_mask_in[195]
    DIRECTION INPUT ;
    USE SIGNAL ;
    SHAPE ABUTMENT ;
    PORT
      LAYER M5 ;
      RECT 30.912 0.000 30.936 0.024 ;
    END
  END w_mask_in[195]
  PIN w_mask_in[196]
    DIRECTION INPUT ;
    USE SIGNAL ;
    SHAPE ABUTMENT ;
    PORT
      LAYER M5 ;
      RECT 31.008 0.000 31.032 0.024 ;
    END
  END w_mask_in[196]
  PIN w_mask_in[197]
    DIRECTION INPUT ;
    USE SIGNAL ;
    SHAPE ABUTMENT ;
    PORT
      LAYER M5 ;
      RECT 31.104 0.000 31.128 0.024 ;
    END
  END w_mask_in[197]
  PIN w_mask_in[198]
    DIRECTION INPUT ;
    USE SIGNAL ;
    SHAPE ABUTMENT ;
    PORT
      LAYER M5 ;
      RECT 31.200 0.000 31.224 0.024 ;
    END
  END w_mask_in[198]
  PIN w_mask_in[199]
    DIRECTION INPUT ;
    USE SIGNAL ;
    SHAPE ABUTMENT ;
    PORT
      LAYER M5 ;
      RECT 31.296 0.000 31.320 0.024 ;
    END
  END w_mask_in[199]
  PIN w_mask_in[200]
    DIRECTION INPUT ;
    USE SIGNAL ;
    SHAPE ABUTMENT ;
    PORT
      LAYER M5 ;
      RECT 31.392 0.000 31.416 0.024 ;
    END
  END w_mask_in[200]
  PIN w_mask_in[201]
    DIRECTION INPUT ;
    USE SIGNAL ;
    SHAPE ABUTMENT ;
    PORT
      LAYER M5 ;
      RECT 31.488 0.000 31.512 0.024 ;
    END
  END w_mask_in[201]
  PIN w_mask_in[202]
    DIRECTION INPUT ;
    USE SIGNAL ;
    SHAPE ABUTMENT ;
    PORT
      LAYER M5 ;
      RECT 31.584 0.000 31.608 0.024 ;
    END
  END w_mask_in[202]
  PIN w_mask_in[203]
    DIRECTION INPUT ;
    USE SIGNAL ;
    SHAPE ABUTMENT ;
    PORT
      LAYER M5 ;
      RECT 31.680 0.000 31.704 0.024 ;
    END
  END w_mask_in[203]
  PIN w_mask_in[204]
    DIRECTION INPUT ;
    USE SIGNAL ;
    SHAPE ABUTMENT ;
    PORT
      LAYER M5 ;
      RECT 31.776 0.000 31.800 0.024 ;
    END
  END w_mask_in[204]
  PIN w_mask_in[205]
    DIRECTION INPUT ;
    USE SIGNAL ;
    SHAPE ABUTMENT ;
    PORT
      LAYER M5 ;
      RECT 31.872 0.000 31.896 0.024 ;
    END
  END w_mask_in[205]
  PIN w_mask_in[206]
    DIRECTION INPUT ;
    USE SIGNAL ;
    SHAPE ABUTMENT ;
    PORT
      LAYER M5 ;
      RECT 31.968 0.000 31.992 0.024 ;
    END
  END w_mask_in[206]
  PIN w_mask_in[207]
    DIRECTION INPUT ;
    USE SIGNAL ;
    SHAPE ABUTMENT ;
    PORT
      LAYER M5 ;
      RECT 32.064 0.000 32.088 0.024 ;
    END
  END w_mask_in[207]
  PIN w_mask_in[208]
    DIRECTION INPUT ;
    USE SIGNAL ;
    SHAPE ABUTMENT ;
    PORT
      LAYER M5 ;
      RECT 32.160 0.000 32.184 0.024 ;
    END
  END w_mask_in[208]
  PIN w_mask_in[209]
    DIRECTION INPUT ;
    USE SIGNAL ;
    SHAPE ABUTMENT ;
    PORT
      LAYER M5 ;
      RECT 32.256 0.000 32.280 0.024 ;
    END
  END w_mask_in[209]
  PIN w_mask_in[210]
    DIRECTION INPUT ;
    USE SIGNAL ;
    SHAPE ABUTMENT ;
    PORT
      LAYER M5 ;
      RECT 32.352 0.000 32.376 0.024 ;
    END
  END w_mask_in[210]
  PIN w_mask_in[211]
    DIRECTION INPUT ;
    USE SIGNAL ;
    SHAPE ABUTMENT ;
    PORT
      LAYER M5 ;
      RECT 32.448 0.000 32.472 0.024 ;
    END
  END w_mask_in[211]
  PIN w_mask_in[212]
    DIRECTION INPUT ;
    USE SIGNAL ;
    SHAPE ABUTMENT ;
    PORT
      LAYER M5 ;
      RECT 32.544 0.000 32.568 0.024 ;
    END
  END w_mask_in[212]
  PIN w_mask_in[213]
    DIRECTION INPUT ;
    USE SIGNAL ;
    SHAPE ABUTMENT ;
    PORT
      LAYER M5 ;
      RECT 32.640 0.000 32.664 0.024 ;
    END
  END w_mask_in[213]
  PIN w_mask_in[214]
    DIRECTION INPUT ;
    USE SIGNAL ;
    SHAPE ABUTMENT ;
    PORT
      LAYER M5 ;
      RECT 32.736 0.000 32.760 0.024 ;
    END
  END w_mask_in[214]
  PIN w_mask_in[215]
    DIRECTION INPUT ;
    USE SIGNAL ;
    SHAPE ABUTMENT ;
    PORT
      LAYER M5 ;
      RECT 32.832 0.000 32.856 0.024 ;
    END
  END w_mask_in[215]
  PIN w_mask_in[216]
    DIRECTION INPUT ;
    USE SIGNAL ;
    SHAPE ABUTMENT ;
    PORT
      LAYER M5 ;
      RECT 32.928 0.000 32.952 0.024 ;
    END
  END w_mask_in[216]
  PIN w_mask_in[217]
    DIRECTION INPUT ;
    USE SIGNAL ;
    SHAPE ABUTMENT ;
    PORT
      LAYER M5 ;
      RECT 33.024 0.000 33.048 0.024 ;
    END
  END w_mask_in[217]
  PIN w_mask_in[218]
    DIRECTION INPUT ;
    USE SIGNAL ;
    SHAPE ABUTMENT ;
    PORT
      LAYER M5 ;
      RECT 33.120 0.000 33.144 0.024 ;
    END
  END w_mask_in[218]
  PIN w_mask_in[219]
    DIRECTION INPUT ;
    USE SIGNAL ;
    SHAPE ABUTMENT ;
    PORT
      LAYER M5 ;
      RECT 33.216 0.000 33.240 0.024 ;
    END
  END w_mask_in[219]
  PIN w_mask_in[220]
    DIRECTION INPUT ;
    USE SIGNAL ;
    SHAPE ABUTMENT ;
    PORT
      LAYER M5 ;
      RECT 33.312 0.000 33.336 0.024 ;
    END
  END w_mask_in[220]
  PIN w_mask_in[221]
    DIRECTION INPUT ;
    USE SIGNAL ;
    SHAPE ABUTMENT ;
    PORT
      LAYER M5 ;
      RECT 33.408 0.000 33.432 0.024 ;
    END
  END w_mask_in[221]
  PIN w_mask_in[222]
    DIRECTION INPUT ;
    USE SIGNAL ;
    SHAPE ABUTMENT ;
    PORT
      LAYER M5 ;
      RECT 33.504 0.000 33.528 0.024 ;
    END
  END w_mask_in[222]
  PIN w_mask_in[223]
    DIRECTION INPUT ;
    USE SIGNAL ;
    SHAPE ABUTMENT ;
    PORT
      LAYER M5 ;
      RECT 33.600 0.000 33.624 0.024 ;
    END
  END w_mask_in[223]
  PIN w_mask_in[224]
    DIRECTION INPUT ;
    USE SIGNAL ;
    SHAPE ABUTMENT ;
    PORT
      LAYER M5 ;
      RECT 33.696 0.000 33.720 0.024 ;
    END
  END w_mask_in[224]
  PIN w_mask_in[225]
    DIRECTION INPUT ;
    USE SIGNAL ;
    SHAPE ABUTMENT ;
    PORT
      LAYER M5 ;
      RECT 33.792 0.000 33.816 0.024 ;
    END
  END w_mask_in[225]
  PIN w_mask_in[226]
    DIRECTION INPUT ;
    USE SIGNAL ;
    SHAPE ABUTMENT ;
    PORT
      LAYER M5 ;
      RECT 33.888 0.000 33.912 0.024 ;
    END
  END w_mask_in[226]
  PIN w_mask_in[227]
    DIRECTION INPUT ;
    USE SIGNAL ;
    SHAPE ABUTMENT ;
    PORT
      LAYER M5 ;
      RECT 33.984 0.000 34.008 0.024 ;
    END
  END w_mask_in[227]
  PIN w_mask_in[228]
    DIRECTION INPUT ;
    USE SIGNAL ;
    SHAPE ABUTMENT ;
    PORT
      LAYER M5 ;
      RECT 34.080 0.000 34.104 0.024 ;
    END
  END w_mask_in[228]
  PIN w_mask_in[229]
    DIRECTION INPUT ;
    USE SIGNAL ;
    SHAPE ABUTMENT ;
    PORT
      LAYER M5 ;
      RECT 34.176 0.000 34.200 0.024 ;
    END
  END w_mask_in[229]
  PIN w_mask_in[230]
    DIRECTION INPUT ;
    USE SIGNAL ;
    SHAPE ABUTMENT ;
    PORT
      LAYER M5 ;
      RECT 34.272 0.000 34.296 0.024 ;
    END
  END w_mask_in[230]
  PIN w_mask_in[231]
    DIRECTION INPUT ;
    USE SIGNAL ;
    SHAPE ABUTMENT ;
    PORT
      LAYER M5 ;
      RECT 34.368 0.000 34.392 0.024 ;
    END
  END w_mask_in[231]
  PIN w_mask_in[232]
    DIRECTION INPUT ;
    USE SIGNAL ;
    SHAPE ABUTMENT ;
    PORT
      LAYER M5 ;
      RECT 34.464 0.000 34.488 0.024 ;
    END
  END w_mask_in[232]
  PIN w_mask_in[233]
    DIRECTION INPUT ;
    USE SIGNAL ;
    SHAPE ABUTMENT ;
    PORT
      LAYER M5 ;
      RECT 34.560 0.000 34.584 0.024 ;
    END
  END w_mask_in[233]
  PIN w_mask_in[234]
    DIRECTION INPUT ;
    USE SIGNAL ;
    SHAPE ABUTMENT ;
    PORT
      LAYER M5 ;
      RECT 34.656 0.000 34.680 0.024 ;
    END
  END w_mask_in[234]
  PIN w_mask_in[235]
    DIRECTION INPUT ;
    USE SIGNAL ;
    SHAPE ABUTMENT ;
    PORT
      LAYER M5 ;
      RECT 34.752 0.000 34.776 0.024 ;
    END
  END w_mask_in[235]
  PIN w_mask_in[236]
    DIRECTION INPUT ;
    USE SIGNAL ;
    SHAPE ABUTMENT ;
    PORT
      LAYER M5 ;
      RECT 34.848 0.000 34.872 0.024 ;
    END
  END w_mask_in[236]
  PIN w_mask_in[237]
    DIRECTION INPUT ;
    USE SIGNAL ;
    SHAPE ABUTMENT ;
    PORT
      LAYER M5 ;
      RECT 34.944 0.000 34.968 0.024 ;
    END
  END w_mask_in[237]
  PIN w_mask_in[238]
    DIRECTION INPUT ;
    USE SIGNAL ;
    SHAPE ABUTMENT ;
    PORT
      LAYER M5 ;
      RECT 35.040 0.000 35.064 0.024 ;
    END
  END w_mask_in[238]
  PIN w_mask_in[239]
    DIRECTION INPUT ;
    USE SIGNAL ;
    SHAPE ABUTMENT ;
    PORT
      LAYER M5 ;
      RECT 35.136 0.000 35.160 0.024 ;
    END
  END w_mask_in[239]
  PIN w_mask_in[240]
    DIRECTION INPUT ;
    USE SIGNAL ;
    SHAPE ABUTMENT ;
    PORT
      LAYER M5 ;
      RECT 35.232 0.000 35.256 0.024 ;
    END
  END w_mask_in[240]
  PIN w_mask_in[241]
    DIRECTION INPUT ;
    USE SIGNAL ;
    SHAPE ABUTMENT ;
    PORT
      LAYER M5 ;
      RECT 35.328 0.000 35.352 0.024 ;
    END
  END w_mask_in[241]
  PIN w_mask_in[242]
    DIRECTION INPUT ;
    USE SIGNAL ;
    SHAPE ABUTMENT ;
    PORT
      LAYER M5 ;
      RECT 35.424 0.000 35.448 0.024 ;
    END
  END w_mask_in[242]
  PIN w_mask_in[243]
    DIRECTION INPUT ;
    USE SIGNAL ;
    SHAPE ABUTMENT ;
    PORT
      LAYER M5 ;
      RECT 35.520 0.000 35.544 0.024 ;
    END
  END w_mask_in[243]
  PIN w_mask_in[244]
    DIRECTION INPUT ;
    USE SIGNAL ;
    SHAPE ABUTMENT ;
    PORT
      LAYER M5 ;
      RECT 35.616 0.000 35.640 0.024 ;
    END
  END w_mask_in[244]
  PIN w_mask_in[245]
    DIRECTION INPUT ;
    USE SIGNAL ;
    SHAPE ABUTMENT ;
    PORT
      LAYER M5 ;
      RECT 35.712 0.000 35.736 0.024 ;
    END
  END w_mask_in[245]
  PIN w_mask_in[246]
    DIRECTION INPUT ;
    USE SIGNAL ;
    SHAPE ABUTMENT ;
    PORT
      LAYER M5 ;
      RECT 35.808 0.000 35.832 0.024 ;
    END
  END w_mask_in[246]
  PIN w_mask_in[247]
    DIRECTION INPUT ;
    USE SIGNAL ;
    SHAPE ABUTMENT ;
    PORT
      LAYER M5 ;
      RECT 35.904 0.000 35.928 0.024 ;
    END
  END w_mask_in[247]
  PIN w_mask_in[248]
    DIRECTION INPUT ;
    USE SIGNAL ;
    SHAPE ABUTMENT ;
    PORT
      LAYER M5 ;
      RECT 36.000 0.000 36.024 0.024 ;
    END
  END w_mask_in[248]
  PIN w_mask_in[249]
    DIRECTION INPUT ;
    USE SIGNAL ;
    SHAPE ABUTMENT ;
    PORT
      LAYER M5 ;
      RECT 36.096 0.000 36.120 0.024 ;
    END
  END w_mask_in[249]
  PIN w_mask_in[250]
    DIRECTION INPUT ;
    USE SIGNAL ;
    SHAPE ABUTMENT ;
    PORT
      LAYER M5 ;
      RECT 36.192 0.000 36.216 0.024 ;
    END
  END w_mask_in[250]
  PIN w_mask_in[251]
    DIRECTION INPUT ;
    USE SIGNAL ;
    SHAPE ABUTMENT ;
    PORT
      LAYER M5 ;
      RECT 36.288 0.000 36.312 0.024 ;
    END
  END w_mask_in[251]
  PIN w_mask_in[252]
    DIRECTION INPUT ;
    USE SIGNAL ;
    SHAPE ABUTMENT ;
    PORT
      LAYER M5 ;
      RECT 36.384 0.000 36.408 0.024 ;
    END
  END w_mask_in[252]
  PIN w_mask_in[253]
    DIRECTION INPUT ;
    USE SIGNAL ;
    SHAPE ABUTMENT ;
    PORT
      LAYER M5 ;
      RECT 36.480 0.000 36.504 0.024 ;
    END
  END w_mask_in[253]
  PIN w_mask_in[254]
    DIRECTION INPUT ;
    USE SIGNAL ;
    SHAPE ABUTMENT ;
    PORT
      LAYER M5 ;
      RECT 36.576 0.000 36.600 0.024 ;
    END
  END w_mask_in[254]
  PIN w_mask_in[255]
    DIRECTION INPUT ;
    USE SIGNAL ;
    SHAPE ABUTMENT ;
    PORT
      LAYER M5 ;
      RECT 36.672 0.000 36.696 0.024 ;
    END
  END w_mask_in[255]
  PIN rr_en[0]
    DIRECTION INPUT ;
    USE SIGNAL ;
    SHAPE ABUTMENT ;
    PORT
      LAYER M5 ;
      RECT 36.768 0.000 36.792 0.024 ;
    END
  END rr_en[0]
  PIN rr_en[1]
    DIRECTION INPUT ;
    USE SIGNAL ;
    SHAPE ABUTMENT ;
    PORT
      LAYER M5 ;
      RECT 36.864 0.000 36.888 0.024 ;
    END
  END rr_en[1]
  PIN rr_addr[0]
    DIRECTION INPUT ;
    USE SIGNAL ;
    SHAPE ABUTMENT ;
    PORT
      LAYER M5 ;
      RECT 36.960 0.000 36.984 0.024 ;
    END
  END rr_addr[0]
  PIN rr_addr[1]
    DIRECTION INPUT ;
    USE SIGNAL ;
    SHAPE ABUTMENT ;
    PORT
      LAYER M5 ;
      RECT 37.056 0.000 37.080 0.024 ;
    END
  END rr_addr[1]
  PIN rr_addr[2]
    DIRECTION INPUT ;
    USE SIGNAL ;
    SHAPE ABUTMENT ;
    PORT
      LAYER M5 ;
      RECT 37.152 0.000 37.176 0.024 ;
    END
  END rr_addr[2]
  PIN rr_addr[3]
    DIRECTION INPUT ;
    USE SIGNAL ;
    SHAPE ABUTMENT ;
    PORT
      LAYER M5 ;
      RECT 37.248 0.000 37.272 0.024 ;
    END
  END rr_addr[3]
  PIN rr_addr[4]
    DIRECTION INPUT ;
    USE SIGNAL ;
    SHAPE ABUTMENT ;
    PORT
      LAYER M5 ;
      RECT 37.344 0.000 37.368 0.024 ;
    END
  END rr_addr[4]
  PIN rr_addr[5]
    DIRECTION INPUT ;
    USE SIGNAL ;
    SHAPE ABUTMENT ;
    PORT
      LAYER M5 ;
      RECT 37.440 0.000 37.464 0.024 ;
    END
  END rr_addr[5]
  PIN rr_addr[6]
    DIRECTION INPUT ;
    USE SIGNAL ;
    SHAPE ABUTMENT ;
    PORT
      LAYER M5 ;
      RECT 37.536 0.000 37.560 0.024 ;
    END
  END rr_addr[6]
  PIN rr_addr[7]
    DIRECTION INPUT ;
    USE SIGNAL ;
    SHAPE ABUTMENT ;
    PORT
      LAYER M5 ;
      RECT 37.632 0.000 37.656 0.024 ;
    END
  END rr_addr[7]
  PIN rr_addr[8]
    DIRECTION INPUT ;
    USE SIGNAL ;
    SHAPE ABUTMENT ;
    PORT
      LAYER M5 ;
      RECT 37.728 0.000 37.752 0.024 ;
    END
  END rr_addr[8]
  PIN rr_addr[9]
    DIRECTION INPUT ;
    USE SIGNAL ;
    SHAPE ABUTMENT ;
    PORT
      LAYER M5 ;
      RECT 37.824 0.000 37.848 0.024 ;
    END
  END rr_addr[9]
  PIN rr_addr[10]
    DIRECTION INPUT ;
    USE SIGNAL ;
    SHAPE ABUTMENT ;
    PORT
      LAYER M5 ;
      RECT 37.920 0.000 37.944 0.024 ;
    END
  END rr_addr[10]
  PIN rr_addr[11]
    DIRECTION INPUT ;
    USE SIGNAL ;
    SHAPE ABUTMENT ;
    PORT
      LAYER M5 ;
      RECT 38.016 0.000 38.040 0.024 ;
    END
  END rr_addr[11]
  PIN rr_addr[12]
    DIRECTION INPUT ;
    USE SIGNAL ;
    SHAPE ABUTMENT ;
    PORT
      LAYER M5 ;
      RECT 38.112 0.000 38.136 0.024 ;
    END
  END rr_addr[12]
  PIN rr_addr[13]
    DIRECTION INPUT ;
    USE SIGNAL ;
    SHAPE ABUTMENT ;
    PORT
      LAYER M5 ;
      RECT 38.208 0.000 38.232 0.024 ;
    END
  END rr_addr[13]
  PIN rr_addr[14]
    DIRECTION INPUT ;
    USE SIGNAL ;
    SHAPE ABUTMENT ;
    PORT
      LAYER M5 ;
      RECT 38.304 0.000 38.328 0.024 ;
    END
  END rr_addr[14]
  PIN rr_addr[15]
    DIRECTION INPUT ;
    USE SIGNAL ;
    SHAPE ABUTMENT ;
    PORT
      LAYER M5 ;
      RECT 38.400 0.000 38.424 0.024 ;
    END
  END rr_addr[15]
  PIN rr_addr[16]
    DIRECTION INPUT ;
    USE SIGNAL ;
    SHAPE ABUTMENT ;
    PORT
      LAYER M5 ;
      RECT 38.496 0.000 38.520 0.024 ;
    END
  END rr_addr[16]
  PIN rr_addr[17]
    DIRECTION INPUT ;
    USE SIGNAL ;
    SHAPE ABUTMENT ;
    PORT
      LAYER M5 ;
      RECT 38.592 0.000 38.616 0.024 ;
    END
  END rr_addr[17]
  PIN rr_addr[18]
    DIRECTION INPUT ;
    USE SIGNAL ;
    SHAPE ABUTMENT ;
    PORT
      LAYER M5 ;
      RECT 38.688 0.000 38.712 0.024 ;
    END
  END rr_addr[18]
  PIN rr_addr[19]
    DIRECTION INPUT ;
    USE SIGNAL ;
    SHAPE ABUTMENT ;
    PORT
      LAYER M5 ;
      RECT 38.784 0.000 38.808 0.024 ;
    END
  END rr_addr[19]
  PIN cr_en[0]
    DIRECTION INPUT ;
    USE SIGNAL ;
    SHAPE ABUTMENT ;
    PORT
      LAYER M5 ;
      RECT 38.880 0.000 38.904 0.024 ;
    END
  END cr_en[0]
  PIN cr_en[1]
    DIRECTION INPUT ;
    USE SIGNAL ;
    SHAPE ABUTMENT ;
    PORT
      LAYER M5 ;
      RECT 38.976 0.000 39.000 0.024 ;
    END
  END cr_en[1]
  PIN cr_sel[0]
    DIRECTION INPUT ;
    USE SIGNAL ;
    SHAPE ABUTMENT ;
    PORT
      LAYER M5 ;
      RECT 39.072 0.000 39.096 0.024 ;
    END
  END cr_sel[0]
  PIN cr_sel[1]
    DIRECTION INPUT ;
    USE SIGNAL ;
    SHAPE ABUTMENT ;
    PORT
      LAYER M5 ;
      RECT 39.168 0.000 39.192 0.024 ;
    END
  END cr_sel[1]
  PIN cr_sel[2]
    DIRECTION INPUT ;
    USE SIGNAL ;
    SHAPE ABUTMENT ;
    PORT
      LAYER M5 ;
      RECT 39.264 0.000 39.288 0.024 ;
    END
  END cr_sel[2]
  PIN cr_sel[3]
    DIRECTION INPUT ;
    USE SIGNAL ;
    SHAPE ABUTMENT ;
    PORT
      LAYER M5 ;
      RECT 39.360 0.000 39.384 0.024 ;
    END
  END cr_sel[3]
  PIN cr_sel[4]
    DIRECTION INPUT ;
    USE SIGNAL ;
    SHAPE ABUTMENT ;
    PORT
      LAYER M5 ;
      RECT 39.456 0.000 39.480 0.024 ;
    END
  END cr_sel[4]
  PIN cr_sel[5]
    DIRECTION INPUT ;
    USE SIGNAL ;
    SHAPE ABUTMENT ;
    PORT
      LAYER M5 ;
      RECT 39.552 0.000 39.576 0.024 ;
    END
  END cr_sel[5]
  PIN cr_sel[6]
    DIRECTION INPUT ;
    USE SIGNAL ;
    SHAPE ABUTMENT ;
    PORT
      LAYER M5 ;
      RECT 39.648 0.000 39.672 0.024 ;
    END
  END cr_sel[6]
  PIN cr_sel[7]
    DIRECTION INPUT ;
    USE SIGNAL ;
    SHAPE ABUTMENT ;
    PORT
      LAYER M5 ;
      RECT 39.744 0.000 39.768 0.024 ;
    END
  END cr_sel[7]
  PIN cr_sel[8]
    DIRECTION INPUT ;
    USE SIGNAL ;
    SHAPE ABUTMENT ;
    PORT
      LAYER M5 ;
      RECT 39.840 0.000 39.864 0.024 ;
    END
  END cr_sel[8]
  PIN cr_sel[9]
    DIRECTION INPUT ;
    USE SIGNAL ;
    SHAPE ABUTMENT ;
    PORT
      LAYER M5 ;
      RECT 39.936 0.000 39.960 0.024 ;
    END
  END cr_sel[9]
  PIN cr_sel[10]
    DIRECTION INPUT ;
    USE SIGNAL ;
    SHAPE ABUTMENT ;
    PORT
      LAYER M5 ;
      RECT 40.032 0.000 40.056 0.024 ;
    END
  END cr_sel[10]
  PIN cr_sel[11]
    DIRECTION INPUT ;
    USE SIGNAL ;
    SHAPE ABUTMENT ;
    PORT
      LAYER M5 ;
      RECT 40.128 0.000 40.152 0.024 ;
    END
  END cr_sel[11]
  PIN cr_sel[12]
    DIRECTION INPUT ;
    USE SIGNAL ;
    SHAPE ABUTMENT ;
    PORT
      LAYER M5 ;
      RECT 40.224 0.000 40.248 0.024 ;
    END
  END cr_sel[12]
  PIN cr_sel[13]
    DIRECTION INPUT ;
    USE SIGNAL ;
    SHAPE ABUTMENT ;
    PORT
      LAYER M5 ;
      RECT 40.320 0.000 40.344 0.024 ;
    END
  END cr_sel[13]
  PIN cr_sel[14]
    DIRECTION INPUT ;
    USE SIGNAL ;
    SHAPE ABUTMENT ;
    PORT
      LAYER M5 ;
      RECT 40.416 0.000 40.440 0.024 ;
    END
  END cr_sel[14]
  PIN cr_sel[15]
    DIRECTION INPUT ;
    USE SIGNAL ;
    SHAPE ABUTMENT ;
    PORT
      LAYER M5 ;
      RECT 40.512 0.000 40.536 0.024 ;
    END
  END cr_sel[15]
  PIN VDD
    DIRECTION INOUT ;
    USE POWER ;
    PORT
      LAYER M4 ;
      RECT 0.300 0.384 96.252 0.480 ;
      RECT 0.300 1.152 96.252 1.248 ;
      RECT 0.300 1.920 96.252 2.016 ;
      RECT 0.300 2.688 96.252 2.784 ;
      RECT 0.300 3.456 96.252 3.552 ;
      RECT 0.300 4.224 96.252 4.320 ;
      RECT 0.300 4.992 96.252 5.088 ;
      RECT 0.300 5.760 96.252 5.856 ;
      RECT 0.300 6.528 96.252 6.624 ;
      RECT 0.300 7.296 96.252 7.392 ;
      RECT 0.300 8.064 96.252 8.160 ;
      RECT 0.300 8.832 96.252 8.928 ;
      RECT 0.300 9.600 96.252 9.696 ;
      RECT 0.300 10.368 96.252 10.464 ;
      RECT 0.300 11.136 96.252 11.232 ;
      RECT 0.300 11.904 96.252 12.000 ;
      RECT 0.300 12.672 96.252 12.768 ;
      RECT 0.300 13.440 96.252 13.536 ;
      RECT 0.300 14.208 96.252 14.304 ;
      RECT 0.300 14.976 96.252 15.072 ;
      RECT 0.300 15.744 96.252 15.840 ;
      RECT 0.300 16.512 96.252 16.608 ;
      RECT 0.300 17.280 96.252 17.376 ;
      RECT 0.300 18.048 96.252 18.144 ;
      RECT 0.300 18.816 96.252 18.912 ;
      RECT 0.300 19.584 96.252 19.680 ;
      RECT 0.300 20.352 96.252 20.448 ;
      RECT 0.300 21.120 96.252 21.216 ;
      RECT 0.300 21.888 96.252 21.984 ;
      RECT 0.300 22.656 96.252 22.752 ;
      RECT 0.300 23.424 96.252 23.520 ;
      RECT 0.300 24.192 96.252 24.288 ;
      RECT 0.300 24.960 96.252 25.056 ;
      RECT 0.300 25.728 96.252 25.824 ;
      RECT 0.300 26.496 96.252 26.592 ;
      RECT 0.300 27.264 96.252 27.360 ;
      RECT 0.300 28.032 96.252 28.128 ;
      RECT 0.300 28.800 96.252 28.896 ;
      RECT 0.300 29.568 96.252 29.664 ;
      RECT 0.300 30.336 96.252 30.432 ;
      RECT 0.300 31.104 96.252 31.200 ;
      RECT 0.300 31.872 96.252 31.968 ;
      RECT 0.300 32.640 96.252 32.736 ;
      RECT 0.300 33.408 96.252 33.504 ;
      RECT 0.300 34.176 96.252 34.272 ;
      RECT 0.300 34.944 96.252 35.040 ;
      RECT 0.300 35.712 96.252 35.808 ;
      RECT 0.300 36.480 96.252 36.576 ;
      RECT 0.300 37.248 96.252 37.344 ;
      RECT 0.300 38.016 96.252 38.112 ;
      RECT 0.300 38.784 96.252 38.880 ;
      RECT 0.300 39.552 96.252 39.648 ;
      RECT 0.300 40.320 96.252 40.416 ;
      RECT 0.300 41.088 96.252 41.184 ;
      RECT 0.300 41.856 96.252 41.952 ;
      RECT 0.300 42.624 96.252 42.720 ;
      RECT 0.300 43.392 96.252 43.488 ;
      RECT 0.300 44.160 96.252 44.256 ;
      RECT 0.300 44.928 96.252 45.024 ;
      RECT 0.300 45.696 96.252 45.792 ;
      RECT 0.300 46.464 96.252 46.560 ;
      RECT 0.300 47.232 96.252 47.328 ;
      RECT 0.300 48.000 96.252 48.096 ;
      RECT 0.300 48.768 96.252 48.864 ;
      RECT 0.300 49.536 96.252 49.632 ;
      RECT 0.300 50.304 96.252 50.400 ;
      RECT 0.300 51.072 96.252 51.168 ;
      RECT 0.300 51.840 96.252 51.936 ;
      RECT 0.300 52.608 96.252 52.704 ;
      RECT 0.300 53.376 96.252 53.472 ;
      RECT 0.300 54.144 96.252 54.240 ;
      RECT 0.300 54.912 96.252 55.008 ;
      RECT 0.300 55.680 96.252 55.776 ;
      RECT 0.300 56.448 96.252 56.544 ;
      RECT 0.300 57.216 96.252 57.312 ;
      RECT 0.300 57.984 96.252 58.080 ;
      RECT 0.300 58.752 96.252 58.848 ;
      RECT 0.300 59.520 96.252 59.616 ;
      RECT 0.300 60.288 96.252 60.384 ;
      RECT 0.300 61.056 96.252 61.152 ;
      RECT 0.300 61.824 96.252 61.920 ;
      RECT 0.300 62.592 96.252 62.688 ;
      RECT 0.300 63.360 96.252 63.456 ;
      RECT 0.300 64.128 96.252 64.224 ;
      RECT 0.300 64.896 96.252 64.992 ;
      RECT 0.300 65.664 96.252 65.760 ;
      RECT 0.300 66.432 96.252 66.528 ;
      RECT 0.300 67.200 96.252 67.296 ;
      RECT 0.300 67.968 96.252 68.064 ;
      RECT 0.300 68.736 96.252 68.832 ;
      RECT 0.300 69.504 96.252 69.600 ;
      RECT 0.300 70.272 96.252 70.368 ;
      RECT 0.300 71.040 96.252 71.136 ;
      RECT 0.300 71.808 96.252 71.904 ;
      RECT 0.300 72.576 96.252 72.672 ;
      RECT 0.300 73.344 96.252 73.440 ;
      RECT 0.300 74.112 96.252 74.208 ;
      RECT 0.300 74.880 96.252 74.976 ;
      RECT 0.300 75.648 96.252 75.744 ;
      RECT 0.300 76.416 96.252 76.512 ;
      RECT 0.300 77.184 96.252 77.280 ;
      RECT 0.300 77.952 96.252 78.048 ;
      RECT 0.300 78.720 96.252 78.816 ;
      RECT 0.300 79.488 96.252 79.584 ;
      RECT 0.300 80.256 96.252 80.352 ;
      RECT 0.300 81.024 96.252 81.120 ;
      RECT 0.300 81.792 96.252 81.888 ;
      RECT 0.300 82.560 96.252 82.656 ;
      RECT 0.300 83.328 96.252 83.424 ;
      RECT 0.300 84.096 96.252 84.192 ;
      RECT 0.300 84.864 96.252 84.960 ;
      RECT 0.300 85.632 96.252 85.728 ;
      RECT 0.300 86.400 96.252 86.496 ;
      RECT 0.300 87.168 96.252 87.264 ;
      RECT 0.300 87.936 96.252 88.032 ;
      RECT 0.300 88.704 96.252 88.800 ;
      RECT 0.300 89.472 96.252 89.568 ;
      RECT 0.300 90.240 96.252 90.336 ;
      RECT 0.300 91.008 96.252 91.104 ;
      RECT 0.300 91.776 96.252 91.872 ;
      RECT 0.300 92.544 96.252 92.640 ;
      RECT 0.300 93.312 96.252 93.408 ;
      RECT 0.300 94.080 96.252 94.176 ;
      RECT 0.300 94.848 96.252 94.944 ;
      RECT 0.300 95.616 96.252 95.712 ;
      RECT 0.300 96.384 96.252 96.480 ;
      RECT 0.300 97.152 96.252 97.248 ;
      RECT 0.300 97.920 96.252 98.016 ;
      RECT 0.300 98.688 96.252 98.784 ;
      RECT 0.300 99.456 96.252 99.552 ;
      RECT 0.300 100.224 96.252 100.320 ;
      RECT 0.300 100.992 96.252 101.088 ;
      RECT 0.300 101.760 96.252 101.856 ;
      RECT 0.300 102.528 96.252 102.624 ;
      RECT 0.300 103.296 96.252 103.392 ;
      RECT 0.300 104.064 96.252 104.160 ;
      RECT 0.300 104.832 96.252 104.928 ;
      RECT 0.300 105.600 96.252 105.696 ;
      RECT 0.300 106.368 96.252 106.464 ;
      RECT 0.300 107.136 96.252 107.232 ;
      RECT 0.300 107.904 96.252 108.000 ;
      RECT 0.300 108.672 96.252 108.768 ;
      RECT 0.300 109.440 96.252 109.536 ;
      RECT 0.300 110.208 96.252 110.304 ;
      RECT 0.300 110.976 96.252 111.072 ;
      RECT 0.300 111.744 96.252 111.840 ;
      RECT 0.300 112.512 96.252 112.608 ;
      RECT 0.300 113.280 96.252 113.376 ;
      RECT 0.300 114.048 96.252 114.144 ;
      RECT 0.300 114.816 96.252 114.912 ;
      RECT 0.300 115.584 96.252 115.680 ;
      RECT 0.300 116.352 96.252 116.448 ;
      RECT 0.300 117.120 96.252 117.216 ;
      RECT 0.300 117.888 96.252 117.984 ;
      RECT 0.300 118.656 96.252 118.752 ;
      RECT 0.300 119.424 96.252 119.520 ;
      RECT 0.300 120.192 96.252 120.288 ;
      RECT 0.300 120.960 96.252 121.056 ;
      RECT 0.300 121.728 96.252 121.824 ;
      RECT 0.300 122.496 96.252 122.592 ;
      RECT 0.300 123.264 96.252 123.360 ;
      RECT 0.300 124.032 96.252 124.128 ;
      RECT 0.300 124.800 96.252 124.896 ;
      RECT 0.300 125.568 96.252 125.664 ;
      RECT 0.300 126.336 96.252 126.432 ;
      RECT 0.300 127.104 96.252 127.200 ;
      RECT 0.300 127.872 96.252 127.968 ;
      RECT 0.300 128.640 96.252 128.736 ;
      RECT 0.300 129.408 96.252 129.504 ;
      RECT 0.300 130.176 96.252 130.272 ;
      RECT 0.300 130.944 96.252 131.040 ;
      RECT 0.300 131.712 96.252 131.808 ;
      RECT 0.300 132.480 96.252 132.576 ;
      RECT 0.300 133.248 96.252 133.344 ;
      RECT 0.300 134.016 96.252 134.112 ;
      RECT 0.300 134.784 96.252 134.880 ;
      RECT 0.300 135.552 96.252 135.648 ;
      RECT 0.300 136.320 96.252 136.416 ;
      RECT 0.300 137.088 96.252 137.184 ;
      RECT 0.300 137.856 96.252 137.952 ;
      RECT 0.300 138.624 96.252 138.720 ;
      RECT 0.300 139.392 96.252 139.488 ;
      RECT 0.300 140.160 96.252 140.256 ;
    END
  END VDD
  PIN VSS
    DIRECTION INOUT ;
    USE GROUND ;
    PORT
      LAYER M4 ;
      RECT 0.300 0.768 96.252 0.864 ;
      RECT 0.300 1.536 96.252 1.632 ;
      RECT 0.300 2.304 96.252 2.400 ;
      RECT 0.300 3.072 96.252 3.168 ;
      RECT 0.300 3.840 96.252 3.936 ;
      RECT 0.300 4.608 96.252 4.704 ;
      RECT 0.300 5.376 96.252 5.472 ;
      RECT 0.300 6.144 96.252 6.240 ;
      RECT 0.300 6.912 96.252 7.008 ;
      RECT 0.300 7.680 96.252 7.776 ;
      RECT 0.300 8.448 96.252 8.544 ;
      RECT 0.300 9.216 96.252 9.312 ;
      RECT 0.300 9.984 96.252 10.080 ;
      RECT 0.300 10.752 96.252 10.848 ;
      RECT 0.300 11.520 96.252 11.616 ;
      RECT 0.300 12.288 96.252 12.384 ;
      RECT 0.300 13.056 96.252 13.152 ;
      RECT 0.300 13.824 96.252 13.920 ;
      RECT 0.300 14.592 96.252 14.688 ;
      RECT 0.300 15.360 96.252 15.456 ;
      RECT 0.300 16.128 96.252 16.224 ;
      RECT 0.300 16.896 96.252 16.992 ;
      RECT 0.300 17.664 96.252 17.760 ;
      RECT 0.300 18.432 96.252 18.528 ;
      RECT 0.300 19.200 96.252 19.296 ;
      RECT 0.300 19.968 96.252 20.064 ;
      RECT 0.300 20.736 96.252 20.832 ;
      RECT 0.300 21.504 96.252 21.600 ;
      RECT 0.300 22.272 96.252 22.368 ;
      RECT 0.300 23.040 96.252 23.136 ;
      RECT 0.300 23.808 96.252 23.904 ;
      RECT 0.300 24.576 96.252 24.672 ;
      RECT 0.300 25.344 96.252 25.440 ;
      RECT 0.300 26.112 96.252 26.208 ;
      RECT 0.300 26.880 96.252 26.976 ;
      RECT 0.300 27.648 96.252 27.744 ;
      RECT 0.300 28.416 96.252 28.512 ;
      RECT 0.300 29.184 96.252 29.280 ;
      RECT 0.300 29.952 96.252 30.048 ;
      RECT 0.300 30.720 96.252 30.816 ;
      RECT 0.300 31.488 96.252 31.584 ;
      RECT 0.300 32.256 96.252 32.352 ;
      RECT 0.300 33.024 96.252 33.120 ;
      RECT 0.300 33.792 96.252 33.888 ;
      RECT 0.300 34.560 96.252 34.656 ;
      RECT 0.300 35.328 96.252 35.424 ;
      RECT 0.300 36.096 96.252 36.192 ;
      RECT 0.300 36.864 96.252 36.960 ;
      RECT 0.300 37.632 96.252 37.728 ;
      RECT 0.300 38.400 96.252 38.496 ;
      RECT 0.300 39.168 96.252 39.264 ;
      RECT 0.300 39.936 96.252 40.032 ;
      RECT 0.300 40.704 96.252 40.800 ;
      RECT 0.300 41.472 96.252 41.568 ;
      RECT 0.300 42.240 96.252 42.336 ;
      RECT 0.300 43.008 96.252 43.104 ;
      RECT 0.300 43.776 96.252 43.872 ;
      RECT 0.300 44.544 96.252 44.640 ;
      RECT 0.300 45.312 96.252 45.408 ;
      RECT 0.300 46.080 96.252 46.176 ;
      RECT 0.300 46.848 96.252 46.944 ;
      RECT 0.300 47.616 96.252 47.712 ;
      RECT 0.300 48.384 96.252 48.480 ;
      RECT 0.300 49.152 96.252 49.248 ;
      RECT 0.300 49.920 96.252 50.016 ;
      RECT 0.300 50.688 96.252 50.784 ;
      RECT 0.300 51.456 96.252 51.552 ;
      RECT 0.300 52.224 96.252 52.320 ;
      RECT 0.300 52.992 96.252 53.088 ;
      RECT 0.300 53.760 96.252 53.856 ;
      RECT 0.300 54.528 96.252 54.624 ;
      RECT 0.300 55.296 96.252 55.392 ;
      RECT 0.300 56.064 96.252 56.160 ;
      RECT 0.300 56.832 96.252 56.928 ;
      RECT 0.300 57.600 96.252 57.696 ;
      RECT 0.300 58.368 96.252 58.464 ;
      RECT 0.300 59.136 96.252 59.232 ;
      RECT 0.300 59.904 96.252 60.000 ;
      RECT 0.300 60.672 96.252 60.768 ;
      RECT 0.300 61.440 96.252 61.536 ;
      RECT 0.300 62.208 96.252 62.304 ;
      RECT 0.300 62.976 96.252 63.072 ;
      RECT 0.300 63.744 96.252 63.840 ;
      RECT 0.300 64.512 96.252 64.608 ;
      RECT 0.300 65.280 96.252 65.376 ;
      RECT 0.300 66.048 96.252 66.144 ;
      RECT 0.300 66.816 96.252 66.912 ;
      RECT 0.300 67.584 96.252 67.680 ;
      RECT 0.300 68.352 96.252 68.448 ;
      RECT 0.300 69.120 96.252 69.216 ;
      RECT 0.300 69.888 96.252 69.984 ;
      RECT 0.300 70.656 96.252 70.752 ;
      RECT 0.300 71.424 96.252 71.520 ;
      RECT 0.300 72.192 96.252 72.288 ;
      RECT 0.300 72.960 96.252 73.056 ;
      RECT 0.300 73.728 96.252 73.824 ;
      RECT 0.300 74.496 96.252 74.592 ;
      RECT 0.300 75.264 96.252 75.360 ;
      RECT 0.300 76.032 96.252 76.128 ;
      RECT 0.300 76.800 96.252 76.896 ;
      RECT 0.300 77.568 96.252 77.664 ;
      RECT 0.300 78.336 96.252 78.432 ;
      RECT 0.300 79.104 96.252 79.200 ;
      RECT 0.300 79.872 96.252 79.968 ;
      RECT 0.300 80.640 96.252 80.736 ;
      RECT 0.300 81.408 96.252 81.504 ;
      RECT 0.300 82.176 96.252 82.272 ;
      RECT 0.300 82.944 96.252 83.040 ;
      RECT 0.300 83.712 96.252 83.808 ;
      RECT 0.300 84.480 96.252 84.576 ;
      RECT 0.300 85.248 96.252 85.344 ;
      RECT 0.300 86.016 96.252 86.112 ;
      RECT 0.300 86.784 96.252 86.880 ;
      RECT 0.300 87.552 96.252 87.648 ;
      RECT 0.300 88.320 96.252 88.416 ;
      RECT 0.300 89.088 96.252 89.184 ;
      RECT 0.300 89.856 96.252 89.952 ;
      RECT 0.300 90.624 96.252 90.720 ;
      RECT 0.300 91.392 96.252 91.488 ;
      RECT 0.300 92.160 96.252 92.256 ;
      RECT 0.300 92.928 96.252 93.024 ;
      RECT 0.300 93.696 96.252 93.792 ;
      RECT 0.300 94.464 96.252 94.560 ;
      RECT 0.300 95.232 96.252 95.328 ;
      RECT 0.300 96.000 96.252 96.096 ;
      RECT 0.300 96.768 96.252 96.864 ;
      RECT 0.300 97.536 96.252 97.632 ;
      RECT 0.300 98.304 96.252 98.400 ;
      RECT 0.300 99.072 96.252 99.168 ;
      RECT 0.300 99.840 96.252 99.936 ;
      RECT 0.300 100.608 96.252 100.704 ;
      RECT 0.300 101.376 96.252 101.472 ;
      RECT 0.300 102.144 96.252 102.240 ;
      RECT 0.300 102.912 96.252 103.008 ;
      RECT 0.300 103.680 96.252 103.776 ;
      RECT 0.300 104.448 96.252 104.544 ;
      RECT 0.300 105.216 96.252 105.312 ;
      RECT 0.300 105.984 96.252 106.080 ;
      RECT 0.300 106.752 96.252 106.848 ;
      RECT 0.300 107.520 96.252 107.616 ;
      RECT 0.300 108.288 96.252 108.384 ;
      RECT 0.300 109.056 96.252 109.152 ;
      RECT 0.300 109.824 96.252 109.920 ;
      RECT 0.300 110.592 96.252 110.688 ;
      RECT 0.300 111.360 96.252 111.456 ;
      RECT 0.300 112.128 96.252 112.224 ;
      RECT 0.300 112.896 96.252 112.992 ;
      RECT 0.300 113.664 96.252 113.760 ;
      RECT 0.300 114.432 96.252 114.528 ;
      RECT 0.300 115.200 96.252 115.296 ;
      RECT 0.300 115.968 96.252 116.064 ;
      RECT 0.300 116.736 96.252 116.832 ;
      RECT 0.300 117.504 96.252 117.600 ;
      RECT 0.300 118.272 96.252 118.368 ;
      RECT 0.300 119.040 96.252 119.136 ;
      RECT 0.300 119.808 96.252 119.904 ;
      RECT 0.300 120.576 96.252 120.672 ;
      RECT 0.300 121.344 96.252 121.440 ;
      RECT 0.300 122.112 96.252 122.208 ;
      RECT 0.300 122.880 96.252 122.976 ;
      RECT 0.300 123.648 96.252 123.744 ;
      RECT 0.300 124.416 96.252 124.512 ;
      RECT 0.300 125.184 96.252 125.280 ;
      RECT 0.300 125.952 96.252 126.048 ;
      RECT 0.300 126.720 96.252 126.816 ;
      RECT 0.300 127.488 96.252 127.584 ;
      RECT 0.300 128.256 96.252 128.352 ;
      RECT 0.300 129.024 96.252 129.120 ;
      RECT 0.300 129.792 96.252 129.888 ;
      RECT 0.300 130.560 96.252 130.656 ;
      RECT 0.300 131.328 96.252 131.424 ;
      RECT 0.300 132.096 96.252 132.192 ;
      RECT 0.300 132.864 96.252 132.960 ;
      RECT 0.300 133.632 96.252 133.728 ;
      RECT 0.300 134.400 96.252 134.496 ;
      RECT 0.300 135.168 96.252 135.264 ;
      RECT 0.300 135.936 96.252 136.032 ;
      RECT 0.300 136.704 96.252 136.800 ;
      RECT 0.300 137.472 96.252 137.568 ;
      RECT 0.300 138.240 96.252 138.336 ;
      RECT 0.300 139.008 96.252 139.104 ;
      RECT 0.300 139.776 96.252 139.872 ;
    END
  END VSS
  OBS
    LAYER M1 ;
    RECT 0 0 96.552 140.424 ;
    LAYER M2 ;
    RECT 0 0 96.552 140.424 ;
    LAYER M3 ;
    RECT 0 0 96.552 140.424 ;
    LAYER M4 ;
    RECT 0.072 0 96.480 140.424 ;
  END
END ot_sram_1r1w_1024x256_m1b2_r2c2_ns

END LIBRARY
